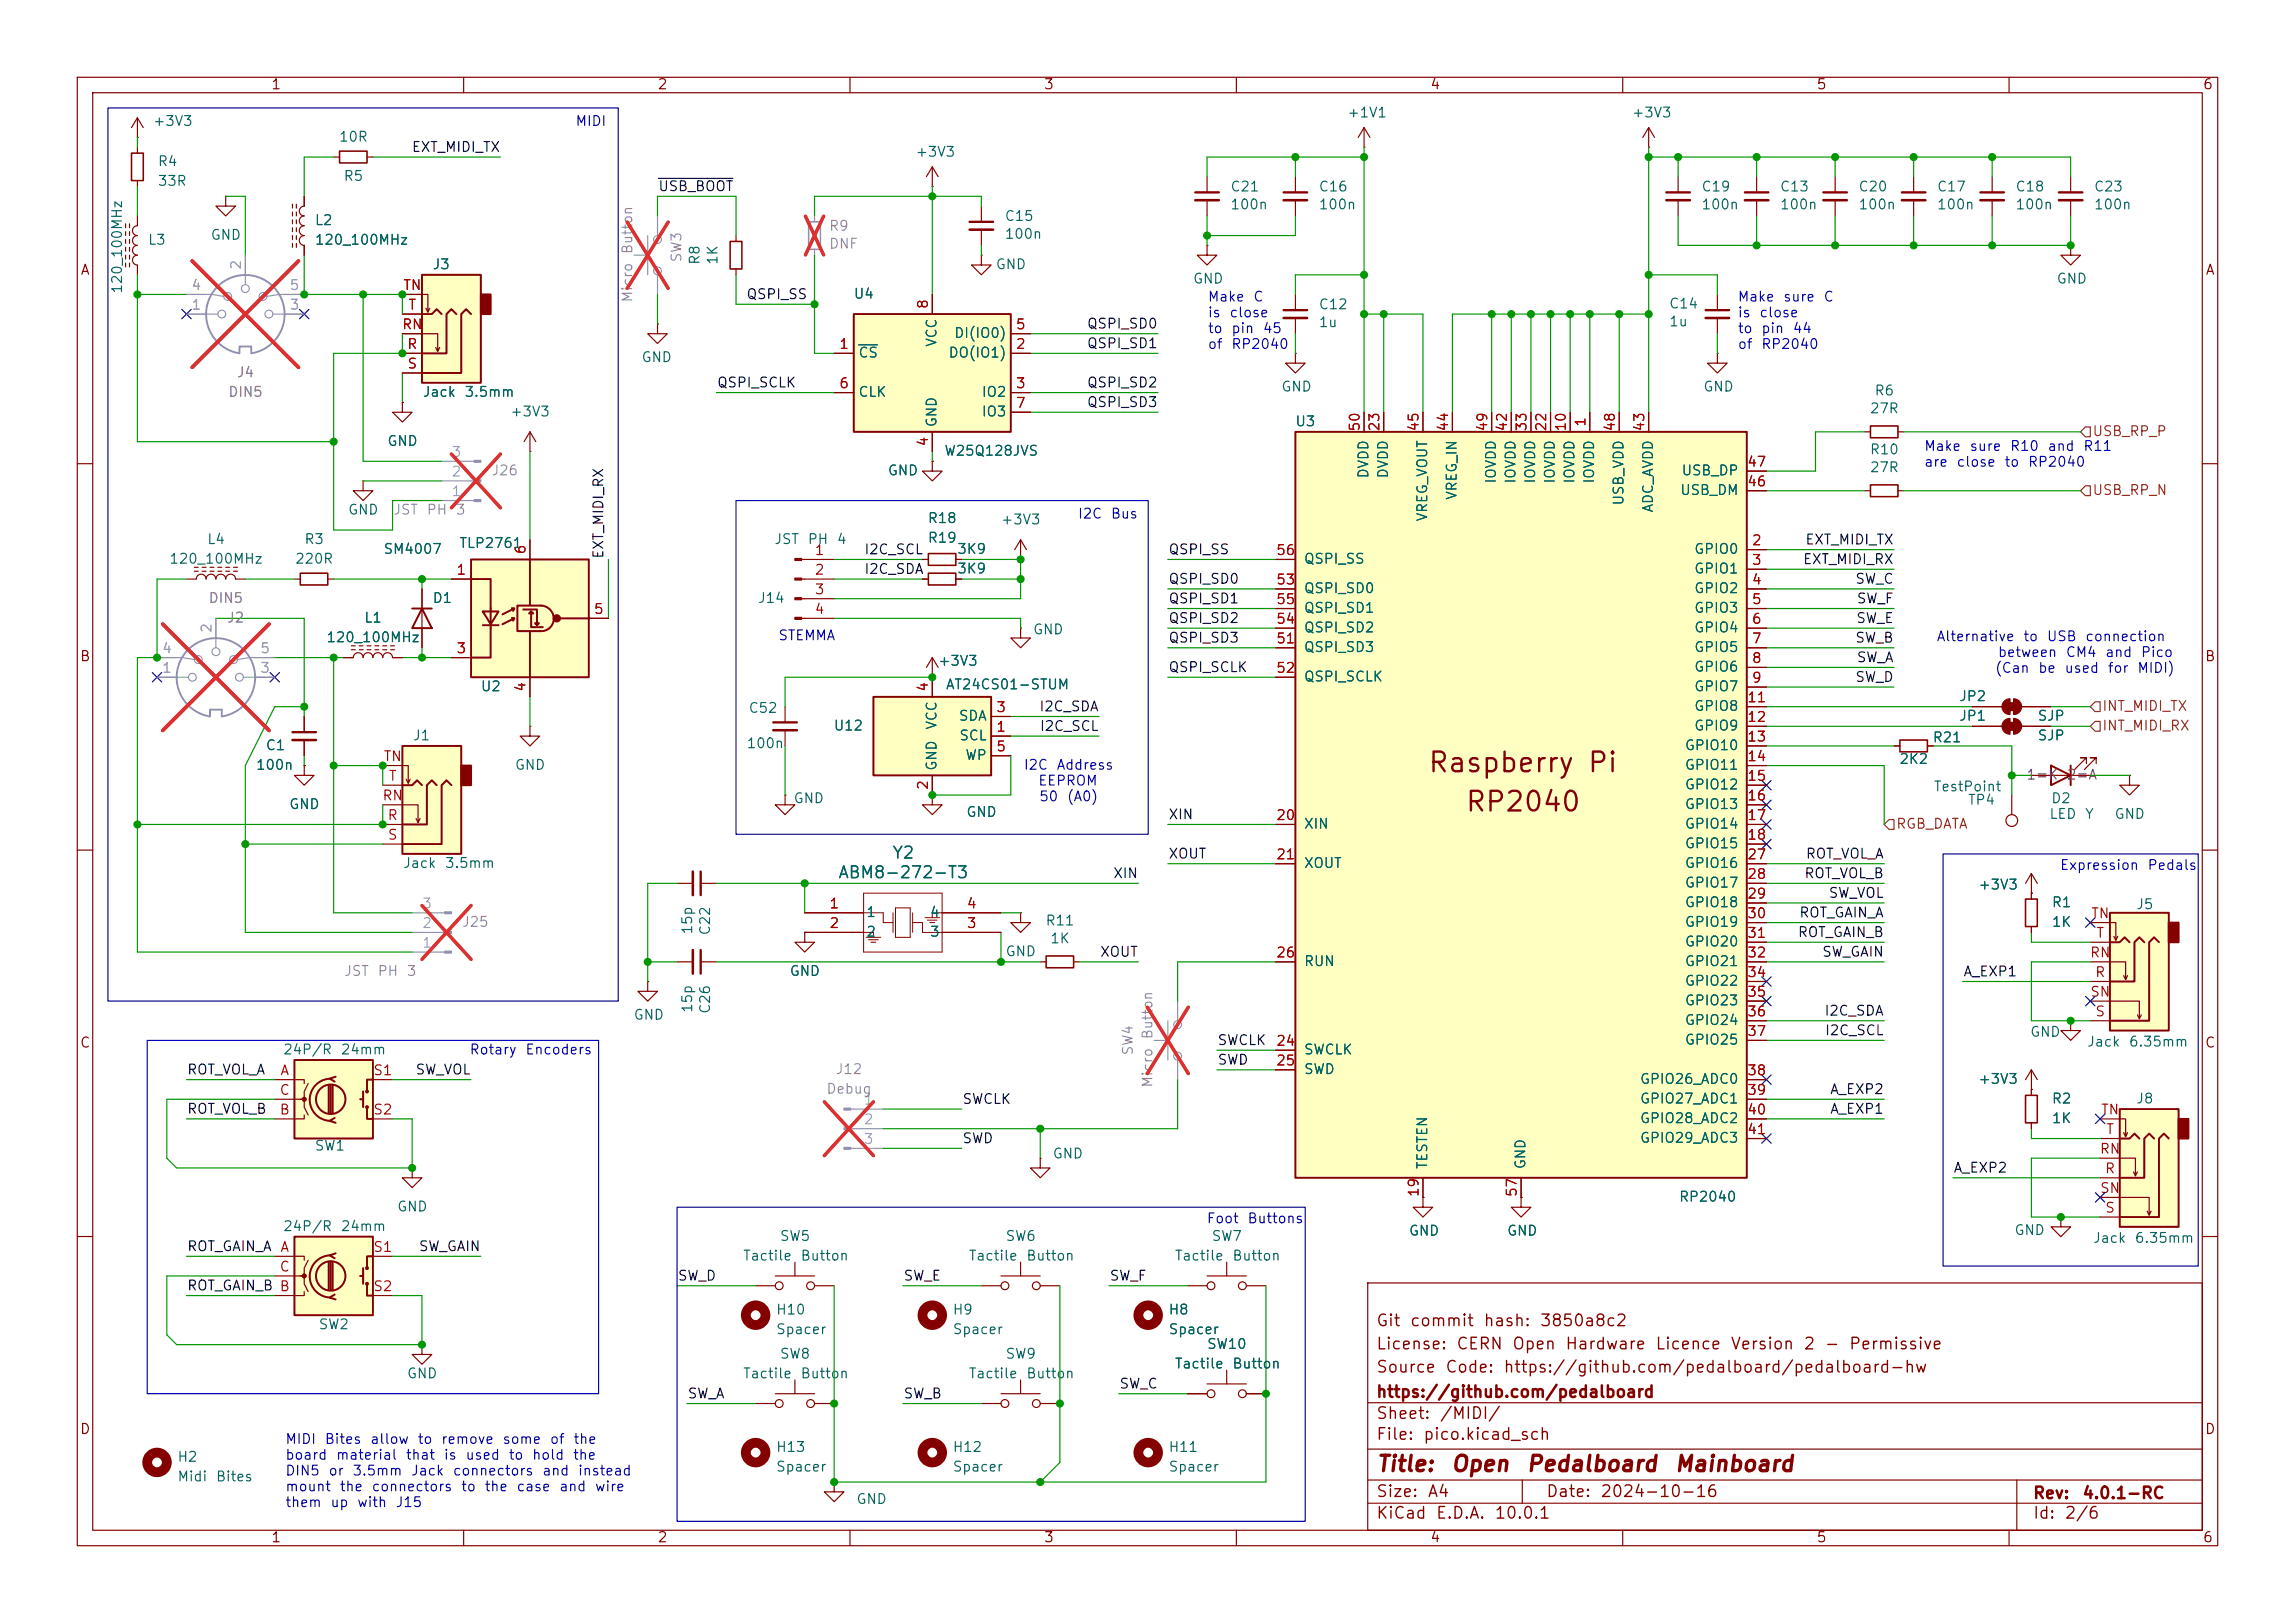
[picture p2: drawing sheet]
<svg xmlns="http://www.w3.org/2000/svg" width="297mm" height="210mm" viewBox="0 0 297 210" stroke-linecap="round" stroke-linejoin="round" font-family="sans-serif">
<defs><g id="words">
<g font-size="2.5" fill="#840000">
<text x="184.7" y="100.6">Raspberry Pi</text>
<text x="189.5" y="105.6">RP2040</text>
</g>
<g font-size="2" fill="#840000">
<text x="178" y="190.9">Title:</text>
<text x="187.7" y="190.9">Open</text>
<text x="197.4" y="190.9">Pedalboard</text>
<text x="216.6" y="190.9">Mainboard</text>
</g>
<g font-size="1.5" fill="#006464">
<text x="115.4" y="111.5">Y2</text>
<text x="108.4" y="114">ABM8-272-T3</text>
</g>
<g font-size="1.5" fill="#840000">
<text x="178" y="172">Git</text>
<text x="182.4" y="172">commit</text>
<text x="191.9" y="172">hash:</text>
<text x="199.2" y="172">3850a8c2</text>
<text x="178" y="178">Source</text>
<text x="178" y="175">License:</text>
<text x="186.9" y="178">Code:</text>
<text x="188.4" y="175">CERN</text>
<text x="194.5" y="178">https://github.com/pedalboard/pedalboard-hw</text>
<text x="195.6" y="175">Open</text>
<text x="202.5" y="175">Hardware</text>
<text x="214.1" y="175">Licence</text>
<text x="223.9" y="175">Version</text>
<text x="233.3" y="175">2</text>
<text x="236" y="175">-</text>
<text x="239.2" y="175">Permissive</text>
<text x="178" y="184">Sheet:</text>
<text x="178" y="181.2">https://github.com/pedalboard</text>
<text x="186.2" y="184">/MIDI/</text>
<text x="178" y="186.7">File:</text>
<text x="184.1" y="186.7">pico.kicad_sch</text>
<text x="178" y="196.9">KiCad</text>
<text x="178" y="194.1">Size:</text>
<text x="184.7" y="194.1">A4</text>
<text x="185.7" y="196.9">E.D.A.</text>
<text x="193.3" y="196.9">10.0.1</text>
<text x="200" y="194.1">Date:</text>
<text x="207" y="194.1">2024-10-16</text>
<text x="263" y="194.3">Rev:</text>
<text x="263" y="196.9">Id:</text>
<text x="267.1" y="196.9">2/6</text>
<text x="269.4" y="194.3">4.0.1-RC</text>
</g>
<g font-size="1.3" fill="#840000">
<text x="35" y="11.9">1</text>
<text x="85" y="11.9">2</text>
<text x="135" y="11.9">3</text>
<text x="185" y="11.9">4</text>
<text x="235" y="11.9">5</text>
<text x="285" y="11.9">6</text>
<text x="10.3" y="35.9">A</text>
<text x="285.3" y="35.9">A</text>
<text x="10.3" y="85.9">B</text>
<text x="285.3" y="85.9">B</text>
<text x="10.3" y="135.9">C</text>
<text x="285.3" y="135.9">C</text>
<text x="10.3" y="185.9">D</text>
<text x="285.3" y="185.9">D</text>
<text x="35" y="199.9">1</text>
<text x="85" y="199.9">2</text>
<text x="135" y="199.9">3</text>
<text x="185" y="199.9">4</text>
<text x="235" y="199.9">5</text>
<text x="285" y="199.9">6</text>
</g>
<g font-size="1.3" fill="#006464">
<text x="19.7" y="16.6">+3V3</text>
<text x="174.3" y="15.5">+1V1</text>
<text x="211.1" y="15.5">+3V3</text>
<text x="20.3" y="21.8">R4</text>
<text x="43.8" y="18.6">10R</text>
<text x="44.4" y="23.7">R5</text>
<text x="118.4" y="20.6">+3V3</text>
<text x="20.3" y="24.4">33R</text>
<text x="40.6" y="29.4">L2</text>
<text x="129.9" y="28.9">C15</text>
<text x="159.1" y="27.4">100n</text>
<text x="159.1" y="25.1">C21</text>
<text x="170.6" y="27.4">100n</text>
<text x="170.6" y="25.1">C16</text>
<text x="220.1" y="27.4">100n</text>
<text x="220.1" y="25.1">C19</text>
<text x="230.3" y="27.4">100n</text>
<text x="230.3" y="25.1">C13</text>
<text x="240.4" y="27.4">100n</text>
<text x="240.4" y="25.1">C20</text>
<text x="250.6" y="27.4">100n</text>
<text x="250.6" y="25.1">C17</text>
<text x="260.7" y="27.4">100n</text>
<text x="260.7" y="25.1">C18</text>
<text x="270.9" y="27.4">100n</text>
<text x="270.9" y="25.1">C23</text>
<text x="19.1" y="32">L3</text>
<text x="27.2" y="31.3">GND</text>
<text x="40.6" y="32">120_100MHz</text>
<text x="55.9" y="35.2">J3</text>
<text x="90.9" y="34.4" transform="rotate(-90 90.9 34.4)">R8</text>
<text x="93.2" y="34.4" transform="rotate(-90 93.2 34.4)">1K</text>
<text x="128.8" y="35.2">GND</text>
<text x="129.9" y="31.2">100n</text>
<text x="16.1" y="38.1" transform="rotate(-90 16.1 38.1)">120_100MHz</text>
<text x="110.4" y="39">U4</text>
<text x="154.3" y="37">GND</text>
<text x="170.6" y="40.3">C12</text>
<text x="215.9" y="40.2">C14</text>
<text x="266.1" y="37">GND</text>
<text x="82.9" y="47.2">GND</text>
<text x="111" y="46.6">CS</text>
<text x="121.5" y="45" transform="rotate(-90 121.5 45)">VCC</text>
<text x="122.7" y="46.6">DO(IO1)</text>
<text x="123.4" y="44">DI(IO0)</text>
<text x="170.6" y="42.6">1u</text>
<text x="215.9" y="42.5">1u</text>
<text x="54.6" y="51.7">Jack</text>
<text x="60" y="51.7">3.5mm</text>
<text x="111" y="51.7">CLK</text>
<text x="127" y="51.7">IO2</text>
<text x="165.7" y="51">GND</text>
<text x="220.3" y="51">GND</text>
<text x="241.9" y="53.8">27R</text>
<text x="242.5" y="51.5">R6</text>
<text x="50" y="58">GND</text>
<text x="65.9" y="54.2">+3V3</text>
<text x="121.5" y="55.4" transform="rotate(-90 121.5 55.4)">GND</text>
<text x="122.1" y="59.3">W25Q128JVS</text>
<text x="127" y="54.2">IO3</text>
<text x="167.5" y="55.5">U3</text>
<text x="241.9" y="59.1">R10</text>
<text x="114.8" y="61.8">GND</text>
<text x="177.4" y="62" transform="rotate(-90 177.4 62)">DVDD</text>
<text x="179.9" y="62" transform="rotate(-90 179.9 62)">DVDD</text>
<text x="188.8" y="64.8" transform="rotate(-90 188.8 64.8)">VREG_IN</text>
<text x="193.9" y="62.7" transform="rotate(-90 193.9 62.7)">IOVDD</text>
<text x="196.4" y="62.7" transform="rotate(-90 196.4 62.7)">IOVDD</text>
<text x="199" y="62.7" transform="rotate(-90 199 62.7)">IOVDD</text>
<text x="201.5" y="62.7" transform="rotate(-90 201.5 62.7)">IOVDD</text>
<text x="204.1" y="62.7" transform="rotate(-90 204.1 62.7)">IOVDD</text>
<text x="206.6" y="62.7" transform="rotate(-90 206.6 62.7)">IOVDD</text>
<text x="210.4" y="65.5" transform="rotate(-90 210.4 65.5)">USB_VDD</text>
<text x="217.3" y="64.4">USB_DM</text>
<text x="217.5" y="61.8">USB_DP</text>
<text x="241.9" y="61.4">27R</text>
<text x="26.7" y="70.7">L4</text>
<text x="39.3" y="70.7">R3</text>
<text x="45" y="66.9">GND</text>
<text x="49.5" y="72">SM4007</text>
<text x="59.3" y="71.2">TLP2761</text>
<text x="100.1" y="70.7">JST</text>
<text x="104.4" y="70.7">PH</text>
<text x="108.2" y="70.7">4</text>
<text x="120" y="70.5">R19</text>
<text x="120" y="68">R18</text>
<text x="123.8" y="72">3K9</text>
<text x="129.4" y="68.2">+3V3</text>
<text x="185" y="67.6" transform="rotate(-90 185 67.6)">VREG_VOUT</text>
<text x="214.2" y="66.4" transform="rotate(-90 214.2 66.4)">ADC_AVDD</text>
<text x="219.2" y="72">GPIO0</text>
<text x="21.8" y="73.3">120_100MHz</text>
<text x="38.1" y="73.3">220R</text>
<text x="123.8" y="74.5">3K9</text>
<text x="168.7" y="77.1">QSPI_SD0</text>
<text x="168.7" y="73.3">QSPI_SS</text>
<text x="219.2" y="74.5">GPIO1</text>
<text x="219.2" y="77.1">GPIO2</text>
<text x="42.1" y="83.4">120_100MHz</text>
<text x="47" y="80.9">L1</text>
<text x="55.9" y="78.3">D1</text>
<text x="98" y="78.3">J14</text>
<text x="133.6" y="82.4">GND</text>
<text x="168.7" y="82.1">QSPI_SD2</text>
<text x="168.7" y="79.6">QSPI_SD1</text>
<text x="219.2" y="79.6">GPIO3</text>
<text x="219.2" y="82.1">GPIO4</text>
<text x="62.1" y="89.8">U2</text>
<text x="121.3" y="86.5">+3V3</text>
<text x="122.3" y="89.5">AT24CS01-STUM</text>
<text x="168.7" y="84.7">QSPI_SD3</text>
<text x="168.7" y="88.5">QSPI_SCLK</text>
<text x="219.2" y="84.7">GPIO5</text>
<text x="219.2" y="87.2">GPIO6</text>
<text x="219.2" y="89.8">GPIO7</text>
<text x="96.8" y="92.6">C52</text>
<text x="107.8" y="94.8">U12</text>
<text x="121.5" y="94.5" transform="rotate(-90 121.5 94.5)">VCC</text>
<text x="124" y="93.6">SDA</text>
<text x="219.2" y="92.3">GPIO8</text>
<text x="219.2" y="94.8">GPIO9</text>
<text x="253.4" y="93.6">JP1</text>
<text x="253.4" y="91">JP2</text>
<text x="263.6" y="93.6">SJP</text>
<text x="33" y="99.9">100n</text>
<text x="34.3" y="97.4">C1</text>
<text x="53.3" y="96.1">J1</text>
<text x="66.5" y="99.9">GND</text>
<text x="96.5" y="97.1">100n</text>
<text x="121.5" y="99.8" transform="rotate(-90 121.5 99.8)">GND</text>
<text x="124.1" y="96.1">SCL</text>
<text x="124.8" y="98.7">WP</text>
<text x="217.9" y="97.4">GPIO10</text>
<text x="217.9" y="99.9">GPIO11</text>
<text x="245.7" y="99.2">2K2</text>
<text x="250" y="96.4">R21</text>
<text x="263.6" y="96.1">SJP</text>
<text x="37.3" y="105">GND</text>
<text x="102.6" y="104.2">GND</text>
<text x="125" y="106">GND</text>
<text x="168.7" y="107.5">XIN</text>
<text x="217.9" y="102.5">GPIO12</text>
<text x="217.9" y="105">GPIO13</text>
<text x="217.9" y="107.5">GPIO14</text>
<text x="250.2" y="102.7">TestPoint</text>
<text x="254.6" y="104.4">TP4</text>
<text x="265.1" y="106.3">LED</text>
<text x="265.4" y="104.2">D2</text>
<text x="269.7" y="106.3">Y</text>
<text x="273.6" y="106.3">GND</text>
<text x="52.1" y="112.6">Jack</text>
<text x="57.5" y="112.6">3.5mm</text>
<text x="168.7" y="112.6">XOUT</text>
<text x="217.9" y="110.1">GPIO15</text>
<text x="217.9" y="112.6">GPIO16</text>
<text x="112" y="119">1</text>
<text x="120.3" y="119">4</text>
<text x="217.9" y="115.2">GPIO17</text>
<text x="217.9" y="117.7">GPIO18</text>
<text x="255.9" y="115.4">+3V3</text>
<text x="265.4" y="117.7">R1</text>
<text x="276.4" y="118">J5</text>
<text x="89.9" y="121" transform="rotate(-90 89.9 121)">15p</text>
<text x="92.2" y="121.1" transform="rotate(-90 92.2 121.1)">C22</text>
<text x="112" y="121.5">2</text>
<text x="120.3" y="121.5">3</text>
<text x="130" y="124.1">GND</text>
<text x="135.2" y="120.1">R11</text>
<text x="135.8" y="122.4">1K</text>
<text x="168.7" y="125.3">RUN</text>
<text x="217.9" y="120.2">GPIO19</text>
<text x="217.9" y="122.8">GPIO20</text>
<text x="217.9" y="125.3">GPIO21</text>
<text x="265.4" y="120.2">1K</text>
<text x="89.9" y="131.2" transform="rotate(-90 89.9 131.2)">15p</text>
<text x="92.2" y="131.3" transform="rotate(-90 92.2 131.3)">C26</text>
<text x="102.1" y="126.6">GND</text>
<text x="217.9" y="127.9">GPIO22</text>
<text x="217.9" y="130.4">GPIO23</text>
<text x="36.5" y="136.8">24P/R</text>
<text x="44" y="136.8">24mm</text>
<text x="81.9" y="132.3">GND</text>
<text x="168.7" y="136.8">SWCLK</text>
<text x="217.9" y="132.9">GPIO24</text>
<text x="217.9" y="135.5">GPIO25</text>
<text x="262.6" y="134.5">GND</text>
<text x="270" y="135.7">Jack</text>
<text x="275.4" y="135.7">6.35mm</text>
<text x="168.7" y="139.3">SWD</text>
<text x="212.1" y="140.6">GPIO26_ADC0</text>
<text x="212.1" y="143.1">GPIO27_ADC1</text>
<text x="255.9" y="140.6">+3V3</text>
<text x="265.4" y="143.1">R2</text>
<text x="276.4" y="143.1">J8</text>
<text x="40.6" y="149.2">SW1</text>
<text x="212.1" y="145.6">GPIO28_ADC2</text>
<text x="212.1" y="148.2">GPIO29_ADC3</text>
<text x="265.4" y="145.6">1K</text>
<text x="136.1" y="150.2">GND</text>
<text x="185" y="151.4" transform="rotate(-90 185 151.4)">TESTEN</text>
<text x="197.7" y="151.4" transform="rotate(-90 197.7 151.4)">GND</text>
<text x="217.2" y="155.8">RP2040</text>
<text x="36.5" y="159.6">24P/R</text>
<text x="44" y="159.6">24mm</text>
<text x="51.3" y="157.1">GND</text>
<text x="100.8" y="160.9">SW5</text>
<text x="130" y="160.9">SW6</text>
<text x="156.7" y="160.9">SW7</text>
<text x="182.2" y="160.2">GND</text>
<text x="194.9" y="160.2">GND</text>
<text x="260.6" y="160.1">GND</text>
<text x="270.8" y="161.1">Jack</text>
<text x="276.2" y="161.1">6.35mm</text>
<text x="96.1" y="163.4">Tactile</text>
<text x="103.5" y="163.4">Button</text>
<text x="125.3" y="163.4">Tactile</text>
<text x="132.7" y="163.4">Button</text>
<text x="151.9" y="163.4">Tactile</text>
<text x="159.4" y="163.4">Button</text>
<text x="41.1" y="172.3">SW2</text>
<text x="100.3" y="170.4">H10</text>
<text x="100.3" y="172.9">Spacer</text>
<text x="123.2" y="172.9">Spacer</text>
<text x="123.2" y="170.4">H9</text>
<text x="151.1" y="172.9">Spacer</text>
<text x="151.1" y="170.4">H8</text>
<text x="52.6" y="178.7">GND</text>
<text x="96.1" y="178.7">Tactile</text>
<text x="100.8" y="176.1">SW8</text>
<text x="103.5" y="178.7">Button</text>
<text x="125.3" y="178.7">Tactile</text>
<text x="130" y="176.1">SW9</text>
<text x="132.7" y="178.7">Button</text>
<text x="151.9" y="177.4">Tactile</text>
<text x="156.1" y="174.9">SW10</text>
<text x="159.4" y="177.4">Button</text>
<text x="22.9" y="189.5">H2</text>
<text x="22.9" y="192">Midi</text>
<text x="27.9" y="192">Bites</text>
<text x="100.3" y="188.2">H13</text>
<text x="100.3" y="190.7">Spacer</text>
<text x="123.2" y="188.2">H12</text>
<text x="123.2" y="190.7">Spacer</text>
<text x="151.1" y="188.2">H11</text>
<text x="151.1" y="190.7">Spacer</text>
<text x="110.7" y="194.9">GND</text>
</g>
<g font-size="1.3" fill="#0000c2">
<text x="74.4" y="16.6">MIDI</text>
<text x="156.2" y="39.3">Make</text>
<text x="156.2" y="41.4">is</text>
<text x="159" y="41.4">close</text>
<text x="162.1" y="39.3">C</text>
<text x="224.8" y="39.3">Make</text>
<text x="224.8" y="41.4">is</text>
<text x="227.6" y="41.4">close</text>
<text x="230.7" y="39.3">sure</text>
<text x="235.9" y="39.3">C</text>
<text x="156.2" y="43.4">to</text>
<text x="156.2" y="45.5">of</text>
<text x="159.3" y="43.4">pin</text>
<text x="159.3" y="45.5">RP2040</text>
<text x="163.3" y="43.4">45</text>
<text x="224.8" y="43.4">to</text>
<text x="224.8" y="45.5">of</text>
<text x="227.8" y="43.4">pin</text>
<text x="227.8" y="45.5">RP2040</text>
<text x="231.9" y="43.4">44</text>
<text x="248.9" y="58.7">Make</text>
<text x="254.8" y="58.7">sure</text>
<text x="260" y="58.7">R10</text>
<text x="264.9" y="58.7">and</text>
<text x="269.5" y="58.7">R11</text>
<text x="248.9" y="60.7">are</text>
<text x="253.1" y="60.7">close</text>
<text x="259.3" y="60.7">to</text>
<text x="262.4" y="60.7">RP2040</text>
<text x="139.4" y="67.4">I2C</text>
<text x="143.7" y="67.4">Bus</text>
<text x="100.6" y="83.2">STEMMA</text>
<text x="250.5" y="83.3">Alternative</text>
<text x="261.7" y="83.3">to</text>
<text x="264.8" y="83.3">USB</text>
<text x="269.8" y="83.3">connection</text>
<text x="258.1" y="87.4">(Can</text>
<text x="258.5" y="85.3">between</text>
<text x="263.7" y="87.4">be</text>
<text x="267.1" y="87.4">used</text>
<text x="267.2" y="85.3">CM4</text>
<text x="272.3" y="85.3">and</text>
<text x="272.7" y="87.4">for</text>
<text x="276.5" y="87.4">MIDI)</text>
<text x="277" y="85.3">Pico</text>
<text x="132.4" y="99.9">I2C</text>
<text x="134.3" y="102">EEPROM</text>
<text x="136.6" y="99.9">Address</text>
<text x="134.4" y="104">50</text>
<text x="138" y="104">(A0)</text>
<text x="266.5" y="112.9">Expression</text>
<text x="277.8" y="112.9">Pedals</text>
<text x="60.7" y="136.8">Rotary</text>
<text x="67.9" y="136.8">Encoders</text>
<text x="156.1" y="158.6">Foot</text>
<text x="161.3" y="158.6">Buttons</text>
<text x="36.8" y="187.2">MIDI</text>
<text x="36.8" y="189.2">board</text>
<text x="36.8" y="191.2">DIN5</text>
<text x="41.9" y="187.2">Bites</text>
<text x="42.4" y="191.2">or</text>
<text x="43.4" y="189.2">material</text>
<text x="45.5" y="191.2">3.5mm</text>
<text x="47.8" y="187.2">allow</text>
<text x="52.4" y="189.2">that</text>
<text x="53.1" y="191.2">Jack</text>
<text x="53.9" y="187.2">to</text>
<text x="57" y="187.2">remove</text>
<text x="57.3" y="189.2">is</text>
<text x="58.5" y="191.2">connectors</text>
<text x="60.1" y="189.2">used</text>
<text x="64.9" y="187.2">some</text>
<text x="65.7" y="189.2">to</text>
<text x="68.8" y="189.2">hold</text>
<text x="70.1" y="191.2">and</text>
<text x="71.1" y="187.2">of</text>
<text x="74.1" y="189.2">the</text>
<text x="74.1" y="187.2">the</text>
<text x="74.7" y="191.2">instead</text>
<text x="36.8" y="193.3">mount</text>
<text x="36.8" y="195.3">them</text>
<text x="42.7" y="195.3">up</text>
<text x="43.9" y="193.3">the</text>
<text x="46.1" y="195.3">with</text>
<text x="48" y="193.3">connectors</text>
<text x="51.1" y="195.3">J15</text>
<text x="59.6" y="193.3">to</text>
<text x="62.6" y="193.3">the</text>
<text x="66.8" y="193.3">case</text>
<text x="72.3" y="193.3">and</text>
<text x="76.9" y="193.3">wire</text>
</g>
<g font-size="1.3" fill="#0f0f0f">
<text x="53.2" y="20">EXT_MIDI_TX</text>
<text x="85.1" y="25.1">USB_BOOT</text>
<text x="96.5" y="39">QSPI_SS</text>
<text x="140.6" y="45.4">QSPI_SD1</text>
<text x="140.6" y="42.8">QSPI_SD0</text>
<text x="92.7" y="50.5">QSPI_SCLK</text>
<text x="140.6" y="53">QSPI_SD3</text>
<text x="140.6" y="50.5">QSPI_SD2</text>
<text x="233.5" y="70.8">EXT_MIDI_TX</text>
<text x="78.4" y="72.4" transform="rotate(-90 78.4 72.4)">EXT_MIDI_RX</text>
<text x="111.8" y="74.6">I2C_SDA</text>
<text x="111.8" y="72">I2C_SCL</text>
<text x="151.1" y="75.9">QSPI_SD0</text>
<text x="151.1" y="72">QSPI_SS</text>
<text x="233.2" y="73.3">EXT_MIDI_RX</text>
<text x="240" y="75.9">SW_C</text>
<text x="151.1" y="80.9">QSPI_SD2</text>
<text x="151.1" y="83.5">QSPI_SD3</text>
<text x="151.1" y="78.4">QSPI_SD1</text>
<text x="240" y="83.5">SW_B</text>
<text x="240.1" y="80.9">SW_E</text>
<text x="240.2" y="78.4">SW_F</text>
<text x="151.1" y="87.3">QSPI_SCLK</text>
<text x="240" y="88.6">SW_D</text>
<text x="240.2" y="86">SW_A</text>
<text x="134.4" y="92.4">I2C_SDA</text>
<text x="134.5" y="94.9">I2C_SCL</text>
<text x="151.1" y="106.3">XIN</text>
<text x="144" y="114">XIN</text>
<text x="151.1" y="111.4">XOUT</text>
<text x="233.4" y="114">ROT_VOL_B</text>
<text x="233.6" y="111.4">ROT_VOL_A</text>
<text x="232.8" y="119">ROT_GAIN_A</text>
<text x="236.6" y="116.5">SW_VOL</text>
<text x="142.3" y="124.1">XOUT</text>
<text x="232.6" y="121.6">ROT_GAIN_B</text>
<text x="235.7" y="124.1">SW_GAIN</text>
<text x="236" y="131.7">I2C_SDA</text>
<text x="254" y="126.7">A_EXP1</text>
<text x="157.5" y="135.5">SWCLK</text>
<text x="236.1" y="134.3">I2C_SCL</text>
<text x="24.1" y="139.4">ROT_VOL_A</text>
<text x="53.7" y="139.4">SW_VOL</text>
<text x="124.5" y="143.2">SWCLK</text>
<text x="157.5" y="138.1">SWD</text>
<text x="236.7" y="141.9">A_EXP2</text>
<text x="24.1" y="144.4">ROT_VOL_B</text>
<text x="124.5" y="148.2">SWD</text>
<text x="236.7" y="144.4">A_EXP1</text>
<text x="252.7" y="152.1">A_EXP2</text>
<text x="24.1" y="167.3">ROT_GAIN_B B</text>
<text x="24.1" y="162.2">ROT_GAIN_A</text>
<text x="54.1" y="162.2">SW_GAIN</text>
<text x="87.6" y="166">SW_D</text>
<text x="116.8" y="166">SW_E</text>
<text x="143.5" y="166">SW_F</text>
<text x="144.8" y="180">SW_C</text>
<text x="88.9" y="181.3">SW_A</text>
<text x="116.8" y="181.3">SW_B</text>
</g>
<g font-size="1.3" fill="#a5a4a2">
<text x="31.5" y="35" transform="rotate(-90 31.5 35)">2</text>
<text x="24.7" y="40.4">1</text>
<text x="24.7" y="37.8">4</text>
<text x="37.4" y="40.4">3</text>
<text x="37.4" y="37.8">5</text>
<text x="58.3" y="59.4">3</text>
<text x="58.3" y="64.5">1</text>
<text x="58.3" y="62">2</text>
<text x="27.7" y="82" transform="rotate(-90 27.7 82)">2</text>
<text x="20.9" y="87.4">1</text>
<text x="20.9" y="84.8">4</text>
<text x="33.6" y="87.4">3</text>
<text x="33.6" y="84.8">5</text>
<text x="54.5" y="117.9">3</text>
<text x="54.5" y="122.9">1</text>
<text x="54.5" y="120.4">2</text>
<text x="111.7" y="143.3">1</text>
<text x="111.7" y="145.8">2</text>
<text x="111.7" y="148.3">3</text>
</g>
<g font-size="1.3" fill="#939391">
<text x="82.1" y="33" transform="rotate(-90 82.1 33)">Button</text>
<text x="88.5" y="34" transform="rotate(-90 88.5 34)">SW3</text>
<text x="107.2" y="30.2">R9</text>
<text x="107.2" y="32.5">DNF</text>
<text x="82.1" y="39.2" transform="rotate(-90 82.1 39.2)">Micro</text>
<text x="29.4" y="51.7">DIN5</text>
<text x="30.6" y="49.1">J4</text>
<text x="63.5" y="61.8">J26</text>
<text x="50.8" y="66.9">JST</text>
<text x="55.1" y="66.9">PH</text>
<text x="58.9" y="66.9">3</text>
<text x="26.9" y="78.3">DIN5</text>
<text x="29.3" y="80.9">J2</text>
<text x="59.7" y="120.2">J25</text>
<text x="44.5" y="126.6">JST</text>
<text x="48.8" y="126.6">PH</text>
<text x="52.5" y="126.6">3</text>
<text x="146.9" y="136.7" transform="rotate(-90 146.9 136.7)">SW4</text>
<text x="149.5" y="134.6" transform="rotate(-90 149.5 134.6)">Button</text>
<text x="106.9" y="141.8">Debug</text>
<text x="108.1" y="139.3">J12</text>
<text x="149.5" y="140.8" transform="rotate(-90 149.5 140.8)">Micro</text>
</g>
<g font-size="1.3" fill="#a90000">
<text x="52.1" y="37.8">TN</text>
<text x="52.8" y="40.4">T</text>
<text x="120.4" y="40.1" transform="rotate(-90 120.4 40.1)">8</text>
<text x="51.9" y="42.9">RN</text>
<text x="52.6" y="45.5">R</text>
<text x="108.5" y="45.5">1</text>
<text x="131.4" y="45.5">2</text>
<text x="131.4" y="42.9">5</text>
<text x="52.6" y="48">S</text>
<text x="108.5" y="50.5">6</text>
<text x="131.4" y="50.5">3</text>
<text x="131.4" y="53.1">7</text>
<text x="120.4" y="57.9" transform="rotate(-90 120.4 57.9)">4</text>
<text x="176.3" y="55.9" transform="rotate(-90 176.3 55.9)">50</text>
<text x="178.8" y="55.9" transform="rotate(-90 178.8 55.9)">23</text>
<text x="183.9" y="55.9" transform="rotate(-90 183.9 55.9)">45</text>
<text x="187.7" y="55.9" transform="rotate(-90 187.7 55.9)">44</text>
<text x="192.8" y="55.9" transform="rotate(-90 192.8 55.9)">49</text>
<text x="195.3" y="55.9" transform="rotate(-90 195.3 55.9)">42</text>
<text x="197.9" y="55.9" transform="rotate(-90 197.9 55.9)">33</text>
<text x="200.4" y="55.9" transform="rotate(-90 200.4 55.9)">22</text>
<text x="202.9" y="55.9" transform="rotate(-90 202.9 55.9)">10</text>
<text x="205.5" y="55.3" transform="rotate(-90 205.5 55.3)">1</text>
<text x="209.3" y="55.9" transform="rotate(-90 209.3 55.9)">48</text>
<text x="213.1" y="55.9" transform="rotate(-90 213.1 55.9)">43</text>
<text x="226" y="63.2">46</text>
<text x="226" y="60.7">47</text>
<text x="68.3" y="71.8" transform="rotate(-90 68.3 71.8)">6</text>
<text x="226.6" y="70.9">2</text>
<text x="59" y="74.7">1</text>
<text x="105.3" y="72.1">1</text>
<text x="105.3" y="74.7">2</text>
<text x="105.3" y="77.2">3</text>
<text x="165.1" y="75.9">53</text>
<text x="165.1" y="72.1">56</text>
<text x="226.6" y="73.4">3</text>
<text x="226.6" y="75.9">4</text>
<text x="76.8" y="79.8">5</text>
<text x="105.3" y="79.8">4</text>
<text x="165.1" y="83.6">51</text>
<text x="165.1" y="81">54</text>
<text x="165.1" y="78.5">55</text>
<text x="226.6" y="78.5">5</text>
<text x="226.6" y="81">6</text>
<text x="226.6" y="83.6">7</text>
<text x="59" y="84.8">3</text>
<text x="68.3" y="89.6" transform="rotate(-90 68.3 89.6)">4</text>
<text x="120.4" y="89.6" transform="rotate(-90 120.4 89.6)">4</text>
<text x="165.1" y="87.4">52</text>
<text x="226.6" y="86.1">8</text>
<text x="226.6" y="88.6">9</text>
<text x="128.8" y="95">1</text>
<text x="128.8" y="92.5">3</text>
<text x="226" y="91.2">11</text>
<text x="226" y="93.7">12</text>
<text x="49.5" y="98.8">TN</text>
<text x="50.2" y="101.3">T</text>
<text x="128.8" y="97.5">5</text>
<text x="226" y="96.3">13</text>
<text x="226" y="98.8">14</text>
<text x="226" y="101.3">15</text>
<text x="49.4" y="103.9">RN</text>
<text x="50.1" y="106.4">R</text>
<text x="120.4" y="102.3" transform="rotate(-90 120.4 102.3)">2</text>
<text x="165.1" y="106.4">20</text>
<text x="226" y="103.9">16</text>
<text x="226" y="106.4">17</text>
<text x="50.1" y="109">S</text>
<text x="165.1" y="111.5">21</text>
<text x="226" y="109">18</text>
<text x="226" y="111.5">27</text>
<text x="107.2" y="117.9">1</text>
<text x="125" y="117.9">4</text>
<text x="226" y="114">28</text>
<text x="226" y="116.6">29</text>
<text x="226" y="119.1">30</text>
<text x="270.5" y="119.1">TN</text>
<text x="107.2" y="120.4">2</text>
<text x="125" y="120.4">3</text>
<text x="165.1" y="124.2">26</text>
<text x="226" y="121.7">31</text>
<text x="226" y="124.2">32</text>
<text x="270.4" y="124.2">RN</text>
<text x="271.2" y="121.7">T</text>
<text x="226" y="126.7">34</text>
<text x="226" y="129.3">35</text>
<text x="226" y="131.8">36</text>
<text x="270.4" y="129.3">SN</text>
<text x="271" y="126.7">R</text>
<text x="271.1" y="131.8">S</text>
<text x="165.1" y="135.6">24</text>
<text x="226" y="134.4">37</text>
<text x="36.1" y="142">C</text>
<text x="36.2" y="139.4">A</text>
<text x="48.2" y="139.4">S1</text>
<text x="165.1" y="138.2">25</text>
<text x="226" y="139.4">38</text>
<text x="226" y="142">39</text>
<text x="36.1" y="144.5">B</text>
<text x="48.2" y="144.5">S2</text>
<text x="226" y="144.5">40</text>
<text x="226" y="147.1">41</text>
<text x="271.6" y="149.6">RN</text>
<text x="271.8" y="144.5">TN</text>
<text x="272.5" y="147.1">T</text>
<text x="183.9" y="155" transform="rotate(-90 183.9 155)">19</text>
<text x="196.6" y="155" transform="rotate(-90 196.6 155)">57</text>
<text x="271.7" y="154.7">SN</text>
<text x="272.3" y="152.1">R</text>
<text x="272.3" y="157.2">S</text>
<text x="36.1" y="164.8">C</text>
<text x="36.2" y="162.3">A</text>
<text x="48.2" y="162.3">S1</text>
<text x="48.2" y="167.4">S2</text>
</g>
<g font-size="1.3" fill="#725600">
<text x="270.7" y="56.7">USB_RP_P</text>
<text x="270.7" y="64.4">USB_RP_N</text>
<text x="272" y="92.3">INT_MIDI_TX</text>
<text x="272" y="94.8">INT_MIDI_RX</text>
<text x="245.3" y="107.5">RGB_DATA</text>
</g>
<g font-size="1.3" fill="#840084">
<text x="262.2" y="101.2">1=K</text>
<text x="267.4" y="101.2">2=A</text>
</g>
</g></defs>
<g fill="none" stroke="#840000" stroke-width=".15">
<path d="M10 10h277v190h-277zM12 12h273v186h-273zM60 10v2M110 10v2M160 10v2M210 10v2M260 10v2M127 33v1.3h1.3l-1.3 1.3-1.3-1.3h1.3M127 33h.1M10 60h2M285 60h2M10 110h2"/>
<path d="M104.1 118.1h7.7M120.6 102.9v1.2h1.3l-1.3 1.3-1.2-1.3h1.2M120.6 102.9h.1M121.9 118.1h7.6M132.1 118.1v1.3h1.2l-1.2 1.3-1.3-1.3h1.3M132.1 118.1h.1M285 110h2M104.1 120.7h7.7M121.9 120.7h7.6M134.6 124.5h.8M138.9 124.5h.8M10 160h2"/>
<path d="M177 166h108v32h-108zM285 160h2M60 198v2M110 198v2M160 198v2M177 194.5h108M177 191.5h108M177 187.5h108M177 181.5h108M197 191.5v3M210 198v2M260 198v2"/>
<path d="M261 191.5v6.5"/>
</g>
<g fill="none" stroke="#840000" stroke-width=".13">
<path d="M111.8 115.6h10.1v7.6h-10.1zM111.8 118.1h2.5v1.3h1.3M115.6 118.1v2.6M115.9 117.5h1.9v3.8h-1.9zM118.1 119.4h1.3v1.3h2.5M118.1 118.1v2.6M119.7 118.7h1.9M120 119.1h1.3M120.3 119.4h.7M121.9 118.1h-1.3v.6M111.8 120.7h1.2v.6M112.1 121.3h1.9"/>
<path d="M112.4 121.6h1.3M112.7 121.9h.6"/>
</g>
<path d="M135.4 123.7h3.5v1.5h-3.5z" fill="none" stroke="#840000" stroke-width=".2"/>
<path d="M113 90.2h15.3v10.1h-15.3z" fill="#ffffc2"/>
<path d="M113 90.2h15.3v10.1h-15.3z" fill="none" stroke="#840000" stroke-width=".25"/>
<path d="M127 26.7v2M127 29.7v2.1M120.6 87.6v2.6M128.3 95.3h2.5M128.3 92.7h2.5M128.3 97.8h2.5M120.6 100.3v2.6" fill="none" stroke="#840000" stroke-width=".15"/>
<path d="M125.5 28.7h3" fill="none" stroke="#840000" stroke-width=".3"/>
<path d="M125.5 29.7h3" fill="none" stroke="#840000" stroke-width=".33"/>
<path d="M110.5 40.6h20.3v15.3h-20.3z" fill="#ffffc2"/>
<path d="M110.5 40.6h20.3v15.3h-20.3zM53.3 78.7h2.6M54.6 78.7l1.3 2.6h-2.6zM265.4 99.1l2.6 1.2-2.6 1.3zM268 99.1v2.5" fill="none" stroke="#840000" stroke-width=".25"/>
<g fill="none" stroke="#840000" stroke-width=".15">
<path d="M213.4 19.1h.1M213.4 16.5l-.8 1.3M213.4 16.5l.7 1.3M213.4 16.5v2.6M95.2 30.5v.7M95.2 34.8v.8M120.6 24.1h.1M120.6 21.6v2.5M120.6 38.1v2.5M120.6 21.6l-.7 1.3M120.6 21.6l.8 1.3M156.2 31.8v1.2h1.3l-1.3 1.3-1.3-1.3h1.3"/>
<path d="M156.2 31.8h.1M156.2 22.9v2M156.2 25.9v2M217.2 22.9v2M217.2 25.9v2M222.2 38.1v2M237.5 22.9v2M237.5 25.9v2M247.6 22.9v2M247.6 25.9v2M257.8 22.9v2M257.8 25.9v2"/>
<path d="M268 31.8v1.2h1.2l-1.2 1.3-1.3-1.3h1.3M268 31.8h.1M268 22.9v2M268 25.9v2M85.1 41.9v1.3h-1.3l1.3 1.3 1.3-1.3h-1.3M85.1 41.9h.1M107.9 45.7h2.6M107.9 50.8h2.6M120.6 55.9v2.5M130.8 45.7h2.5M130.8 50.8h2.5M130.8 43.2h2.5"/>
<path d="M130.8 53.3h2.5M222.2 45.7v1.3h1.3l-1.3 1.3-1.2-1.3h1.2M222.2 45.7h.1M222.2 41.1v2.1M241.3 55.9h.8M245.6 55.9h.8M47 62.2v1.3h1.3l-1.3 1.3-1.3-1.3h1.3M47 62.2h.1M54.6 76.2v7.6M132.1 72.4h.1M132.1 69.9l-.8 1.2M132.1 69.9l.7 1.2"/>
<path d="M132.1 69.9v2.5M241.3 63.5h.8M245.6 63.5h.8M39.4 99.1v1.2h1.2l-1.2 1.3-1.3-1.3h1.3M39.4 99.1h.1M39.4 92.7v2M39.4 95.8v2M44.4 85.1h1.3a.64 .64 0 0 1 .7-.6 .64 .64 0 0 1 .6 .6 .64 .64 0 0 1 .6-.6 .64 .64 0 0 1 .7 .6 .64 .64 0 0 1 .6-.6 .64 .64 0 0 1 .6 .6 .64 .64 0 0 1 .7-.6 .64 .64 0 0 1 .6 .6h1.3M45.5 84.1h.5M45.5 83.6h.5M46.5 84.1h.5M46.5 83.6h.5"/>
<path d="M47.5 84.1h.5M47.5 83.6h.5M48.5 84.1h.5M48.5 83.6h.5M49.5 84.1h.5M49.5 83.6h.5M50.5 84.1h.6M50.5 83.6h.6M101.6 91.4v2.1M101.6 94.5v2M120.6 87.6h.1M120.6 85.1v2.5"/>
<path d="M120.6 85.1l-.7 1.3M120.6 85.1l.8 1.3M132.1 81.3v1.3h1.2l-1.2 1.2-1.3-1.2h1.3M132.1 81.3h.1M245.1 96.5h.8M249.4 96.5h.8M255.3 94h3.8M255.3 91.4h3.8M260.1 90.4v2.1M260.1 93v2M260.6 90.4v2.1M260.6 93v2"/>
<path d="M261.6 94h3.8M261.6 91.4h3.8M270 98.8v-.8h-.8h.8l-1.5 1.6M271.3 98.8v-.8h-.8h.8l-1.6 1.6M87.6 114.3h2.1M90.7 114.3h2M101.6 102.9v1.2h1.3l-1.3 1.3-1.3-1.3h1.3M101.6 102.9h.1M260.3 102.9v2.5M262.9 100.3h7.6M275.6 100.3v1.3h1.3l-1.3 1.3-1.3-1.3h1.3M275.6 100.3h.1"/>
<path d="M83.8 127v1.3h1.3l-1.3 1.2-1.3-1.2h1.3M83.8 127h.1M104.1 120.7v1.2h1.3l-1.3 1.3-1.2-1.3h1.2M104.1 120.7h.1M134.6 149.9v1.2h1.3l-1.3 1.3-1.3-1.3h1.3M134.6 149.9h.1"/>
<circle cx="260.4" cy="106.2" r=".76"/>
</g>
<path d="M111.1 44.6h2.5" fill="none" stroke="#006464" stroke-width=".15"/>
<path d="M154.7 24.9h3M215.6 24.9h3.1M236 24.9h3M246.1 24.9h3.1M256.3 24.9h3M266.4 24.9h3.1M220.7 40.1h3.1M37.8 94.7h3.1M100.1 93.5h3M90.7 112.8v3" fill="none" stroke="#840000" stroke-width=".3"/>
<path d="M154.7 25.9h3M215.6 25.9h3.1M236 25.9h3M246.1 25.9h3.1M256.3 25.9h3M266.4 25.9h3.1M220.7 41.1h3.1M37.8 95.8h3.1M100.1 94.5h3M89.7 112.8v3" fill="none" stroke="#840000" stroke-width=".33"/>
<path d="M94.5 31.2h1.5v3.6h-1.5zM242.1 55.1h3.5v1.5h-3.5zM242.1 62.7h3.5v1.6h-3.5zM245.9 95.8h3.5v1.5h-3.5z" fill="none" stroke="#840000" stroke-width=".2"/>
<g fill="none" stroke="#9c9b98" stroke-width=".15">
<path d="M82 33h1.8M83.8 30.5v5.1M85.1 27.9v2.6M85.1 35.6v2.5M105.4 27.9v.8M105.4 32.3v.7M149.4 134.6h1.7M151.1 132.1v5.1M152.4 129.5v2.6M152.4 137.2v2.5M110.1 143.5h4.2M110.1 146.1h4.2"/>
<path d="M110.1 148.6h4.2"/>
<circle cx="85.1" cy="35.1" r=".51"/>
<circle cx="85.1" cy="31" r=".51"/>
<circle cx="152.4" cy="132.6" r=".51"/>
<circle cx="152.4" cy="136.7" r=".51"/>
</g>
<path d="M81.2 28.7l5.3 8.6M86.5 28.7l-5.3 8.6M104.2 28l2.4 5M106.6 28l-2.4 5M148.5 130.3l5.3 8.6M153.8 130.3l-5.3 8.6M106.7 142.6l6.3 6.9M113 142.6l-6.3 6.9" fill="none" stroke="#e12e31" stroke-width=".46"/>
<g fill="#9c9b98" stroke="#9c9b98" stroke-width=".15">
<path d="M109.2 143.4h.9v.2h-.9z"/>
<path d="M109.2 145.9h.9v.3h-.9z"/>
<path d="M109.2 148.5h.9v.2h-.9z"/>
</g>
<path d="M104.6 28.7h1.6v3.6h-1.6z" fill="none" stroke="#9c9b98" stroke-width=".2"/>
<g fill="#840000" stroke="#840000" stroke-width=".15">
<path d="M259.8 93.5h1.1v1h-1.1z"/>
<path d="M260.6 93a1.02 1.02 0 0 1 1 1 1.02 1.02 0 0 1-1 1z"/>
<path d="M259.4 93.3l.3-.3h.4v2a1.02 1.02 0 0 1-.9-.6 1.02 1.02 0 0 1 .2-1.1z"/>
<path d="M259.8 90.9h1.1v1h-1.1z"/>
<path d="M260.6 90.4a1.02 1.02 0 0 1 1 1 1.02 1.02 0 0 1-1 1.1z"/>
<path d="M259.4 90.7l.3-.2 .4-.1v2.1a1.02 1.02 0 0 1-.9-.7 1.02 1.02 0 0 1 .2-1.1z"/>
</g>
<path d="M273 118.1h7.7v15.3h-7.7z" fill="#ffffc2"/>
<path d="M280.7 119.4h1.2v2.5h-1.2z" fill="#840000" stroke="#840000" stroke-width=".25"/>
<path d="M273 118.1h7.7v15.3h-7.7zM273 121.9h1.3l.7-.6 .6 .6M277.5 121.9l-.6-.6-.7 .6v5.1h-3.2M279.4 121.9l-.6-.6-.7 .6v10.2h-5.1" fill="none" stroke="#840000" stroke-width=".25"/>
<path d="M270.5 119.4h3.3v2.3l.3-.5M270.5 129.5h6.4v2.3l.2-.5M270.5 124.5h4.6v2.2l.2-.5M270.5 127h2.5M270.5 132.1h2.5M270.5 121.9h2.5M273.6 121.2l.2 .5M274.8 126.2l.3 .5M276.6 131.3l.3 .5M266.7 157.5v1.3h1.3l-1.3 1.2-1.3-1.2h1.3M266.7 157.5h.1" fill="none" stroke="#840000" stroke-width=".15"/>
<path d="M274.3 143.5h7.6v15.3h-7.6z" fill="#ffffc2"/>
<path d="M281.9 144.8h1.3v2.5h-1.3z" fill="#840000" stroke="#840000" stroke-width=".25"/>
<path d="M274.3 143.5h7.6v15.3h-7.6zM274.3 147.3h1.3l.6-.6 .7 .6M278.8 147.3l-.7-.6-.6 .6v5.1h-3.2M280.7 147.3l-.7-.6-.6 .6v10.2h-5.1" fill="none" stroke="#840000" stroke-width=".25"/>
<g fill="none" stroke="#840000" stroke-width=".15">
<path d="M184.1 154.9v1.3h1.3l-1.3 1.3-1.2-1.3h1.2M184.1 154.9h.1M196.8 154.9v1.3h1.3l-1.3 1.3-1.2-1.3h1.2M196.8 154.9h.1M271.8 154.9h6.3v2.3l.3-.5M271.8 149.9h4.6v2.2l.2-.5M271.8 144.8h3.3v2.3l.2-.5M271.8 152.4h2.5M271.8 157.5h2.5M271.8 147.3h2.5M274.8 146.6l.3 .5M276.1 151.6l.3 .5"/>
<path d="M277.9 156.7l.2 .5"/>
</g>
<path d="M167.6 55.9h58.5v96.5h-58.5z" fill="#ffffc2"/>
<path d="M167.6 55.9h58.5v96.5h-58.5z" fill="none" stroke="#840000" stroke-width=".25"/>
<g fill="none" stroke="#840000" stroke-width=".15">
<path d="M176.5 19.1h.1M176.5 16.5v2.6M176.5 16.5l-.7 1.3M176.5 16.5l.8 1.3M29.2 25.4v1.3h1.3l-1.3 1.2-1.3-1.2h1.3M29.2 25.4h.1M167.6 22.9v2M167.6 25.9v2M167.6 38.1v2M227.3 22.9v2M227.3 25.9v2M120.6 59.7v1.3h1.3l-1.3 1.2-1.2-1.2h1.2"/>
<path d="M120.6 59.7h.1M167.6 45.7v1.3h1.3l-1.3 1.3-1.2-1.3h1.2M167.6 45.7h.1M167.6 41.1v2.1M176.5 53.3v2.6M179.1 53.3v2.6M184.1 53.3v2.6M188 53.3v2.6M193 53.3v2.6M195.6 53.3v2.6M198.1 53.3v2.6M200.7 53.3v2.6"/>
<path d="M203.2 53.3v2.6M205.7 53.3v2.6M209.5 53.3v2.6M213.4 53.3v2.6M24.1 74.9h1.3a.64 .64 0 0 1 .6-.6 .64 .64 0 0 1 .7 .6 .64 .64 0 0 1 .6-.6 .64 .64 0 0 1 .6 .6 .64 .64 0 0 1 .7-.6 .64 .64 0 0 1 .6 .6 .64 .64 0 0 1 .6-.6 .64 .64 0 0 1 .7 .6h1.2M25.1 73.9h.6M25.1 73.4h.6M26.2 73.9h.5M26.2 73.4h.5M27.2 73.9h.5M27.2 73.4h.5M28.2 73.9h.5"/>
<path d="M28.2 73.4h.5M29.2 73.9h.5M29.2 73.4h.5M30.2 73.9h.5M30.2 73.4h.5M38.1 74.9h.8M42.4 74.9h.8M119.4 72.4h.7M119.4 74.9h.7M123.7 72.4h.8M123.7 74.9h.8M165.1 76.2h2.5"/>
<path d="M165.1 78.7h2.5M165.1 72.4h2.5M226.1 71.1h2.5M226.1 73.7h2.5M226.1 76.2h2.5M226.1 78.7h2.5M226.1 63.5h2.5M226.1 61h2.5M165.1 81.3h2.5M165.1 83.8h2.5M165.1 87.6h2.5M226.1 81.3h2.5"/>
<path d="M226.1 83.8h2.5M226.1 86.4h2.5M226.1 88.9h2.5M226.1 91.4h2.5M226.1 94h2.5M226.1 96.5h2.5M226.1 99.1h2.5M165.1 106.7h2.5M165.1 111.8h2.5M226.1 101.6h2.5M226.1 104.1h2.5M226.1 106.7h2.5"/>
<path d="M226.1 109.2h2.5M226.1 111.8h2.5M226.1 114.3h2.5M226.1 116.8h2.5M226.1 119.4h2.5M262.9 115.6h.1M262.9 113l-.8 1.3M262.9 113l.8 1.3M262.9 113v3.3M262.9 119.9v.8M165.1 135.9h2.5M165.1 138.4h2.5"/>
<path d="M165.1 124.5h2.5M226.1 124.5h2.5M226.1 121.9h2.5M226.1 127h2.5M226.1 129.5h2.5M226.1 132.1h2.5M226.1 134.6h2.5M226.1 139.7h2.5M262.9 138.4v3.3M262.9 138.4l-.8 1.3M262.9 138.4l.8 1.3M268 132.1v1.3h1.2l-1.2 1.2-1.3-1.2h1.3"/>
<path d="M268 132.1h.1M184.1 152.4v2.5M196.8 152.4v2.5M226.1 142.2h2.5M226.1 144.8h2.5M226.1 147.3h2.5M262.9 141h.1M262.9 145.3v.8M54.6 174v1.3h1.3l-1.3 1.2-1.3-1.2h1.3M54.6 174h.1"/>
</g>
<path d="M166.1 24.9h3.1M225.8 24.9h3.1M166.1 40.1h3.1" fill="none" stroke="#840000" stroke-width=".3"/>
<path d="M166.1 25.9h3.1M225.8 25.9h3.1M166.1 41.1h3.1" fill="none" stroke="#840000" stroke-width=".33"/>
<g fill="#9c9b98" stroke="#9c9b98" stroke-width=".15">
<path d="M61.4 64.6h.8v.3h-.8z"/>
<path d="M61.4 62.1h.8v.3h-.8z"/>
<path d="M61.4 59.6h.8v.2h-.8z"/>
</g>
<g fill="none" stroke="#9c9b98" stroke-width=".15">
<path d="M57.1 59.7h4.3M57.1 64.8h4.3M57.1 62.2h4.3M20.3 85.1h3.3l1.5 .2M20.3 87.6h4.1M27.9 80v3.8M31.5 87.6h4.1M35.6 85.1h-3.3l-1.6 .2"/>
<circle cx="24.9" cy="87.6" r=".51"/>
<circle cx="25.7" cy="85.3" r=".51"/>
<circle cx="27.9" cy="84.3" r=".51"/>
<circle cx="30.2" cy="85.3" r=".51"/>
<circle cx="31" cy="87.6" r=".51"/>
</g>
<path d="M58.4 58.7l6.4 7M64.8 58.7l-6.4 7M21.1 80.8l13.7 13.7M34.8 80.8l-13.7 13.7" fill="none" stroke="#e12e31" stroke-width=".46"/>
<path d="M38.9 74.2h3.5v1.5h-3.5zM120.1 74.2h3.6v1.5h-3.6zM120.1 71.6h3.6v1.6h-3.6zM262.1 116.3h1.6v3.6h-1.6zM262.1 141.7h1.6v3.6h-1.6z" fill="none" stroke="#840000" stroke-width=".2"/>
<path d="M27.2 92.6v-.8h1.5v.8M27.2 92.7a5.1 5.1 0 0 1-3.5-7.8 5.1 5.1 0 0 1 8.5 0 5.1 5.1 0 0 1-3.5 7.8" fill="none" stroke="#9c9b98" stroke-width=".25"/>
<path d="M52.1 96.5h7.6v14h-7.6z" fill="#ffffc2"/>
<path d="M59.7 99.1h1.3v2.5h-1.3z" fill="#840000" stroke="#840000" stroke-width=".25"/>
<path d="M52.1 96.5h7.6v14h-7.6zM52.1 101.6h1.2l.7-.6 .6 .6M56.5 101.6l-.6-.6-.7 .6v5.1h-3.1M58.4 101.6l-.6-.6-.7 .6v7.6h-5" fill="none" stroke="#840000" stroke-width=".25"/>
<g fill="none" stroke="#840000" stroke-width=".15">
<path d="M43.2 20.3h.7M47.5 20.3h.8M49.5 99.1h3.3v2.2l.3-.5M68.6 94v1.3h1.2l-1.2 1.2-1.3-1.2h1.3M68.6 94h.1M49.5 104.1h4.6v2.3l.3-.5M49.5 106.7h2.6M49.5 109.2h2.6M49.5 101.6h2.6M52.6 100.8l.2 .5M53.8 105.9l.3 .5M53.3 151.1v1.3h1.3l-1.3 1.3-1.2-1.3h1.2"/>
<path d="M53.3 151.1h.1M127 166.4h2.5M129.5 165.1h5.1M132.1 163.3v1.8M132.1 178.6v1.7M134.6 166.4h2.6M153.7 166.4h2.5M156.2 165.1h5.1M156.2 179.1h5.1M158.7 163.3v1.8M158.7 177.3v1.8M161.3 166.4h2.5"/>
<path d="M127 181.6h2.5M129.5 180.3h5.1M134.6 181.6h2.6M153.7 180.3h2.5M161.3 180.3h2.5"/>
<circle cx="130" cy="166.4" r=".51"/>
<circle cx="134.1" cy="166.4" r=".51"/>
<circle cx="156.7" cy="166.4" r=".51"/>
<circle cx="160.8" cy="166.4" r=".51"/>
<circle cx="130" cy="181.6" r=".51"/>
<circle cx="134.1" cy="181.6" r=".51"/>
<circle cx="156.7" cy="180.3" r=".51"/>
<circle cx="160.8" cy="180.3" r=".51"/>
</g>
<path d="M43.9 19.6h3.6v1.5h-3.6z" fill="none" stroke="#840000" stroke-width=".2"/>
<circle cx="148.6" cy="188" r="1.27" fill="none" stroke="#840000" stroke-width="1.3"/>
<path d="M38.1 160h10.2v10.2h-10.2z" fill="#ffffc2"/>
<g fill="none" stroke="#840000" stroke-width=".25">
<path d="M38.1 160h10.2v10.2h-10.2zM42.5 163.3v3.6M42.8 162.4a2.73 2.73 0 0 0-2.7 2.8 2.73 2.73 0 0 0 2.7 2.7M42.8 163.3v3.6M43.1 163.3v3.6M43.3 167.5l-.6 .4 .7 .2M43.4 162.2l-.7 .2 .6 .4M46.6 165.1h.4M47 164.1v2M47.5 166.1v1.5h.8M48.3 162.6h-.8v1.5"/>
<circle cx="42.8" cy="165.1" r="1.9"/>
<circle cx="47.5" cy="164.1" r=".13"/>
<circle cx="47.5" cy="166.1" r=".13"/>
</g>
<g fill="none" stroke="#840000" stroke-width=".15">
<path d="M17.8 19.1v.7M17.8 23.4v.7M37.8 26.4v.5M37.8 27.4v.5M37.8 28.4v.6M37.8 29.5v.5M37.8 30.5v.5M37.8 31.5v.5M38.4 26.4v.5M38.4 27.4v.5M38.4 28.4v.6M38.4 29.5v.5"/>
<path d="M38.4 30.5v.5M38.4 31.5v.5M39.4 25.4v1.3a.64 .64 0 0 0-.7 .6 .64 .64 0 0 0 .7 .6 .64 .64 0 0 0-.7 .7 .64 .64 0 0 0 .7 .6 .64 .64 0 0 0-.7 .6 .64 .64 0 0 0 .7 .7 .64 .64 0 0 0-.7 .6 .64 .64 0 0 0 .7 .7v1.2M103.7 72.4h4.2M103.7 74.9h4.2M103.7 77.5h4.2M103.7 80h4.2M35.6 162.6h3.8v.5M35.6 165.1h3.8v1l.5 1M39.4 167.1v.5h-3.8M39.9 163.1l-.5 1v1h-.5M48.3 162.6h2.5"/>
<path d="M48.3 167.6h2.5"/>
</g>
<g fill="#840000" stroke="#840000" stroke-width=".15">
<path d="M102.9 72.3h.8v.2h-.8z"/>
<path d="M102.9 74.8h.8v.3h-.8z"/>
<path d="M102.9 77.3h.8v.3h-.8z"/>
<path d="M102.9 79.9h.8v.2h-.8z"/>
<circle cx="39.4" cy="165.1" r=".25"/>
</g>
<path d="M17 19.8h1.5v3.6h-1.5z" fill="none" stroke="#840000" stroke-width=".2"/>
<path d="M61 72.4h15.2v15.2h-15.2z" fill="#ffffc2"/>
<g fill="none" stroke="#840000" stroke-width=".25">
<path d="M61 72.4h15.2v15.2h-15.2zM61 74.9h2.5v5.9M62.5 79.1h2l-1 1.7zM66.2 78.7h.3M66.2 80h.3M66.5 78.7l-1.5 .8M66.5 78.7l-.1 .3M67 78.4h3a1.65 1.65 0 0 1 1.7 1.6 1.65 1.65 0 0 1-1.7 1.7h-3zM67.7 78.9h1.8v2M68.6 72.4v5.9M68.7 79.1l-.2 .3h.5l-.3-.3v2.1h1.6M62.5 80.9h2"/>
<path d="M63.5 80.9v4.2h-2.5M66.5 80l-1.5 .8M66.5 80l-.1 .3M68.6 81.7v5.9M69.2 80.6h.5l-.2 .3zM72.1 80h4.2"/>
</g>
<circle cx="72.1" cy="80" r=".46" fill="#840000" stroke="#840000" stroke-width=".15"/>
<path d="M52.1 52.1v1.2h1.2l-1.2 1.3-1.3-1.3h1.3M52.1 52.1h.1M58.4 74.9h2.6M68.6 69.9v2.5M58.4 85.1h2.6M68.6 87.6v2.6M76.2 80h2.5" fill="none" stroke="#840000" stroke-width=".15"/>
<circle cx="120.6" cy="188" r="1.27" fill="none" stroke="#840000" stroke-width="1.3"/>
<path d="M54.6 35.6h7.6v13.9h-7.6z" fill="#ffffc2"/>
<path d="M62.2 38.1h1.3v2.5h-1.3z" fill="#840000" stroke="#840000" stroke-width=".25"/>
<path d="M54.6 35.6h7.6v13.9h-7.6zM54.6 40.6h1.3l.6-.6 .6 .6M59.1 40.6l-.7-.6-.6 .6v5.1h-3.2M61 40.6l-.7-.6-.6 .6v7.7h-5.1" fill="none" stroke="#840000" stroke-width=".25"/>
<g fill="none" stroke="#840000" stroke-width=".15">
<path d="M17.8 17.8h.1M17.8 15.2l-.8 1.3M17.8 15.2l.7 1.3M17.8 15.2v2.6M16.3 29v.5M16.3 30v.5M16.3 31v.5M16.3 32v.5M16.3 33v.5M16.3 34v.5M16.8 29v.5M16.8 30v.5"/>
<path d="M16.8 31v.5M16.8 32v.5M16.8 33v.5M16.8 34v.5M17.8 27.9v1.3a.64 .64 0 0 0-.7 .6 .64 .64 0 0 0 .7 .7 .64 .64 0 0 0-.7 .6 .64 .64 0 0 0 .7 .7 .64 .64 0 0 0-.7 .6 .64 .64 0 0 0 .7 .6 .64 .64 0 0 0-.7 .7 .64 .64 0 0 0 .7 .6v1.3M52.1 38.1h3.3v2.3l.2-.5M55.1 39.9l.3 .5M52.1 43.2h4.5v2.3l.3-.5M52.1 45.7h2.5M52.1 48.3h2.5M52.1 40.6h2.5M56.4 45l.2 .5"/>
<path d="M68.6 58.4h.1M68.6 55.9l-.8 1.3M68.6 55.9l.7 1.3M68.6 55.9v2.5M87.6 124.5h2.1M90.7 124.5h2M97.8 166.4h2.5M100.3 165.1h5.1M102.9 163.3v1.8M105.4 166.4h2.5M107.9 191.8v1.2h1.3l-1.3 1.3-1.2-1.3h1.2M107.9 191.8h.1"/>
<circle cx="100.8" cy="166.4" r=".51"/>
<circle cx="104.9" cy="166.4" r=".51"/>
</g>
<g fill="none" stroke="#840000" stroke-width="1.3">
<circle cx="120.6" cy="170.2" r="1.27"/>
<circle cx="148.6" cy="170.2" r="1.27"/>
<circle cx="20.3" cy="189.2" r="1.27"/>
</g>
<g fill="#9c9b98" stroke="#9c9b98" stroke-width=".15">
<path d="M57.6 123.1h.8v.2h-.8z"/>
<path d="M57.6 120.5h.8v.3h-.8z"/>
<path d="M57.6 118h.8v.2h-.8z"/>
</g>
<g fill="none" stroke="#9c9b98" stroke-width=".15">
<path d="M24.1 38.1h3.3l1.6 .3M31.7 33v3.8M39.4 38.1h-3.3l-1.6 .3M24.1 40.6h4.1M35.3 40.6h4.1M53.3 118.1h4.3M53.3 123.2h4.3M53.3 120.7h4.3"/>
<circle cx="29.5" cy="38.4" r=".51"/>
<circle cx="31.8" cy="37.3" r=".51"/>
<circle cx="34" cy="38.4" r=".51"/>
<circle cx="28.7" cy="40.6" r=".51"/>
<circle cx="34.8" cy="40.6" r=".51"/>
</g>
<path d="M24.9 33.8l13.7 13.7M38.6 33.8l-13.7 13.7M54.6 117.2l6.4 6.9M61 117.2l-6.4 6.9" fill="none" stroke="#e12e31" stroke-width=".46"/>
<path d="M90.7 122.9v3.1" fill="none" stroke="#840000" stroke-width=".3"/>
<path d="M89.7 122.9v3.1" fill="none" stroke="#840000" stroke-width=".33"/>
<path d="M31 45.6v-.8h1.5v.8M31 45.7a5.1 5.1 0 0 1-3.5-7.8 5.1 5.1 0 0 1 8.5 0 5.1 5.1 0 0 1-3.5 7.8" fill="none" stroke="#9c9b98" stroke-width=".25"/>
<path d="M38.1 137.2h10.2v10.1h-10.2z" fill="#ffffc2"/>
<g fill="none" stroke="#840000" stroke-width=".25">
<path d="M38.1 137.2h10.2v10.1h-10.2zM42.8 139.6a2.73 2.73 0 0 0-2.7 2.7 2.73 2.73 0 0 0 2.7 2.7M43.4 139.3l-.7 .3 .6 .4M48.3 139.7h-.8v1.5M42.5 140.5v3.5M42.8 140.5v3.5M43.1 140.5v3.5M43.3 144.7l-.6 .3 .7 .3M46.6 142.2h.4M47 141.2v2.1M47.5 143.3v1.5h.8"/>
<circle cx="42.8" cy="142.2" r="1.9"/>
<circle cx="47.5" cy="143.3" r=".13"/>
<circle cx="47.5" cy="141.2" r=".13"/>
</g>
<g fill="none" stroke="#840000" stroke-width=".15">
<path d="M39.4 25.4v1.3M39.4 31.8v1.2M52.1 38.1h2.5M120.6 38.1v2.5M52.1 52.1h.1M52.1 45.7h2.5M52.1 43.2h2.5M52.1 48.3h2.5M52.1 40.6h2.5M107.9 45.7h2.6M107.9 50.8h2.6M120.6 59.7h.1"/>
<path d="M120.6 55.9v2.5M130.8 45.7h2.5M130.8 50.8h2.5M130.8 43.2h2.5M130.8 53.3h2.5M176.5 53.3v2.6M179.1 53.3v2.6M184.1 53.3v2.6M188 53.3v2.6M193 53.3v2.6M195.6 53.3v2.6M198.1 53.3v2.6"/>
<path d="M200.7 53.3v2.6M203.2 53.3v2.6M205.7 53.3v2.6M209.5 53.3v2.6M213.4 53.3v2.6M54.6 76.2v2.5M58.4 74.9h2.6M68.6 69.9v2.5M119.4 72.4h.7M119.4 74.9h.7M123.7 72.4h.8M123.7 74.9h.8"/>
<path d="M165.1 76.2h2.5M165.1 78.7h2.5M165.1 72.4h2.5M226.1 71.1h2.5M226.1 73.7h2.5M226.1 76.2h2.5M226.1 78.7h2.5M226.1 63.5h2.5M226.1 61h2.5M39.4 99.1h.1M39.4 92.7v2M39.4 95.8v2"/>
<path d="M44.4 85.1h1.3M50.8 85.1h1.3M54.6 81.3v2.5M58.4 85.1h2.6M68.6 87.6v2.6M76.2 80h2.5M120.6 87.6h.1M120.6 87.6v2.6M128.3 95.3h2.5M128.3 92.7h2.5M128.3 97.8h2.5M165.1 81.3h2.5"/>
<path d="M165.1 83.8h2.5M165.1 87.6h2.5M226.1 96.5h2.5M226.1 94h2.5M226.1 91.4h2.5M226.1 81.3h2.5M226.1 83.8h2.5M226.1 86.4h2.5M226.1 88.9h2.5M226.1 99.1h2.5M245.1 96.5h.8M249.4 96.5h.8"/>
<path d="M255.3 94h3.8M255.3 91.4h3.8M261.6 94h3.8M261.6 91.4h3.8M104.1 118.1h7.7M120.6 102.9h.1M120.6 100.3v2.6M121.9 118.1h7.6M165.1 106.7h2.5M165.1 111.8h2.5M226.1 101.6h2.5M226.1 104.1h2.5"/>
<path d="M226.1 106.7h2.5M226.1 109.2h2.5M226.1 111.8h2.5M226.1 114.3h2.5M226.1 116.8h2.5M226.1 119.4h2.5M262.9 115.6h.1M262.9 115.6v.7M262.9 119.9v.8M35.6 139.7h3.8v.5M48.3 139.7h2.5M104.1 120.7h.1"/>
<path d="M104.1 120.7h7.7M121.9 120.7h7.6M165.1 135.9h2.5M165.1 138.4h2.5M165.1 124.5h2.5M226.1 139.7h2.5M226.1 124.5h2.5M226.1 121.9h2.5M226.1 127h2.5M226.1 129.5h2.5M226.1 132.1h2.5M226.1 134.6h2.5"/>
<path d="M35.6 142.2h3.8v1.1l.5 1M39.4 144.3v.5h-3.8M39.9 140.2l-.5 1v1h-.5M48.3 144.8h2.5M184.1 154.9h.1M184.1 152.4v2.5M196.8 154.9h.1M196.8 152.4v2.5M226.1 144.8h2.5M226.1 142.2h2.5M226.1 147.3h2.5M262.9 141h.1"/>
<path d="M262.9 141v.7M262.9 145.3v.8M102.9 178.6v1.7M97.8 181.6h2.5M100.3 180.3h5.1M105.4 181.6h2.5M153.7 180.3h2.5M161.3 180.3h2.5"/>
<circle cx="100.8" cy="181.6" r=".51"/>
<circle cx="104.9" cy="181.6" r=".51"/>
</g>
<circle cx="39.4" cy="142.2" r=".25" fill="#840000" stroke="#840000" stroke-width=".15"/>
<g fill="none" stroke="#840000" stroke-width="1.3">
<circle cx="97.8" cy="170.2" r="1.27"/>
<circle cx="97.8" cy="188" r="1.27"/>
</g>
<path d="M269.2 55.9l.7-.7h.6v1.3h-.6zM269.9 62.9h.6v1.2h-.6l-.7-.6zM271.1 90.8h.7v1.3h-.7l-.6-.7zM271.1 93.3h.7v1.3h-.7l-.6-.6zM244.5 106h.6v1.3h-.6l-.7-.6z" fill="none" stroke="#725600" stroke-width=".15"/>
<path d="M85.2 23.1h9.6" fill="none" stroke="#0f0f0f" stroke-width=".15"/>
<g fill="none" stroke="#009600" stroke-width=".15">
<path d="M17.8 17.8v1.3M176.5 19.1v34.2M213.4 19.1v34.2M17.8 38.1h6.3M17.8 35.6v21.6h25.4M17.8 24.1v3.8M29.2 25.4h2.5v7.6M39.4 33v5.1h12.7v2.5M43.2 20.3h-3.8v5.1M47 38.1v21.6h10.1M48.3 20.3h16.5M85.1 27.9v-2.5h10.1v5.1"/>
<path d="M85.1 38.1v3.8M95.2 35.6v3.8h10.2M105.4 33v12.7h2.5M120.6 24.1v14M127 26.7v-1.3h-21.6v2.5M127 31.8v1.2M156.2 27.9v3.9M167.6 20.3v2.6M167.6 27.9v2.6h-11.4M176.5 20.3h-20.3v2.6M176.5 35.6h-8.9v2.5M213.4 20.3h54.6v2.6"/>
<path d="M213.4 35.6h8.8v2.5M217.2 27.9v3.9h50.8v-3.9M217.2 20.3v2.6M227.3 20.3v2.6M227.3 27.9v3.9M237.5 20.3v2.6M237.5 27.9v3.9M247.6 20.3v2.6M247.6 27.9v3.9M257.8 20.3v2.6M257.8 27.9v3.9M52.1 43.2v2.5h-8.9v22.9h7.6v-3.8h6.3"/>
<path d="M52.1 48.3v3.8M68.6 58.4v11.5M92.7 50.8h15.2M120.6 58.4v1.3M133.3 45.7h16.6M133.3 50.8h16.6M133.3 53.3h16.6M133.3 43.2h16.6M167.6 43.2v2.5M176.5 40.6h7.6v12.7M179.1 40.6v12.7M193 40.6v12.7"/>
<path d="M195.6 40.6v12.7M198.1 40.6v12.7M200.7 40.6v12.7M203.2 40.6v12.7M205.7 40.6v12.7M209.5 40.6v12.7M213.4 40.6h-25.4v12.7M222.2 43.2v2.5M241.3 55.9h-6.4v5.1h-6.3M246.4 55.9h22.8M24.1 74.9h-3.8v10.2h-2.5v38.1h35.5M31.7 74.9h6.4"/>
<path d="M43.2 74.9h15.2M47 62.2h10.1M54.6 74.9v1.3M78.7 72.4v7.6M107.9 72.4h11.5M107.9 74.9h11.5M124.5 72.4h7.6v5.1h-24.2M124.5 74.9h7.6M151.1 78.7h14M151.1 76.2h14M151.1 72.4h14M228.6 63.5h12.7"/>
<path d="M228.6 78.7h16.5M228.6 71.1h16.5M228.6 76.2h16.5M228.6 73.7h16.5M246.4 63.5h22.8M27.9 80h11.5v12.7M35.6 85.1h8.8M39.4 91.4h-3.8l-3.9 7.7v21.6h21.6M39.4 97.8v1.3M43.2 85.1v33h10.1M43.2 99.1h6.3v2.5M52.1 85.1h6.3"/>
<path d="M54.6 83.8v1.3M68.6 90.2v3.8M101.6 96.5v6.4M107.9 80h24.2v1.3M120.6 87.6h-19v3.8M130.8 95.3h11.4M130.8 97.8v5.1h-10.2M130.8 92.7h11.4M151.1 83.8h14M151.1 81.3h14M151.1 87.6h14M228.6 91.4h26.7"/>
<path d="M228.6 86.4h16.5M228.6 83.8h16.5M228.6 81.3h16.5M228.6 99.1h15.2v7.6M228.6 96.5h16.5M228.6 94h26.7M228.6 88.9h16.5M250.2 96.5h10.1v6.4M265.4 91.4h5.1M265.4 94h5.1M31.7 109.2h17.8M49.5 104.1v2.6h-31.7"/>
<path d="M87.6 114.3h-3.8v12.7M92.7 114.3h54.6M104.1 114.3v3.8M129.5 118.1h2.6M151.1 111.8h14M151.1 106.7h14M228.6 111.8h15.2M228.6 114.3h15.2M228.6 119.4h15.2M228.6 116.8h15.2M260.3 100.3h2.6M270.5 100.3h5.1"/>
<path d="M24.1 139.7h11.5M50.8 139.7h10.2M83.8 124.5h3.8M92.7 124.5h41.9M129.5 120.7v3.8M139.7 124.5h7.6M152.4 139.7v6.4h-38.1M157.5 135.9h7.6M157.5 138.4h7.6M165.1 124.5h-12.7v5M228.6 132.1h15.2M228.6 121.9h15.2"/>
<path d="M228.6 124.5h15.2M228.6 134.6h15.2M254 127h16.5M262.9 120.7v1.2h7.6M270.5 124.5h-7.6v7.6h7.6M24.1 144.8h11.5M35.6 142.2h-14v7.7l1.3 1.2h30.4v-6.3h-2.5M114.3 148.6h10.2M114.3 143.5h10.2M134.6 146.1v3.8M228.6 142.2h15.2M228.6 144.8h15.2"/>
<path d="M252.7 152.4h19.1M262.9 146.1v1.2h8.9M271.8 149.9h-8.9v7.6h8.9M24.1 162.6h11.5M24.1 167.6h11.5M35.6 165.1h-14v7.6l1.3 1.3h31.7v-6.4h-3.8M50.8 162.6h11.4M87.6 166.4h10.2M107.9 166.4v25.4h55.9v-25.4M116.8 166.4h10.2M137.2 166.4v22.8l-2.6 2.6M143.5 166.4h10.2"/>
<path d="M88.9 181.6h8.9M116.8 181.6h10.2M144.8 180.3h8.9"/>
</g>
<g fill="none" stroke="#000084" stroke-width=".15">
<path d="M23.5 40l1.2 1.2M24.7 40l-1.2 1.2M38.8 40l1.2 1.2M40 40l-1.2 1.2M19.7 87l1.2 1.2M20.9 87l-1.2 1.2M35 87l1.2 1.2M36.2 87l-1.2 1.2M228 106.1l1.2 1.2M228 103.5l1.2 1.2M228 101l1.2 1.2M228 108.6l1.2 1.2"/>
<path d="M229.2 106.1l-1.2 1.2M229.2 103.5l-1.2 1.2M229.2 101l-1.2 1.2M229.2 108.6l-1.2 1.2M269.9 118.8l1.2 1.2M271.1 118.8l-1.2 1.2M228 139.1l1.2 1.2M228 128.9l1.2 1.2M228 126.4l1.2 1.2M229.2 139.1l-1.2 1.2M229.2 128.9l-1.2 1.2M229.2 126.4l-1.2 1.2"/>
<path d="M269.9 128.9l1.2 1.2M271.1 128.9l-1.2 1.2M228 146.7l1.2 1.2M229.2 146.7l-1.2 1.2M271.2 144.2l1.2 1.2M271.2 154.3l1.2 1.2M272.4 144.2l-1.2 1.2M272.4 154.3l-1.2 1.2"/>
</g>
<path d="M14 14h66v115.5h-66zM95.2 64.8h53.4v43.2h-53.4zM251.5 110.5h33v53.3h-33zM19 134.6h58.5v45.7h-58.5zM87.6 156.2h81.3v40.7h-81.3z" fill="none" stroke="#0000c2" stroke-width=".15"/>
<path d="M24.1 38.1h2.6M31.7 33v2.6M36.8 38.1h2.6M24.1 40.6h2.6M36.8 40.6h2.6M20.3 87.6h2.6M20.3 85.1h2.6M27.9 80v2.6M33 87.6h2.6M33 85.1h2.6" fill="none" stroke="#9c9b98" stroke-width=".15"/>
<path d="M24.9 33.8l13.7 13.7M38.6 33.8l-13.7 13.7M21.1 80.8l13.7 13.7M34.8 80.8l-13.7 13.7" fill="none" stroke="#e12e31" stroke-width=".46"/>
<path d="M111.1 44.6h2.5" fill="none" stroke="#006464" stroke-width=".15"/>
<g fill="#009600" stroke="#009600" stroke-width=".13">
<circle cx="163.8" cy="180.3" r=".46"/>
<circle cx="107.9" cy="181.6" r=".46"/>
<circle cx="54.6" cy="174" r=".46"/>
<circle cx="107.9" cy="191.8" r=".46"/>
<circle cx="49.5" cy="99.1" r=".46"/>
<circle cx="49.5" cy="106.7" r=".46"/>
<circle cx="53.3" cy="151.1" r=".46"/>
<circle cx="54.6" cy="85.1" r=".46"/>
<circle cx="83.8" cy="124.5" r=".46"/>
<circle cx="43.2" cy="85.1" r=".46"/>
<circle cx="39.4" cy="91.4" r=".46"/>
<circle cx="134.6" cy="191.8" r=".46"/>
<circle cx="137.2" cy="181.6" r=".46"/>
<circle cx="134.6" cy="146.1" r=".46"/>
<circle cx="129.5" cy="124.5" r=".46"/>
<circle cx="247.6" cy="31.8" r=".46"/>
<circle cx="257.8" cy="20.3" r=".46"/>
<circle cx="247.6" cy="20.3" r=".46"/>
<circle cx="257.8" cy="31.8" r=".46"/>
<circle cx="237.5" cy="31.8" r=".46"/>
<circle cx="268" cy="31.8" r=".46"/>
<circle cx="237.5" cy="20.3" r=".46"/>
<circle cx="193" cy="40.6" r=".46"/>
<circle cx="176.5" cy="35.6" r=".46"/>
<circle cx="176.5" cy="40.6" r=".46"/>
<circle cx="156.2" cy="30.5" r=".46"/>
<circle cx="167.6" cy="20.3" r=".46"/>
<circle cx="176.5" cy="20.3" r=".46"/>
<circle cx="198.1" cy="40.6" r=".46"/>
<circle cx="195.6" cy="40.6" r=".46"/>
<circle cx="227.3" cy="20.3" r=".46"/>
<circle cx="205.7" cy="40.6" r=".46"/>
<circle cx="200.7" cy="40.6" r=".46"/>
<circle cx="203.2" cy="40.6" r=".46"/>
<circle cx="209.5" cy="40.6" r=".46"/>
<circle cx="213.4" cy="40.6" r=".46"/>
<circle cx="227.3" cy="31.8" r=".46"/>
<circle cx="213.4" cy="20.3" r=".46"/>
<circle cx="217.2" cy="20.3" r=".46"/>
<circle cx="213.4" cy="35.6" r=".46"/>
<circle cx="179.1" cy="40.6" r=".46"/>
<circle cx="266.7" cy="157.5" r=".46"/>
<circle cx="268" cy="132.1" r=".46"/>
<circle cx="260.3" cy="100.3" r=".46"/>
<circle cx="105.4" cy="39.4" r=".46"/>
<circle cx="120.6" cy="25.4" r=".46"/>
<circle cx="132.1" cy="74.9" r=".46"/>
<circle cx="132.1" cy="72.4" r=".46"/>
<circle cx="17.8" cy="106.7" r=".46"/>
<circle cx="20.3" cy="85.1" r=".46"/>
<circle cx="31.7" cy="109.2" r=".46"/>
<circle cx="43.2" cy="99.1" r=".46"/>
<circle cx="43.2" cy="57.2" r=".46"/>
<circle cx="52.1" cy="45.7" r=".46"/>
<circle cx="52.1" cy="38.1" r=".46"/>
<circle cx="54.6" cy="74.9" r=".46"/>
<circle cx="120.6" cy="87.6" r=".46"/>
<circle cx="104.1" cy="114.3" r=".46"/>
<circle cx="120.6" cy="102.9" r=".46"/>
<circle cx="17.8" cy="38.1" r=".46"/>
<circle cx="47" cy="38.1" r=".46"/>
<circle cx="39.4" cy="38.1" r=".46"/>
</g>
<use href="#words"/>
</svg>
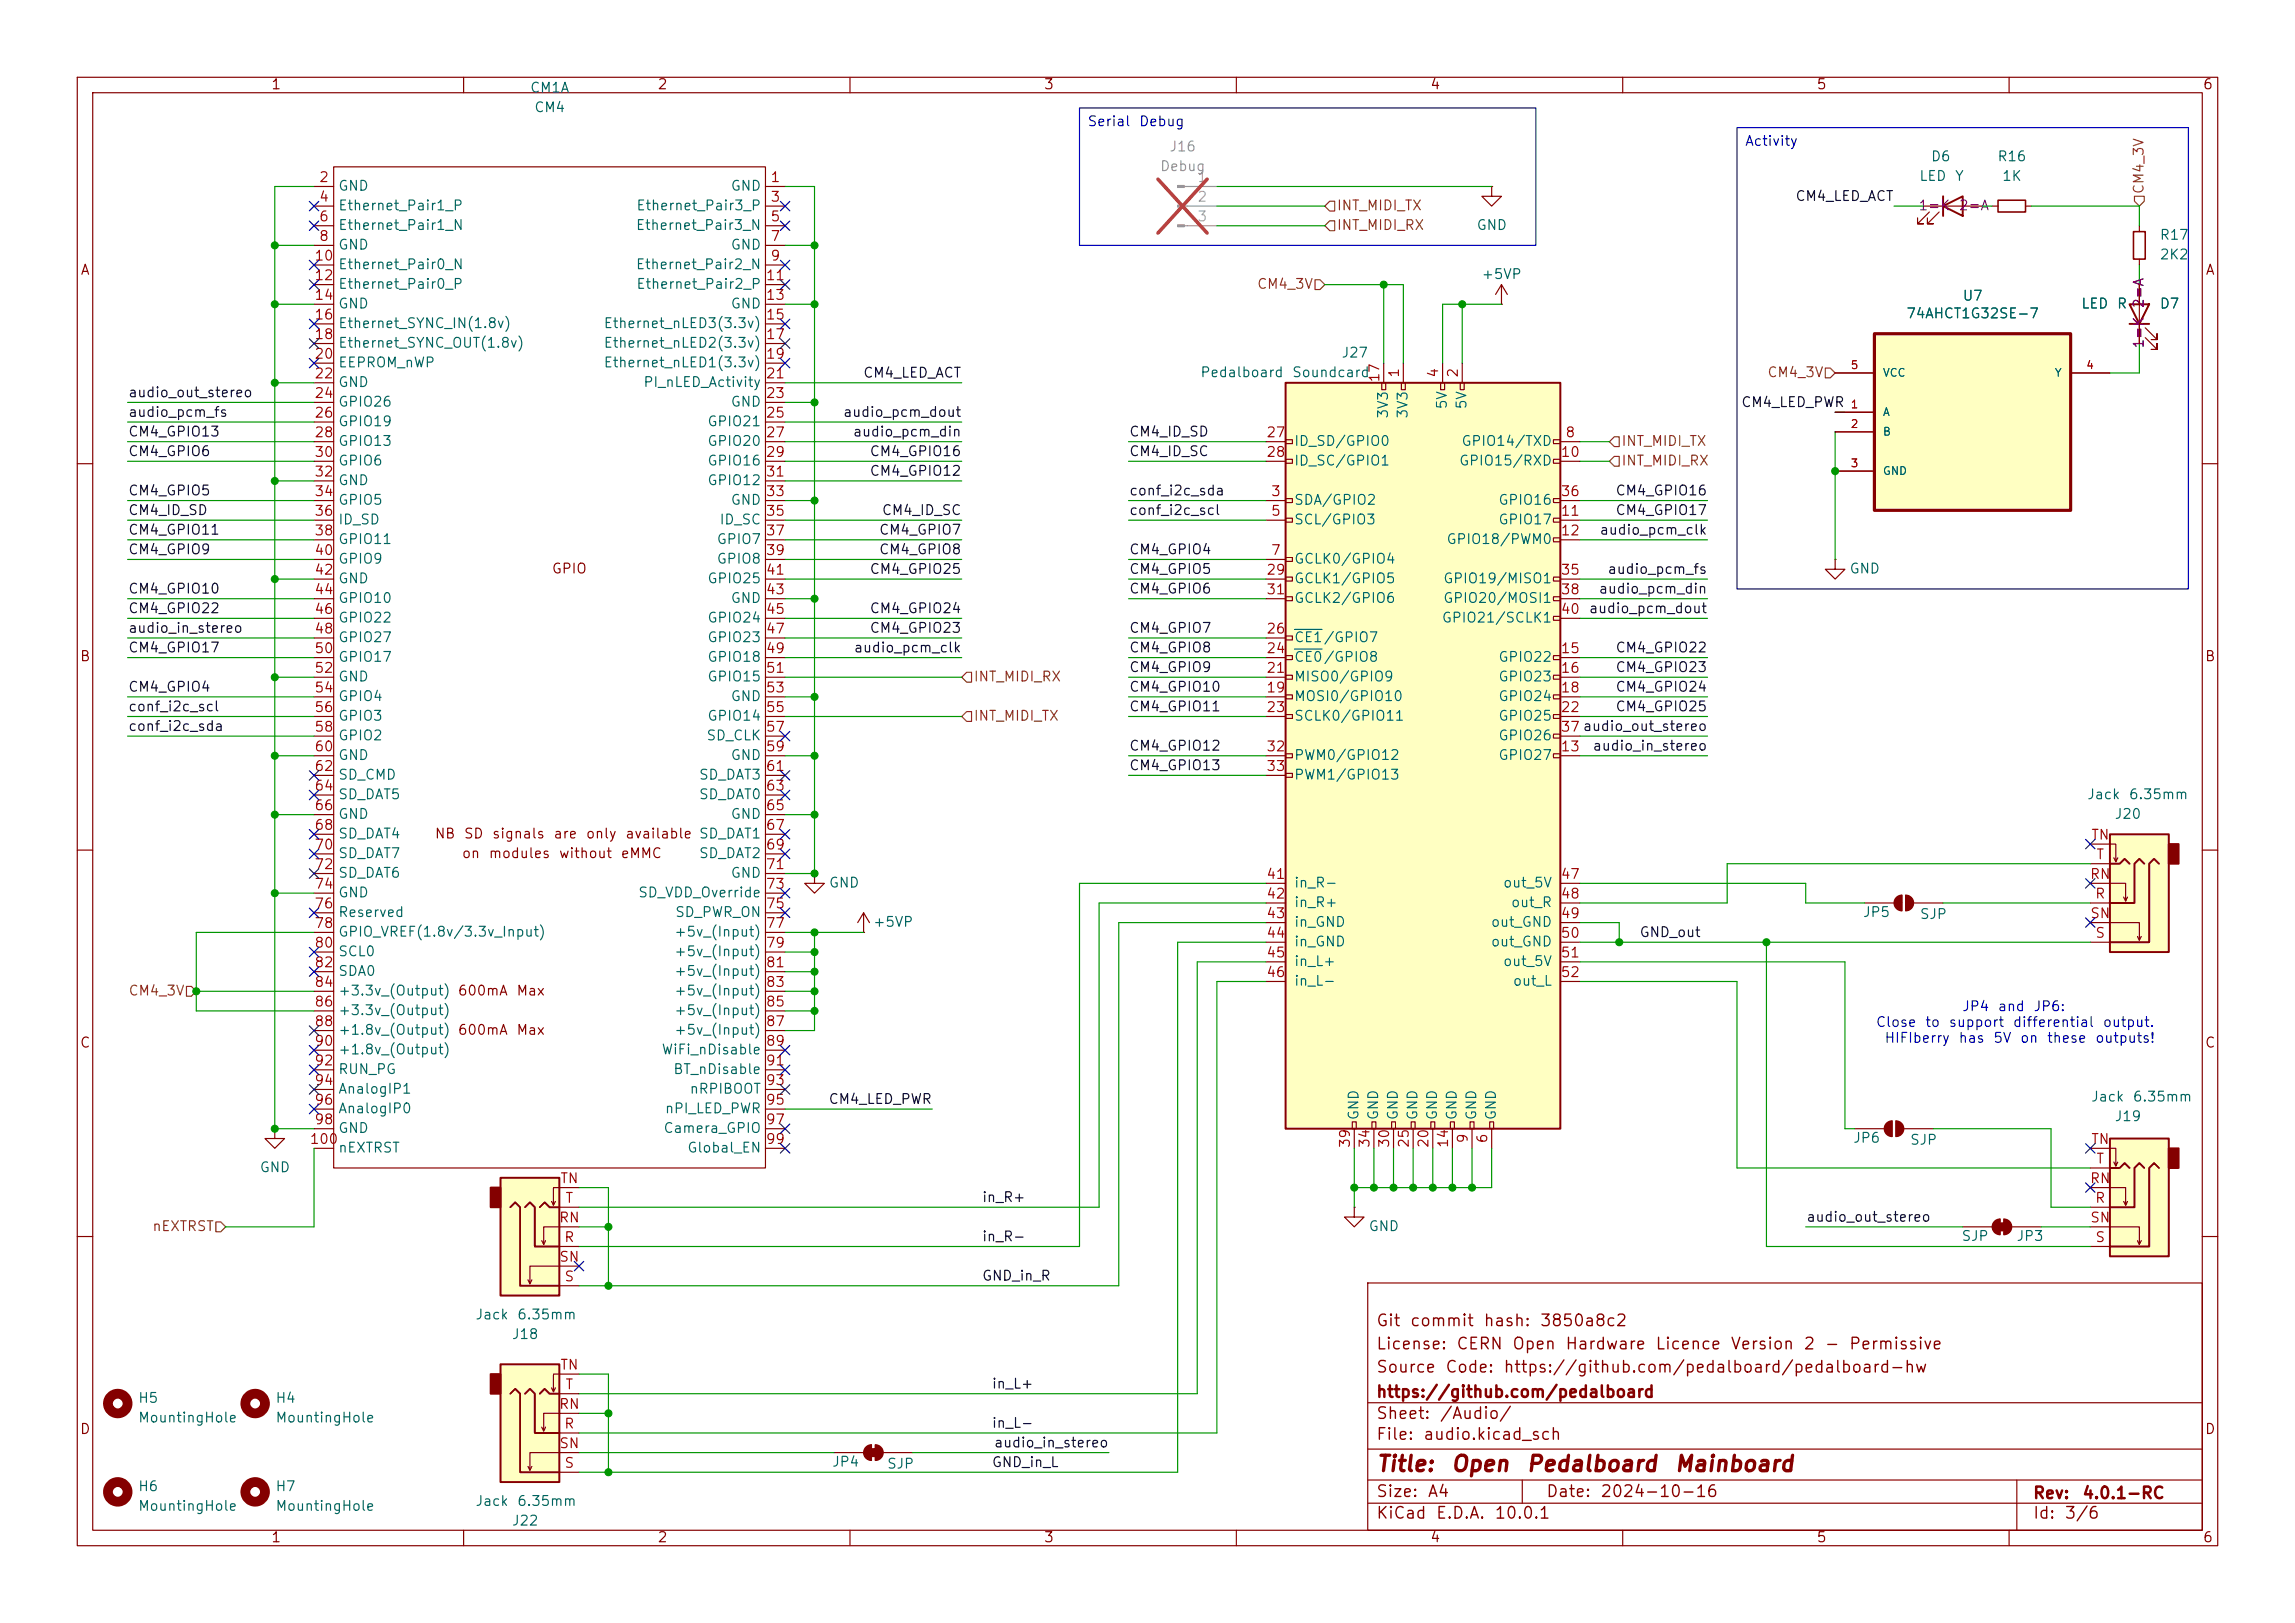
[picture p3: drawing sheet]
<svg xmlns="http://www.w3.org/2000/svg" width="297mm" height="210mm" viewBox="0 0 297 210" stroke-linecap="round" stroke-linejoin="round" font-family="sans-serif">
<defs><g id="words">
<g font-size="2" fill="#840000">
<text x="178" y="190.9">Title:</text>
<text x="187.7" y="190.9">Open</text>
<text x="197.4" y="190.9">Pedalboard</text>
<text x="216.6" y="190.9">Mainboard</text>
</g>
<g font-size="1.5" fill="#840000">
<text x="178" y="172">Git</text>
<text x="182.4" y="172">commit</text>
<text x="191.9" y="172">hash:</text>
<text x="199.2" y="172">3850a8c2</text>
<text x="178" y="178">Source</text>
<text x="178" y="175">License:</text>
<text x="186.9" y="178">Code:</text>
<text x="188.4" y="175">CERN</text>
<text x="194.5" y="178">https://github.com/pedalboard/pedalboard-hw</text>
<text x="195.6" y="175">Open</text>
<text x="202.5" y="175">Hardware</text>
<text x="214.1" y="175">Licence</text>
<text x="223.9" y="175">Version</text>
<text x="233.3" y="175">2</text>
<text x="236" y="175">-</text>
<text x="239.2" y="175">Permissive</text>
<text x="178" y="184">Sheet:</text>
<text x="178" y="181.2">https://github.com/pedalboard</text>
<text x="186.2" y="184">/Audio/</text>
<text x="178" y="186.7">File:</text>
<text x="184.1" y="186.7">audio.kicad_sch</text>
<text x="178" y="196.9">KiCad</text>
<text x="178" y="194.1">Size:</text>
<text x="184.7" y="194.1">A4</text>
<text x="185.7" y="196.9">E.D.A.</text>
<text x="193.3" y="196.9">10.0.1</text>
<text x="200" y="194.1">Date:</text>
<text x="207" y="194.1">2024-10-16</text>
<text x="263" y="194.3">Rev:</text>
<text x="263" y="196.9">Id:</text>
<text x="267.1" y="196.9">3/6</text>
<text x="269.4" y="194.3">4.0.1-RC</text>
</g>
<g font-size="1.3" fill="#840000">
<text x="35" y="11.9">1</text>
<text x="85" y="11.9">2</text>
<text x="135" y="11.9">3</text>
<text x="185" y="11.9">4</text>
<text x="235" y="11.9">5</text>
<text x="285" y="11.9">6</text>
<text x="10.3" y="35.9">A</text>
<text x="285.3" y="35.9">A</text>
<text x="71.3" y="74.5">GPIO</text>
<text x="10.3" y="85.9">B</text>
<text x="285.3" y="85.9">B</text>
<text x="56.2" y="108.8">NB</text>
<text x="59.7" y="111.4">on</text>
<text x="59.9" y="108.8">SD</text>
<text x="63.1" y="111.4">modules</text>
<text x="63.6" y="108.8">signals</text>
<text x="71.5" y="108.8">are</text>
<text x="72.2" y="111.4">without</text>
<text x="75.7" y="108.8">only</text>
<text x="80.2" y="111.4">eMMC</text>
<text x="80.8" y="108.8">available SD_DAT1</text>
<text x="66.7" y="129.1">Max</text>
<text x="10.3" y="135.9">C</text>
<text x="66.7" y="134.2">Max</text>
<text x="285.3" y="135.9">C</text>
<text x="10.3" y="185.9">D</text>
<text x="285.3" y="185.9">D</text>
<text x="35" y="199.9">1</text>
<text x="85" y="199.9">2</text>
<text x="135" y="199.9">3</text>
<text x="185" y="199.9">4</text>
<text x="235" y="199.9">5</text>
<text x="285" y="199.9">6</text>
</g>
<g font-size="1.3" fill="#006464">
<text x="68.5" y="12.3">CM1A</text>
<text x="69.1" y="14.8">CM4</text>
<text x="248.3" y="23.7">LED</text>
<text x="249.8" y="21.2">D6</text>
<text x="252.9" y="23.7">Y</text>
<text x="258.4" y="21.2">R16</text>
<text x="259" y="23.7">1K</text>
<text x="43.7" y="25">GND</text>
<text x="43.7" y="27.5">Ethernet_Pair1_P</text>
<text x="82.3" y="27.5">Ethernet_Pair3_P</text>
<text x="94.5" y="25">GND</text>
<text x="43.7" y="30.1">Ethernet_Pair1_N</text>
<text x="43.7" y="32.6">GND</text>
<text x="43.7" y="35.2">Ethernet_Pair0_N</text>
<text x="82.2" y="30.1">Ethernet_Pair3_N</text>
<text x="82.2" y="35.2">Ethernet_Pair2_N</text>
<text x="94.5" y="32.6">GND</text>
<text x="191" y="30.1">GND</text>
<text x="279.4" y="31.3">R17</text>
<text x="279.4" y="33.9">2K2</text>
<text x="43.7" y="37.7">Ethernet_Pair0_P</text>
<text x="43.7" y="40.2">GND</text>
<text x="82.3" y="37.7">Ethernet_Pair2_P</text>
<text x="94.5" y="40.2">GND</text>
<text x="191.6" y="36.4">+5VP</text>
<text x="246.6" y="41.5">74AHCT1G32SE-7</text>
<text x="253.9" y="39.2">U7</text>
<text x="269.2" y="40.2">LED</text>
<text x="273.9" y="40.2">R</text>
<text x="279.4" y="40.2">D7</text>
<text x="43.7" y="42.8">Ethernet_SYNC_IN(1.8v)</text>
<text x="43.7" y="45.3">Ethernet_SYNC_OUT(1.8v)</text>
<text x="43.7" y="47.9">EEPROM_nWP</text>
<text x="78" y="42.8">Ethernet_nLED3(3.3v)</text>
<text x="78" y="45.3">Ethernet_nLED2(3.3v)</text>
<text x="78" y="47.9">Ethernet_nLED1(3.3v)</text>
<text x="173.5" y="46.6">J27</text>
<text x="43.7" y="50.4">GND</text>
<text x="43.7" y="52.9">GPIO26</text>
<text x="83.2" y="50.4">PI_nLED_Activity</text>
<text x="94.5" y="52.9">GND</text>
<text x="155.3" y="49.1">Pedalboard</text>
<text x="167.1" y="49.1">Soundcard</text>
<text x="187.6" y="53" transform="rotate(-90 187.6 53)">5V</text>
<text x="190.1" y="53" transform="rotate(-90 190.1 53)">5V</text>
<text x="43.7" y="55.5">GPIO19</text>
<text x="43.7" y="58">GPIO13</text>
<text x="91.5" y="55.5">GPIO21</text>
<text x="91.5" y="58">GPIO20</text>
<text x="167.4" y="58">ID_SD/GPIO0</text>
<text x="179.9" y="54.3" transform="rotate(-90 179.9 54.3)">3V3</text>
<text x="182.5" y="54.3" transform="rotate(-90 182.5 54.3)">3V3</text>
<text x="189" y="58">GPIO14/TXD</text>
<text x="43.7" y="60.6">GPIO6</text>
<text x="43.7" y="63.1">GND</text>
<text x="43.7" y="65.6">GPIO5</text>
<text x="91.5" y="60.6">GPIO16</text>
<text x="91.5" y="63.1">GPIO12</text>
<text x="94.5" y="65.6">GND</text>
<text x="167.4" y="65.6">SDA/GPIO2</text>
<text x="167.4" y="60.6">ID_SC/GPIO1</text>
<text x="188.7" y="60.6">GPIO15/RXD</text>
<text x="193.8" y="65.6">GPIO16</text>
<text x="43.7" y="68.2">ID_SD</text>
<text x="43.7" y="70.7">GPIO11</text>
<text x="92.7" y="70.7">GPIO7</text>
<text x="93" y="68.2">ID_SC</text>
<text x="167.4" y="68.2">SCL/GPIO3</text>
<text x="187.1" y="70.7">GPIO18/PWM0</text>
<text x="193.8" y="68.2">GPIO17</text>
<text x="43.7" y="73.3">GPIO9</text>
<text x="43.7" y="75.8">GND</text>
<text x="91.5" y="75.8">GPIO25</text>
<text x="92.7" y="73.3">GPIO8</text>
<text x="167.4" y="73.3">GCLK0/GPIO4</text>
<text x="167.4" y="75.8">GCLK1/GPIO5</text>
<text x="186.7" y="75.8">GPIO19/MISO1</text>
<text x="239.3" y="74.5">GND</text>
<text x="43.7" y="78.3">GPIO10</text>
<text x="43.7" y="80.9">GPIO22</text>
<text x="43.7" y="83.4">GPIO27</text>
<text x="91.5" y="80.9">GPIO24</text>
<text x="91.5" y="83.4">GPIO23</text>
<text x="94.5" y="78.3">GND</text>
<text x="167.4" y="83.4">CE1/GPIO7</text>
<text x="167.4" y="78.3">GCLK2/GPIO6</text>
<text x="186.5" y="80.9">GPIO21/SCLK1</text>
<text x="186.7" y="78.3">GPIO20/MOSI1</text>
<text x="43.7" y="86">GPIO17</text>
<text x="43.7" y="88.5">GND</text>
<text x="91.5" y="86">GPIO18</text>
<text x="91.5" y="88.5">GPIO15</text>
<text x="167.4" y="88.5">MISO0/GPIO9</text>
<text x="167.4" y="86">CE0/GPIO8</text>
<text x="193.8" y="86">GPIO22</text>
<text x="193.8" y="88.5">GPIO23</text>
<text x="43.7" y="91">GPIO4</text>
<text x="43.7" y="93.6">GPIO3</text>
<text x="91.5" y="93.6">GPIO14</text>
<text x="94.5" y="91">GND</text>
<text x="167.4" y="91">MOSI0/GPIO10</text>
<text x="167.4" y="93.6">SCLK0/GPIO11</text>
<text x="193.8" y="91">GPIO24</text>
<text x="193.8" y="93.6">GPIO25</text>
<text x="43.7" y="96.1">GPIO2</text>
<text x="43.7" y="98.7">GND</text>
<text x="43.7" y="101.2">SD_CMD</text>
<text x="90.4" y="101.2">SD_DAT3</text>
<text x="91.3" y="96.1">SD_CLK</text>
<text x="94.5" y="98.7">GND</text>
<text x="167.4" y="98.7">PWM0/GPIO12</text>
<text x="167.4" y="101.2">PWM1/GPIO13</text>
<text x="193.8" y="98.7">GPIO27</text>
<text x="193.8" y="96.1">GPIO26</text>
<text x="43.7" y="103.7">SD_DAT5</text>
<text x="43.7" y="106.3">GND</text>
<text x="90.4" y="103.7">SD_DAT0</text>
<text x="94.5" y="106.3">GND</text>
<text x="270" y="103.7">Jack</text>
<text x="273.6" y="106.3">J20</text>
<text x="275.4" y="103.7">6.35mm</text>
<text x="43.7" y="108.8">SD_DAT4</text>
<text x="43.7" y="111.4">SD_DAT7</text>
<text x="43.7" y="113.9">SD_DAT6</text>
<text x="90.4" y="111.4">SD_DAT2</text>
<text x="94.5" y="113.9">GND</text>
<text x="43.7" y="116.4">GND</text>
<text x="43.7" y="119">Reserved</text>
<text x="82.5" y="116.4">SD_VDD_Override</text>
<text x="87.3" y="119">SD_PWR_ON</text>
<text x="107.2" y="115.2">GND</text>
<text x="167.4" y="115.2">in_R-</text>
<text x="167.4" y="117.7">in_R+</text>
<text x="194.4" y="115.2">out_5V</text>
<text x="195.4" y="117.7">out_R</text>
<text x="241" y="119">JP5</text>
<text x="248.4" y="119.2">SJP</text>
<text x="43.7" y="121.5">GPIO_VREF(1.8v/3.3v_Input)</text>
<text x="43.7" y="124.1">SCL0</text>
<text x="87.2" y="121.5">+5v_(Input)</text>
<text x="87.2" y="124.1">+5v_(Input)</text>
<text x="112.9" y="120.2">+5VP</text>
<text x="167.4" y="120.2">in_GND</text>
<text x="167.4" y="122.8">in_GND</text>
<text x="167.4" y="125.3">in_L+</text>
<text x="192.8" y="120.2">out_GND</text>
<text x="192.8" y="122.8">out_GND</text>
<text x="194.4" y="125.3">out_5V</text>
<text x="43.7" y="126.6">SDA0</text>
<text x="43.7" y="129.1">+3.3v_(Output) 600mA</text>
<text x="43.7" y="131.7">+3.3v_(Output)</text>
<text x="87.2" y="126.6">+5v_(Input)</text>
<text x="87.2" y="129.1">+5v_(Input)</text>
<text x="87.2" y="131.7">+5v_(Input)</text>
<text x="167.4" y="127.9">in_L-</text>
<text x="195.7" y="127.9">out_L</text>
<text x="43.7" y="134.2">+1.8v_(Output) 600mA</text>
<text x="43.7" y="136.8">+1.8v_(Output)</text>
<text x="85.5" y="136.8">WiFi_nDisable</text>
<text x="87.2" y="134.2">+5v_(Input)</text>
<text x="43.7" y="139.3">RUN_PG</text>
<text x="43.7" y="141.8">AnalogIP1</text>
<text x="87" y="139.3">BT_nDisable</text>
<text x="89.2" y="141.8">nRPIBOOT</text>
<text x="270.5" y="142.8">Jack</text>
<text x="275.9" y="142.8">6.35mm</text>
<text x="43.7" y="144.4">AnalogIP0</text>
<text x="43.7" y="146.9">GND</text>
<text x="43.7" y="149.5">nEXTRST</text>
<text x="85.8" y="146.9">Camera_GPIO</text>
<text x="86" y="144.4">nPI_LED_PWR</text>
<text x="88.9" y="149.5">Global_EN</text>
<text x="176.1" y="145" transform="rotate(-90 176.1 145)">GND</text>
<text x="178.7" y="145" transform="rotate(-90 178.7 145)">GND</text>
<text x="181.2" y="145" transform="rotate(-90 181.2 145)">GND</text>
<text x="183.7" y="145" transform="rotate(-90 183.7 145)">GND</text>
<text x="186.3" y="145" transform="rotate(-90 186.3 145)">GND</text>
<text x="188.8" y="145" transform="rotate(-90 188.8 145)">GND</text>
<text x="191.4" y="145" transform="rotate(-90 191.4 145)">GND</text>
<text x="193.9" y="145" transform="rotate(-90 193.9 145)">GND</text>
<text x="239.7" y="148.2">JP6</text>
<text x="247.1" y="148.4">SJP</text>
<text x="273.6" y="145.4">J19</text>
<text x="33.5" y="152">GND</text>
<text x="177" y="159.6">GND</text>
<text x="253.8" y="160.9">SJP</text>
<text x="260.9" y="160.9">JP3</text>
<text x="61.4" y="171">Jack</text>
<text x="66.2" y="173.6">J18</text>
<text x="66.8" y="171">6.35mm</text>
<text x="17.8" y="181.8">H5</text>
<text x="17.8" y="184.4">MountingHole</text>
<text x="35.6" y="181.8">H4</text>
<text x="35.6" y="184.4">MountingHole</text>
<text x="107.6" y="190.1">JP4</text>
<text x="114.7" y="190.3">SJP</text>
<text x="17.8" y="193.3">H6</text>
<text x="17.8" y="195.8">MountingHole</text>
<text x="35.6" y="193.3">H7</text>
<text x="35.6" y="195.8">MountingHole</text>
<text x="61.4" y="195.2">Jack</text>
<text x="66.2" y="197.7">J22</text>
<text x="66.8" y="195.2">6.35mm</text>
</g>
<g font-size="1.3" fill="#0000c2">
<text x="140.7" y="16.6">Serial</text>
<text x="147.3" y="16.6">Debug</text>
<text x="225.7" y="19.2">Activity</text>
<text x="253.8" y="131.2">JP4</text>
<text x="258.4" y="131.2">and</text>
<text x="263.1" y="131.2">JP6:</text>
<text x="242.7" y="133.2">Close</text>
<text x="243.8" y="135.2">HIFIberry</text>
<text x="249" y="133.2">to</text>
<text x="252.1" y="133.2">support</text>
<text x="253.4" y="135.2">has</text>
<text x="257.9" y="135.2">5V</text>
<text x="260.4" y="133.2">differential</text>
<text x="261.3" y="135.2">on</text>
<text x="264.8" y="135.2">these</text>
<text x="271.1" y="135.2">outputs!</text>
<text x="272" y="133.2">output.</text>
</g>
<g font-size="1.3" fill="#a90000">
<text x="41.2" y="23.9">2</text>
<text x="99.6" y="23.9">1</text>
<text x="41.2" y="26.4">4</text>
<text x="41.2" y="29">6</text>
<text x="99.6" y="26.4">3</text>
<text x="99.6" y="29">5</text>
<text x="40.6" y="34">10</text>
<text x="41.2" y="31.5">8</text>
<text x="99.6" y="31.5">7</text>
<text x="99.6" y="34">9</text>
<text x="40.6" y="36.6">12</text>
<text x="40.6" y="39.1">14</text>
<text x="40.6" y="41.7">16</text>
<text x="99" y="36.6">11</text>
<text x="99" y="39.1">13</text>
<text x="99" y="41.7">15</text>
<text x="40.6" y="44.2">18</text>
<text x="40.6" y="46.7">20</text>
<text x="99" y="44.2">17</text>
<text x="99" y="46.7">19</text>
<text x="40.6" y="49.3">22</text>
<text x="40.6" y="51.8">24</text>
<text x="99" y="49.3">21</text>
<text x="99" y="51.8">23</text>
<text x="178.8" y="49.6" transform="rotate(-90 178.8 49.6)">17</text>
<text x="181.4" y="49" transform="rotate(-90 181.4 49)">1</text>
<text x="186.4" y="49" transform="rotate(-90 186.4 49)">4</text>
<text x="189" y="49" transform="rotate(-90 189 49)">2</text>
<text x="40.6" y="54.4">26</text>
<text x="40.6" y="56.9">28</text>
<text x="40.6" y="59.4">30</text>
<text x="99" y="54.4">25</text>
<text x="99" y="56.9">27</text>
<text x="99" y="59.4">29</text>
<text x="163.8" y="56.9">27</text>
<text x="163.8" y="59.4">28</text>
<text x="201.9" y="59.4">10</text>
<text x="202.5" y="56.9">8</text>
<text x="40.6" y="62">32</text>
<text x="40.6" y="64.5">34</text>
<text x="99" y="62">31</text>
<text x="99" y="64.5">33</text>
<text x="164.4" y="64.5">3</text>
<text x="201.9" y="64.5">36</text>
<text x="40.6" y="67.1">36</text>
<text x="40.6" y="69.6">38</text>
<text x="99" y="67.1">35</text>
<text x="99" y="69.6">37</text>
<text x="164.4" y="67.1">5</text>
<text x="201.9" y="67.1">11</text>
<text x="201.9" y="69.6">12</text>
<text x="40.6" y="72.1">40</text>
<text x="40.6" y="74.7">42</text>
<text x="40.6" y="77.2">44</text>
<text x="99" y="72.1">39</text>
<text x="99" y="74.7">41</text>
<text x="99" y="77.2">43</text>
<text x="163.8" y="74.7">29</text>
<text x="163.8" y="77.2">31</text>
<text x="164.4" y="72.1">7</text>
<text x="201.9" y="74.7">35</text>
<text x="201.9" y="77.2">38</text>
<text x="40.6" y="79.8">46</text>
<text x="40.6" y="82.3">48</text>
<text x="99" y="79.8">45</text>
<text x="99" y="82.3">47</text>
<text x="163.8" y="82.3">26</text>
<text x="201.9" y="79.8">40</text>
<text x="40.6" y="84.8">50</text>
<text x="40.6" y="87.4">52</text>
<text x="40.6" y="89.9">54</text>
<text x="99" y="84.8">49</text>
<text x="99" y="87.4">51</text>
<text x="99" y="89.9">53</text>
<text x="163.8" y="89.9">19</text>
<text x="163.8" y="87.4">21</text>
<text x="163.8" y="84.8">24</text>
<text x="201.9" y="84.8">15</text>
<text x="201.9" y="87.4">16</text>
<text x="201.9" y="89.9">18</text>
<text x="40.6" y="92.5">56</text>
<text x="40.6" y="95">58</text>
<text x="99" y="92.5">55</text>
<text x="99" y="95">57</text>
<text x="163.8" y="92.5">23</text>
<text x="201.9" y="92.5">22</text>
<text x="201.9" y="95">37 audio_out_stereo</text>
<text x="40.6" y="97.5">60</text>
<text x="40.6" y="100.1">62</text>
<text x="99" y="97.5">59</text>
<text x="99" y="100.1">61</text>
<text x="163.8" y="97.5">32</text>
<text x="163.8" y="100.1">33</text>
<text x="201.9" y="97.5">13</text>
<text x="40.6" y="102.6">64</text>
<text x="40.6" y="105.2">66</text>
<text x="40.6" y="107.7">68</text>
<text x="99" y="102.6">63</text>
<text x="99" y="105.2">65</text>
<text x="99" y="107.7">67</text>
<text x="40.6" y="110.2">70</text>
<text x="40.6" y="112.8">72</text>
<text x="99" y="110.2">69</text>
<text x="99" y="112.8">71</text>
<text x="270.5" y="109">TN</text>
<text x="271.2" y="111.5">T</text>
<text x="40.6" y="115.3">74</text>
<text x="40.6" y="117.9">76</text>
<text x="99" y="115.3">73</text>
<text x="99" y="117.9">75</text>
<text x="163.8" y="114">41</text>
<text x="163.8" y="116.6">42</text>
<text x="163.8" y="119.1">43</text>
<text x="201.9" y="114">47</text>
<text x="201.9" y="116.6">48</text>
<text x="201.9" y="119.1">49</text>
<text x="270.4" y="114">RN</text>
<text x="270.4" y="119.1">SN</text>
<text x="271" y="116.6">R</text>
<text x="40.6" y="120.4">78</text>
<text x="40.6" y="122.9">80</text>
<text x="40.6" y="125.5">82</text>
<text x="99" y="120.4">77</text>
<text x="99" y="122.9">79</text>
<text x="99" y="125.5">81</text>
<text x="163.8" y="121.7">44</text>
<text x="163.8" y="124.2">45</text>
<text x="201.9" y="121.7">50</text>
<text x="201.9" y="124.2">51</text>
<text x="271.1" y="121.7">S</text>
<text x="40.6" y="128">84</text>
<text x="40.6" y="130.6">86</text>
<text x="99" y="128">83</text>
<text x="99" y="130.6">85</text>
<text x="163.8" y="126.7">46</text>
<text x="201.9" y="126.7">52</text>
<text x="40.6" y="133.1">88</text>
<text x="40.6" y="135.6">90</text>
<text x="99" y="133.1">87</text>
<text x="99" y="135.6">89</text>
<text x="40.6" y="138.2">92</text>
<text x="40.6" y="140.7">94</text>
<text x="40.6" y="143.3">96</text>
<text x="99" y="138.2">91</text>
<text x="99" y="140.7">93</text>
<text x="99" y="143.3">95</text>
<text x="40" y="148.3">100</text>
<text x="40.6" y="145.8">98</text>
<text x="99" y="145.8">97</text>
<text x="99" y="148.3">99</text>
<text x="175" y="148.6" transform="rotate(-90 175 148.6)">39</text>
<text x="177.5" y="148.6" transform="rotate(-90 177.5 148.6)">34</text>
<text x="180.1" y="148.6" transform="rotate(-90 180.1 148.6)">30</text>
<text x="182.6" y="148.6" transform="rotate(-90 182.6 148.6)">25</text>
<text x="185.2" y="148.6" transform="rotate(-90 185.2 148.6)">20</text>
<text x="187.7" y="148.6" transform="rotate(-90 187.7 148.6)">14</text>
<text x="190.2" y="148" transform="rotate(-90 190.2 148)">9</text>
<text x="192.8" y="148" transform="rotate(-90 192.8 148)">6</text>
<text x="270.5" y="148.3">TN</text>
<text x="72.4" y="153.4">TN</text>
<text x="73.1" y="156">T</text>
<text x="270.4" y="153.4">RN</text>
<text x="271" y="156">R</text>
<text x="271.2" y="150.9">T</text>
<text x="72.3" y="158.5">RN</text>
<text x="72.9" y="161">R</text>
<text x="270.4" y="158.5">SN</text>
<text x="271.1" y="161">S</text>
<text x="72.3" y="163.6">SN</text>
<text x="73" y="166.1">S</text>
<text x="72.4" y="177.5">TN</text>
<text x="72.3" y="182.6">RN</text>
<text x="72.9" y="185.2">R</text>
<text x="73.1" y="180.1">T</text>
<text x="72.3" y="187.7">SN</text>
<text x="73" y="190.2">S</text>
</g>
<g font-size="1.3" fill="#939391">
<text x="150" y="22.5">Debug</text>
<text x="151.2" y="19.9">J16</text>
</g>
<g font-size="1.3" fill="#a5a4a2">
<text x="154.9" y="23.9">1</text>
<text x="154.9" y="26.4">2</text>
<text x="154.9" y="29">3</text>
</g>
<g font-size="1.3" fill="#725600">
<text x="172.9" y="27.5">INT_MIDI_TX</text>
<text x="277.7" y="25.2" transform="rotate(-90 277.7 25.2)">CM4_3V</text>
<text x="172.9" y="30.1">INT_MIDI_RX</text>
<text x="162.6" y="37.7">CM4_3V</text>
<text x="228.6" y="49.1">CM4_3V</text>
<text x="209.7" y="58">INT_MIDI_TX</text>
<text x="209.7" y="60.6">INT_MIDI_RX</text>
<text x="125.9" y="88.5">INT_MIDI_RX</text>
<text x="125.9" y="93.6">INT_MIDI_TX</text>
<text x="16.5" y="129.1">CM4_3V</text>
<text x="19.6" y="159.6">nEXTRST</text>
</g>
<g font-size="1.3" fill="#0f0f0f">
<text x="232.3" y="26.3">CM4_LED_ACT</text>
<text x="16.5" y="51.7">audio_out_stereo</text>
<text x="111.6" y="49.2">CM4_LED_ACT</text>
<text x="225.3" y="53">CM4_LED_PWR</text>
<text x="16.5" y="56.8">CM4_GPIO13</text>
<text x="16.5" y="59.3">CM4_GPIO6</text>
<text x="16.5" y="54.3">audio_pcm_fs</text>
<text x="109" y="54.3">audio_pcm_dout</text>
<text x="110.3" y="56.8">audio_pcm_din</text>
<text x="112.5" y="59.3">CM4_GPIO16</text>
<text x="146" y="56.8">CM4_ID_SD</text>
<text x="146" y="59.3">CM4_ID_SC</text>
<text x="16.5" y="64.4">CM4_GPIO5</text>
<text x="112.5" y="61.9">CM4_GPIO12</text>
<text x="146" y="64.4">conf_i2c_sda</text>
<text x="209" y="64.4">CM4_GPIO16</text>
<text x="16.5" y="67">CM4_ID_SD</text>
<text x="16.5" y="69.5">CM4_GPIO11</text>
<text x="113.7" y="69.5">CM4_GPIO7</text>
<text x="114" y="67">CM4_ID_SC</text>
<text x="146" y="67">conf_i2c_scl</text>
<text x="206.9" y="69.5">audio_pcm_clk</text>
<text x="209" y="67">CM4_GPIO17</text>
<text x="16.5" y="72">CM4_GPIO9</text>
<text x="16.5" y="77.1">CM4_GPIO10</text>
<text x="112.5" y="74.6">CM4_GPIO25</text>
<text x="113.7" y="72">CM4_GPIO8</text>
<text x="146" y="72">CM4_GPIO4</text>
<text x="146" y="74.6">CM4_GPIO5</text>
<text x="146" y="77.1">CM4_GPIO6</text>
<text x="206.8" y="77.1">audio_pcm_din</text>
<text x="208" y="74.6">audio_pcm_fs</text>
<text x="16.5" y="82.2">audio_in_stereo</text>
<text x="16.5" y="79.7">CM4_GPIO22</text>
<text x="112.5" y="79.7">CM4_GPIO24</text>
<text x="112.5" y="82.2">CM4_GPIO23</text>
<text x="146" y="82.2">CM4_GPIO7</text>
<text x="205.5" y="79.7">audio_pcm_dout</text>
<text x="16.5" y="89.8">CM4_GPIO4</text>
<text x="16.5" y="84.7">CM4_GPIO17</text>
<text x="110.4" y="84.7">audio_pcm_clk</text>
<text x="146" y="87.3">CM4_GPIO9</text>
<text x="146" y="89.8">CM4_GPIO10</text>
<text x="146" y="84.7">CM4_GPIO8</text>
<text x="209" y="84.7">CM4_GPIO22</text>
<text x="209" y="89.8">CM4_GPIO24</text>
<text x="209" y="87.3">CM4_GPIO23</text>
<text x="16.5" y="92.4">conf_i2c_scl</text>
<text x="16.5" y="94.9">conf_i2c_sda</text>
<text x="146" y="92.4">CM4_GPIO11</text>
<text x="209" y="92.4">CM4_GPIO25</text>
<text x="146" y="97.4">CM4_GPIO12</text>
<text x="146" y="100">CM4_GPIO13</text>
<text x="206" y="97.4">audio_in_stereo</text>
<text x="212.1" y="121.6">GND_out</text>
<text x="107.1" y="143.2">CM4_LED_PWR</text>
<text x="127" y="155.9">in_R+</text>
<text x="127" y="160.9">in_R-</text>
<text x="233.7" y="158.4">audio_out_stereo</text>
<text x="127" y="166">GND_in_R</text>
<text x="128.3" y="180">in_L+</text>
<text x="128.3" y="185.1">in_L-</text>
<text x="128.3" y="190.2">GND_in_L</text>
<text x="128.6" y="187.6">audio_in_stereo</text>
</g>
<g font-size="1.3" fill="#840084">
<text x="248.2" y="27.5">1=K</text>
<text x="253.4" y="27.5">2=A</text>
<text x="277.7" y="40" transform="rotate(-90 277.7 40)">2=A</text>
<text x="277.7" y="45.2" transform="rotate(-90 277.7 45.2)">1=K</text>
</g>
<g font-size="1" fill="#a90000">
<text x="239.4" y="53.1">1</text>
<text x="239.4" y="48">5</text>
<text x="269.9" y="48">4</text>
<text x="239.4" y="55.6">2</text>
<text x="239.4" y="60.7">3</text>
</g>
<g font-size="1" fill="#006464">
<text x="243.6" y="49">VCC</text>
<text x="265.8" y="49">Y</text>
<text x="243.6" y="54.1">A</text>
<text x="243.6" y="56.6">B</text>
<text x="243.6" y="61.7">GND</text>
</g>
</g></defs>
<g fill="none" stroke="#840000" stroke-width=".15">
<path d="M10 10h277v190h-277zM12 12h273v186h-273zM60 10v2M110 10v2M160 10v2M210 10v2M260 10v2M10 60h2M285 60h2M10 110h2M285 110h2M10 160h2"/>
<path d="M177 166h108v32h-108zM285 160h2M60 198v2M110 198v2M160 198v2M177 194.5h108M177 191.5h108M177 187.5h108M177 181.5h108M197 191.5v3M210 198v2M260 198v2"/>
<path d="M261 191.5v6.5"/>
</g>
<path d="M273 147.3h7.7v15.3h-7.7z" fill="#ffffc2"/>
<path d="M280.7 148.6h1.2v2.5h-1.2z" fill="#840000" stroke="#840000" stroke-width=".25"/>
<path d="M273 147.3h7.7v15.3h-7.7zM273 151.1h1.3l.7-.6 .6 .6M277.5 151.1l-.6-.6-.7 .6v5.1h-3.2M279.4 151.1l-.6-.6-.7 .6v10.2h-5.1" fill="none" stroke="#840000" stroke-width=".25"/>
<path d="M175.3 156.2v1.3h1.2l-1.2 1.3-1.3-1.3h1.3M175.3 156.2h.1M270.5 158.8h6.4v2.2l.2-.5M270.5 153.7h4.6v2.3l.2-.6M270.5 148.6h3.3v2.3l.3-.5M270.5 156.2h2.5M270.5 151.1h2.5M273.6 150.4l.2 .5M274.8 155.4l.3 .6M270.5 161.3h2.5M276.6 160.5l.3 .5" fill="none" stroke="#840000" stroke-width=".15"/>
<path d="M273 108h7.7v15.2h-7.7z" fill="#ffffc2"/>
<path d="M280.7 109.2h1.2v2.6h-1.2z" fill="#840000" stroke="#840000" stroke-width=".25"/>
<path d="M273 108h7.7v15.2h-7.7zM273 111.8h1.3l.7-.7 .6 .7M277.5 111.8l-.6-.7-.7 .7v5h-3.2M279.4 111.8l-.6-.7-.7 .7v10.1h-5.1" fill="none" stroke="#840000" stroke-width=".25"/>
<path d="M270.5 119.4h6.4v2.3l.2-.5M270.5 114.3h4.6v2.3l.2-.5M270.5 109.2h3.3v2.3l.3-.5M270.5 116.8h2.5M270.5 111.8h2.5M273.6 111l.2 .5M274.8 116.1l.3 .5M270.5 121.9h2.5M276.6 121.2l.3 .5M35.6 146.1v1.2h1.2l-1.2 1.3-1.3-1.3h1.3M35.6 146.1h.1" fill="none" stroke="#840000" stroke-width=".15"/>
<circle cx="15.2" cy="193" r="1.27" fill="none" stroke="#840000" stroke-width="1.3"/>
<path d="M242.6 43.2h25.4v22.8h-25.4z" fill="#ffffc2"/>
<path d="M242.6 43.2h25.4v22.8h-25.4z" fill="none" stroke="#840000" stroke-width=".41"/>
<g fill="none" stroke="#840000" stroke-width=".15">
<path d="M40.6 26.7h2.6M40.6 24.1h2.6M40.6 29.2h2.6M40.6 31.8h2.6M40.6 34.3h2.6M40.6 36.8h2.6M40.6 39.4h2.6M43.2 21.6h55.9v129.5h-55.9zM99.1 26.7h2.5M99.1 24.1h2.5M99.1 29.2h2.5M99.1 31.8h2.5"/>
<path d="M99.1 34.3h2.5M99.1 36.8h2.5M99.1 39.4h2.5M193 24.1v1.3h1.3l-1.3 1.3-1.2-1.3h1.2M193 24.1h.1M248.9 26.7h7.6M249.7 27.4l-1.5 1.6h.7h-.7v-.8M251 27.4l-1.6 1.6h.8h-.8v-.8M257.8 26.7h.8M262.1 26.7h.8M276.9 29.2v.8M276.9 33.5v.8"/>
<path d="M276.9 36.8v7.7M40.6 41.9h2.6M40.6 44.5h2.6M40.6 47h2.6M40.6 49.5h2.6M40.6 52.1h2.6M40.6 54.6h2.6M40.6 57.2h2.6M40.6 59.7h2.6M99.1 41.9h2.5M99.1 44.5h2.5M99.1 47h2.5"/>
<path d="M99.1 49.5h2.5M99.1 52.1h2.5M99.1 54.6h2.5M99.1 57.2h2.5M99.1 59.7h2.5M237.5 53.3h5.1M237.5 55.9h5.1M237.5 48.3h5.1M268 48.3h5M277.6 43.7l1.5 1.5v-.7v.7h-.7M277.6 42.4l1.5 1.5v-.7v.7h-.7M40.6 62.2h2.6"/>
<path d="M40.6 64.8h2.6M40.6 67.3h2.6M40.6 69.9h2.6M40.6 72.4h2.6M40.6 74.9h2.6M40.6 77.5h2.6M99.1 62.2h2.5M99.1 64.8h2.5M99.1 67.3h2.5M99.1 69.9h2.5M99.1 72.4h2.5M99.1 74.9h2.5"/>
<path d="M99.1 77.5h2.5M237.5 72.4v1.3h-1.3l1.3 1.2 1.3-1.2h-1.3M237.5 72.4h.1M237.5 61h5.1M40.6 80h2.6M40.6 82.6h2.6M40.6 85.1h2.6M40.6 87.6h2.6M40.6 90.2h2.6M40.6 92.7h2.6M40.6 95.3h2.6M40.6 97.8h2.6"/>
<path d="M99.1 80h2.5M99.1 82.6h2.5M99.1 85.1h2.5M99.1 87.6h2.5M99.1 90.2h2.5M99.1 92.7h2.5M99.1 95.3h2.5M99.1 97.8h2.5M40.6 100.3h2.6M40.6 102.9h2.6M40.6 105.4h2.6M40.6 108h2.6"/>
<path d="M40.6 110.5h2.6M40.6 113h2.6M40.6 115.6h2.6M40.6 118.1h2.6M99.1 100.3h2.5M99.1 102.9h2.5M99.1 105.4h2.5M99.1 108h2.5M99.1 110.5h2.5M99.1 113h2.5M99.1 115.6h2.5M99.1 118.1h2.5"/>
<path d="M241.3 116.8h3.8M246.1 115.8v2.1M246.6 115.8v2.1M247.6 116.8h3.9M40.6 120.7h2.6M40.6 123.2h2.6M40.6 125.7h2.6M40.6 128.3h2.6M40.6 130.8h2.6M40.6 133.4h2.6M40.6 135.9h2.6M40.6 138.4h2.6"/>
<path d="M99.1 120.7h2.5M99.1 123.2h2.5M99.1 125.7h2.5M99.1 128.3h2.5M99.1 130.8h2.5M99.1 133.4h2.5M99.1 135.9h2.5M99.1 138.4h2.5M40.6 141h2.6M40.6 143.5h2.6M40.6 146.1h2.6M40.6 148.6h2.6"/>
<path d="M99.1 141h2.5M99.1 143.5h2.5M99.1 146.1h2.5M99.1 148.6h2.5M254 158.8h3.8M258.8 157.7v2.1M259.3 157.7v2.1M260.3 158.8h3.9"/>
</g>
<g fill="none" stroke="#840000" stroke-width="1.3">
<circle cx="15.2" cy="181.6" r="1.27"/>
<circle cx="33" cy="193" r="1.27"/>
<circle cx="33" cy="181.6" r="1.27"/>
</g>
<path d="M258.6 25.9h3.5v1.5h-3.5zM276.1 30h1.5v3.5h-1.5z" fill="none" stroke="#840000" stroke-width=".2"/>
<path d="M251.5 26.7l2.5-1.3v2.5zM251.5 25.4v2.5M275.6 39.4h2.5l-1.2 2.5zM275.6 41.9h2.5" fill="none" stroke="#840000" stroke-width=".25"/>
<g fill="#840000" stroke="#840000" stroke-width=".15">
<path d="M245.4 116.1l.4-.2 .3-.1v2.1a1.02 1.02 0 0 1-.9-.7 1.02 1.02 0 0 1 .2-1.1z"/>
<path d="M246.6 115.8a1.02 1.02 0 0 1 1 1 1.02 1.02 0 0 1-1 1.1z"/>
<path d="M258.6 158.2h1v1.1h-1z"/>
<path d="M259.3 157.7a1.02 1.02 0 0 1 1 1.1 1.02 1.02 0 0 1-1 1z"/>
<path d="M258.1 158l.4-.2 .3-.1v2.1a1.02 1.02 0 0 1-.9-.7 1.02 1.02 0 0 1 .2-1.1z"/>
</g>
<path d="M166.4 49.5h35.5v96.6h-35.5z" fill="#ffffc2"/>
<path d="M166.4 49.5h35.5v96.6h-35.5z" fill="none" stroke="#840000" stroke-width=".25"/>
<g fill="none" stroke="#840000" stroke-width=".15">
<path d="M163.8 57.2h2.6M163.8 59.7h2.6M166.4 56.9h.9v.5h-.9zM166.4 59.4h.9v.5h-.9zM178.8 49.5h.5v.9h-.5zM179.1 47v2.5M181.4 49.5h.5v.9h-.5zM181.6 47v2.5M186.4 49.5h.5v.9h-.5zM186.7 47v2.5M189 49.5h.5v.9h-.5zM189.2 47v2.5"/>
<path d="M201 56.9h.9v.5h-.9zM201 59.4h.9v.5h-.9zM201.9 57.2h2.6M201.9 59.7h2.6M163.8 64.8h2.6M163.8 67.3h2.6M163.8 72.4h2.6M163.8 74.9h2.6M163.8 77.5h2.6M166.4 64.5h.9v.5h-.9zM166.4 67.1h.9v.5h-.9zM166.4 72.1h.9v.5h-.9z"/>
<path d="M166.4 74.7h.9v.5h-.9zM166.4 77.2h.9v.5h-.9zM201 64.5h.9v.5h-.9zM201 67.1h.9v.5h-.9zM201 69.6h.9v.5h-.9zM201 74.7h.9v.5h-.9zM201 77.2h.9v.5h-.9zM201 79.8h.9v.5h-.9zM201.9 64.8h2.6M201.9 67.3h2.6M201.9 69.9h2.6M201.9 74.9h2.6"/>
<path d="M201.9 77.5h2.6M163.8 97.8h2.6M163.8 85.1h2.6M163.8 87.6h2.6M163.8 90.2h2.6M163.8 92.7h2.6M163.8 82.6h2.6M166.4 82.3h.9v.5h-.9zM166.4 84.8h.9v.5h-.9zM166.4 87.4h.9v.5h-.9zM166.4 89.9h.9v.5h-.9zM166.4 92.5h.9v.5h-.9z"/>
<path d="M166.4 97.5h.9v.5h-.9zM201 84.8h.9v.5h-.9zM201 87.4h.9v.5h-.9zM201 89.9h.9v.5h-.9zM201 92.5h.9v.5h-.9zM201 95h.9v.5h-.9zM201 97.5h.9v.5h-.9zM201.9 97.8h2.6M201.9 85.1h2.6M201.9 87.6h2.6M201.9 90.2h2.6M201.9 92.7h2.6"/>
<path d="M201.9 95.3h2.6M201.9 80h2.6M163.8 100.3h2.6M163.8 114.3h2.6M163.8 116.8h2.6M163.8 119.4h2.6M166.4 100.1h.9v.5h-.9zM201.9 114.3h2.6M201.9 116.8h2.6M201.9 119.4h2.6M163.8 121.9h2.6M163.8 124.5h2.6"/>
<path d="M163.8 127h2.6M201.9 121.9h2.6M201.9 124.5h2.6M201.9 127h2.6M175 145.2h.5v.9h-.5zM175.3 146.1v2.5M177.5 145.2h.6v.9h-.6zM177.8 146.1v2.5M180.1 145.2h.5v.9h-.5zM180.3 146.1v2.5M182.6 145.2h.5v.9h-.5zM182.9 146.1v2.5"/>
<path d="M185.2 145.2h.5v.9h-.5zM185.4 146.1v2.5M187.7 145.2h.5v.9h-.5zM188 146.1v2.5M190.2 145.2h.6v.9h-.6zM190.5 146.1v2.5M192.8 145.2h.5v.9h-.5zM193 146.1v2.5"/>
</g>
<path d="M167.5 84h3.6M167.5 81.4h3.6" fill="none" stroke="#006464" stroke-width=".15"/>
<path d="M64.8 176.5h7.6v15.3h-7.6z" fill="#ffffc2"/>
<path d="M63.5 177.8h1.3v2.5h-1.3z" fill="#840000" stroke="#840000" stroke-width=".25"/>
<path d="M64.8 176.5h7.6v15.3h-7.6zM66 180.3l.7-.6 .6 .6v10.2h5.1M67.9 180.3l.7-.6 .6 .6v5.1h3.2M69.8 180.3l.7-.6 .6 .6h1.3" fill="none" stroke="#840000" stroke-width=".25"/>
<path d="M71.9 179.6l-.3 .5M74.9 177.8h-3.3v2.3l-.2-.5M68.8 189.7l-.2 .5M70.6 184.7l-.2 .5M72.4 185.4h2.5M72.4 190.5h2.5M72.4 180.3h2.5M74.9 188h-6.3v2.2l-.3-.5M74.9 182.9h-4.5v2.3l-.3-.5" fill="none" stroke="#840000" stroke-width=".15"/>
<path d="M64.8 152.4h7.6v15.2h-7.6z" fill="#ffffc2"/>
<path d="M63.5 153.7h1.3v2.5h-1.3z" fill="#840000" stroke="#840000" stroke-width=".25"/>
<path d="M64.8 152.4h7.6v15.2h-7.6zM66 156.2l.7-.6 .6 .6v10.2h5.1M67.9 156.2l.7-.6 .6 .6v5.1h3.2M69.8 156.2l.7-.6 .6 .6h1.3" fill="none" stroke="#840000" stroke-width=".25"/>
<g fill="none" stroke="#840000" stroke-width=".15">
<path d="M194.3 39.4h.1M194.3 36.8l-.8 1.3M194.3 36.8l.8 1.3M194.3 36.8v2.6M276.9 36.8v2.6M237.5 53.3h5.1M237.5 55.9h5.1M237.5 48.3h5.1M268 48.3h5M276.9 41.9v2.6M237.5 61h5.1M105.4 113v1.3h1.3l-1.3 1.3-1.3-1.3h1.3"/>
<path d="M105.4 113h.1M111.8 118.1l-.8 1.3M111.8 118.1l.7 1.3M111.8 118.1v2.6M111.8 120.7h.1M71.9 155.4l-.3 .6M72.4 156.2h2.5M74.9 158.8h-4.5v2.2l-.3-.5M74.9 153.7h-3.3v2.3l-.2-.6M240 146.1h3.8M244.9 145v2.1M245.4 145v2.1"/>
<path d="M246.4 146.1h3.8M68.8 165.6l-.2 .5M70.6 160.5l-.2 .5M72.4 161.3h2.5M72.4 166.4h2.5M74.9 163.8h-6.3v2.3l-.3-.5M107.9 188h3.9M112.8 186.9v2.1M113.3 186.9v2.1M114.3 188h3.8"/>
</g>
<g fill="#9c9b98" stroke="#9c9b98" stroke-width=".15">
<path d="M152.4 24h.9v.3h-.9z"/>
<path d="M152.4 26.5h.9v.3h-.9z"/>
<path d="M152.4 29.1h.9v.2h-.9z"/>
</g>
<path d="M153.3 24.1h4.2M153.3 26.7h4.2M153.3 29.2h4.2" fill="none" stroke="#9c9b98" stroke-width=".15"/>
<path d="M149.9 23.2l6.3 7M156.2 23.2l-6.3 7" fill="none" stroke="#e12e31" stroke-width=".46"/>
<g fill="#840000" stroke="#840000" stroke-width=".15">
<path d="M244.1 145.3l.4-.2 .4-.1v2.1a1.02 1.02 0 0 1-1-.7 1.02 1.02 0 0 1 .2-1.1z"/>
<path d="M245.4 145a1.02 1.02 0 0 1 1 1.1 1.02 1.02 0 0 1-1 1z"/>
<path d="M112.5 187.5h1v1h-1z"/>
<path d="M112.1 187.2l.3-.2 .4-.1v2.1a1.02 1.02 0 0 1-1-.7 1.02 1.02 0 0 1 .3-1.1z"/>
<path d="M113.3 186.9a1.02 1.02 0 0 1 1 1.1 1.02 1.02 0 0 1-1 1z"/>
</g>
<path d="M170.2 36.2h.6l.6 .6-.6 .7h-.6zM172.1 26h.6v1.3h-.6l-.7-.6zM172.1 28.6h.6v1.2h-.6l-.7-.6zM276.2 25.4h1.3v.6l-.6 .7-.7-.7zM208.9 56.5h.6v1.3h-.6l-.6-.6zM208.9 59.1h.6v1.2h-.6l-.6-.6zM236.2 47.6h.7l.6 .7-.6 .6h-.7zM125.1 87h.6v1.3h-.6l-.6-.7zM125.1 92.1h.6v1.2h-.6l-.6-.6zM24.1 127.6h.7l.6 .7-.6 .6h-.7zM27.9 158.1h.7l.6 .7-.6 .6h-.7z" fill="none" stroke="#725600" stroke-width=".15"/>
<g fill="none" stroke="#009600" stroke-width=".15">
<path d="M35.6 39.4h5M35.6 31.8h5M40.6 24.1h-5v122h5M101.6 24.1h3.8v88.9h-3.8M101.6 39.4h3.8M101.6 31.8h3.8M157.5 24.1h35.5M157.5 26.7h13.9M157.5 29.2h13.9M171.4 36.8h10.2v10.2M179.1 36.8v10.2M189.2 39.4v7.6"/>
<path d="M194.3 39.4h-7.6v7.6M245.1 26.7h3.8M256.5 26.7h1.3M262.9 26.7h14v2.5M276.9 34.3v2.5M16.5 57.2h24.1M16.5 59.7h24.1M16.5 52.1h24.1M16.5 54.6h24.1M35.6 49.5h5M101.6 57.2h22.9M101.6 59.7h22.9"/>
<path d="M101.6 52.1h3.8M101.6 49.5h22.9M101.6 54.6h22.9M146 57.2h17.8M146 59.7h17.8M204.5 57.2h3.8M204.5 59.7h3.8M237.5 55.9v16.5M237.5 53.3h1.3M276.9 44.5v3.8h-3.9M16.5 67.3h24.1M16.5 72.4h24.1"/>
<path d="M16.5 64.8h24.1M16.5 77.5h24.1M16.5 69.9h24.1M35.6 74.9h5M35.6 62.2h5M101.6 74.9h22.9M101.6 67.3h22.9M101.6 72.4h22.9M101.6 64.8h3.8M101.6 77.5h3.8M101.6 69.9h22.9M101.6 62.2h22.9"/>
<path d="M146 74.9h17.8M146 67.3h17.8M146 72.4h17.8M146 64.8h17.8M146 77.5h17.8M204.5 74.9h16.5M204.5 67.3h16.5M204.5 64.8h16.5M204.5 77.5h16.5M204.5 69.9h16.5M16.5 85.1h24.1M16.5 92.7h24.1"/>
<path d="M16.5 95.3h24.1M16.5 90.2h24.1M16.5 82.6h24.1M16.5 80h24.1M35.6 87.6h5M35.6 97.8h5M101.6 87.6h22.9M101.6 85.1h22.9M101.6 92.7h22.9M101.6 97.8h3.8M101.6 90.2h3.8M101.6 82.6h22.9"/>
<path d="M101.6 80h22.9M146 87.6h17.8M146 85.1h17.8M146 92.7h17.8M146 97.8h17.8M146 90.2h17.8M146 82.6h17.8M204.5 87.6h16.5M204.5 85.1h16.5M204.5 92.7h16.5M204.5 95.3h16.5M204.5 97.8h16.5"/>
<path d="M204.5 90.2h16.5M204.5 80h16.5M35.6 115.6h5M35.6 105.4h5M101.6 105.4h3.8M146 100.3h17.8M163.8 116.8h-21.6v39.4h-67.3M163.8 114.3h-24.1v47h-64.8M163.8 119.4h-19v47h-69.9M204.5 114.3h29.2v2.5h7.6M204.5 119.4h5v2.5M251.5 116.8h19"/>
<path d="M270.5 111.8h-47v5h-19M25.4 128.3h15.2M40.6 120.7h-15.2v10.1h15.2M101.6 120.7h10.2M101.6 123.2h3.8M101.6 125.7h3.8M101.6 130.8h3.8M101.6 128.3h3.8M105.4 120.7v12.7h-3.8M163.8 121.9h-11.4v68.6h-77.5M163.8 124.5h-8.9v55.8h-80M163.8 127h-6.3v58.4h-82.6"/>
<path d="M204.5 121.9h66M204.5 124.5h34.3v21.6h1.2M204.5 127h20.3v24.1h45.7M228.6 121.9v39.4h41.9M40.6 148.6v10.2h-11.4M74.9 153.7h3.8v12.7M74.9 158.8h3.8M101.6 143.5h19M175.3 148.6v7.6M177.8 148.6v5.1M180.3 148.6v5.1M182.9 148.6v5.1"/>
<path d="M185.4 148.6v5.1M188 148.6v5.1M190.5 148.6v5.1M193 148.6v5.1h-17.7M233.7 158.8h20.3M250.2 146.1h15.2v10.1h5.1M264.2 158.8h6.3M74.9 177.8h3.8v12.7M74.9 188h33M74.9 182.9h3.8M118.1 188h25.4"/>
</g>
<g fill="none" stroke="#000084" stroke-width=".15">
<path d="M40 33.7l1.2 1.2M40 36.2l1.2 1.2M40 26.1l1.2 1.2M40 28.6l1.2 1.2M41.2 33.7l-1.2 1.2M41.2 36.2l-1.2 1.2M41.2 26.1l-1.2 1.2M41.2 28.6l-1.2 1.2M101 26.1l1.2 1.2M101 28.6l1.2 1.2M101 36.2l1.2 1.2M101 33.7l1.2 1.2"/>
<path d="M102.2 26.1l-1.2 1.2M102.2 28.6l-1.2 1.2M102.2 36.2l-1.2 1.2M102.2 33.7l-1.2 1.2M40 46.4l1.2 1.2M40 43.8l1.2 1.3M40 41.3l1.2 1.2M41.2 46.4l-1.2 1.2M41.2 43.8l-1.2 1.3M41.2 41.3l-1.2 1.2M101 46.4l1.2 1.2M101 43.8l1.2 1.3"/>
<path d="M101 41.3l1.2 1.2M102.2 46.4l-1.2 1.2M102.2 43.8l-1.2 1.3M102.2 41.3l-1.2 1.2M40 99.7l1.2 1.2M41.2 99.7l-1.2 1.2M101 94.6l1.2 1.3M101 99.7l1.2 1.2M102.2 94.6l-1.2 1.3M102.2 99.7l-1.2 1.2M40 109.9l1.2 1.2M40 117.5l1.2 1.2"/>
<path d="M40 112.4l1.2 1.2M40 102.3l1.2 1.2M40 107.3l1.2 1.3M41.2 109.9l-1.2 1.2M41.2 117.5l-1.2 1.2M41.2 112.4l-1.2 1.2M41.2 102.3l-1.2 1.2M41.2 107.3l-1.2 1.3M101 117.5l1.2 1.2M101 102.3l1.2 1.2M101 115l1.2 1.2M101 109.9l1.2 1.2"/>
<path d="M101 107.3l1.2 1.3M102.2 117.5l-1.2 1.2M102.2 102.3l-1.2 1.2M102.2 115l-1.2 1.2M102.2 109.9l-1.2 1.2M102.2 107.3l-1.2 1.3M269.9 118.8l1.2 1.2M269.9 108.6l1.2 1.2M269.9 113.7l1.2 1.2M271.1 118.8l-1.2 1.2M271.1 108.6l-1.2 1.2M271.1 113.7l-1.2 1.2"/>
<path d="M40 125.1l1.2 1.2M40 132.7l1.2 1.3M40 122.6l1.2 1.2M40 137.8l1.2 1.2M40 135.3l1.2 1.2M41.2 125.1l-1.2 1.2M41.2 132.7l-1.2 1.3M41.2 122.6l-1.2 1.2M41.2 137.8l-1.2 1.2M41.2 135.3l-1.2 1.2M101 135.3l1.2 1.2M101 137.8l1.2 1.2"/>
<path d="M102.2 135.3l-1.2 1.2M102.2 137.8l-1.2 1.2M40 142.9l1.2 1.2M40 140.4l1.2 1.2M41.2 142.9l-1.2 1.2M41.2 140.4l-1.2 1.2M101 148l1.2 1.2M101 140.4l1.2 1.2M101 145.4l1.2 1.3M102.2 148l-1.2 1.2M102.2 140.4l-1.2 1.2M102.2 145.4l-1.2 1.3"/>
<path d="M269.9 148l1.2 1.2M269.9 153.1l1.2 1.2M271.1 148l-1.2 1.2M271.1 153.1l-1.2 1.2M74.3 163.2l1.2 1.2M75.5 163.2l-1.2 1.2"/>
</g>
<path d="M139.7 14h59.1v17.8h-59.1zM224.8 16.5h58.4v59.7h-58.4z" fill="none" stroke="#0000c2" stroke-width=".15"/>
<g fill="#009600" stroke="#009600" stroke-width=".13">
<circle cx="78.7" cy="166.4" r=".46"/>
<circle cx="35.6" cy="115.6" r=".46"/>
<circle cx="25.4" cy="128.3" r=".46"/>
<circle cx="35.6" cy="146.1" r=".46"/>
<circle cx="105.4" cy="113" r=".46"/>
<circle cx="35.6" cy="49.5" r=".46"/>
<circle cx="35.6" cy="39.4" r=".46"/>
<circle cx="35.6" cy="62.2" r=".46"/>
<circle cx="105.4" cy="90.2" r=".46"/>
<circle cx="105.4" cy="97.8" r=".46"/>
<circle cx="105.4" cy="77.5" r=".46"/>
<circle cx="35.6" cy="31.8" r=".46"/>
<circle cx="105.4" cy="105.4" r=".46"/>
<circle cx="105.4" cy="120.7" r=".46"/>
<circle cx="105.4" cy="125.7" r=".46"/>
<circle cx="105.4" cy="128.3" r=".46"/>
<circle cx="105.4" cy="123.2" r=".46"/>
<circle cx="105.4" cy="130.8" r=".46"/>
<circle cx="78.7" cy="158.8" r=".46"/>
<circle cx="78.7" cy="182.9" r=".46"/>
<circle cx="78.7" cy="190.5" r=".46"/>
<circle cx="105.4" cy="52.1" r=".46"/>
<circle cx="105.4" cy="39.4" r=".46"/>
<circle cx="105.4" cy="31.8" r=".46"/>
<circle cx="105.4" cy="64.8" r=".46"/>
<circle cx="35.6" cy="87.6" r=".46"/>
<circle cx="35.6" cy="74.9" r=".46"/>
<circle cx="35.6" cy="105.4" r=".46"/>
<circle cx="35.6" cy="97.8" r=".46"/>
<circle cx="209.5" cy="121.9" r=".46"/>
<circle cx="179.1" cy="36.8" r=".46"/>
<circle cx="237.5" cy="61" r=".46"/>
<circle cx="189.2" cy="39.4" r=".46"/>
<circle cx="180.3" cy="153.7" r=".46"/>
<circle cx="185.4" cy="153.7" r=".46"/>
<circle cx="182.9" cy="153.7" r=".46"/>
<circle cx="190.5" cy="153.7" r=".46"/>
<circle cx="188" cy="153.7" r=".46"/>
<circle cx="177.8" cy="153.7" r=".46"/>
<circle cx="175.3" cy="153.7" r=".46"/>
<circle cx="228.6" cy="121.9" r=".46"/>
</g>
<use href="#words"/>
</svg>
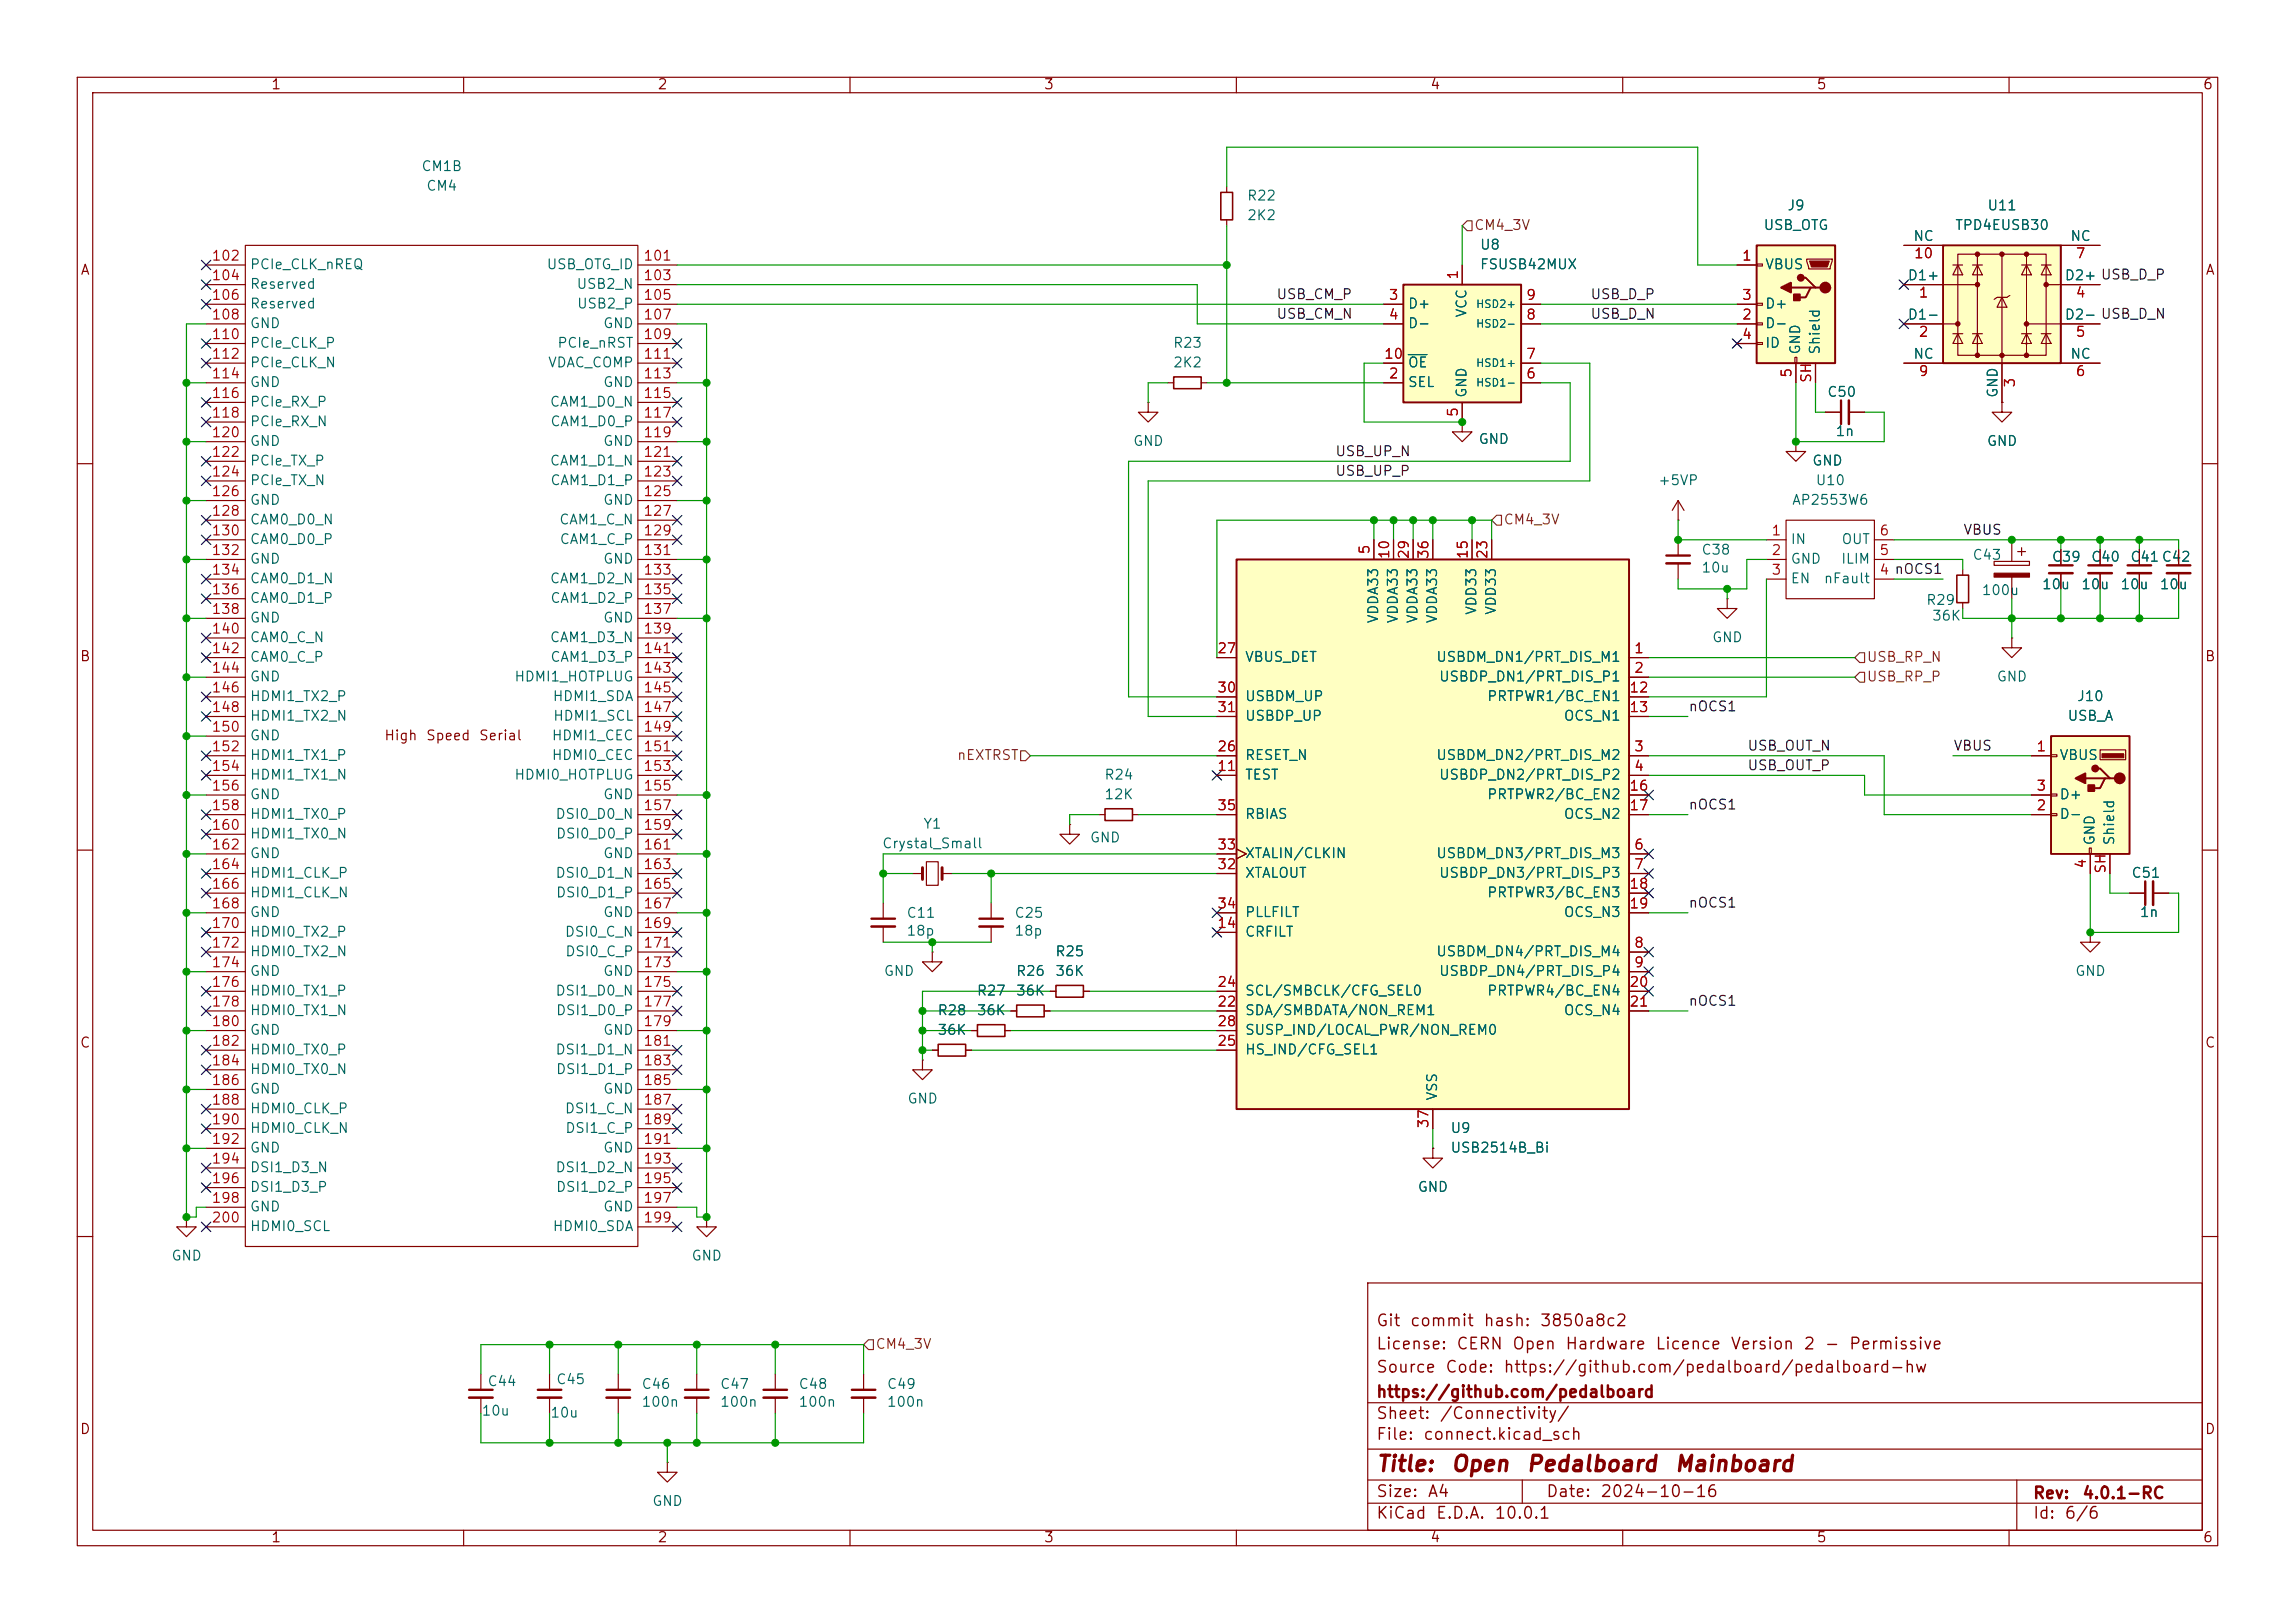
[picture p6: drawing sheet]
<svg xmlns="http://www.w3.org/2000/svg" width="297mm" height="210mm" viewBox="0 0 297 210" stroke-linecap="round" stroke-linejoin="round" font-family="sans-serif">
<defs><g id="words">
<g font-size="2" fill="#840000">
<text x="178" y="190.9">Title:</text>
<text x="187.7" y="190.9">Open</text>
<text x="197.4" y="190.9">Pedalboard</text>
<text x="216.6" y="190.9">Mainboard</text>
</g>
<g font-size="1.5" fill="#840000">
<text x="178" y="172">Git</text>
<text x="182.4" y="172">commit</text>
<text x="191.9" y="172">hash:</text>
<text x="199.2" y="172">3850a8c2</text>
<text x="178" y="178">Source</text>
<text x="178" y="175">License:</text>
<text x="186.9" y="178">Code:</text>
<text x="188.4" y="175">CERN</text>
<text x="194.5" y="178">https://github.com/pedalboard/pedalboard-hw</text>
<text x="195.6" y="175">Open</text>
<text x="202.5" y="175">Hardware</text>
<text x="214.1" y="175">Licence</text>
<text x="223.9" y="175">Version</text>
<text x="233.3" y="175">2</text>
<text x="236" y="175">-</text>
<text x="239.2" y="175">Permissive</text>
<text x="178" y="184">Sheet:</text>
<text x="178" y="181.2">https://github.com/pedalboard</text>
<text x="186.2" y="184">/Connectivity/</text>
<text x="178" y="186.7">File:</text>
<text x="184.1" y="186.7">connect.kicad_sch</text>
<text x="178" y="196.9">KiCad</text>
<text x="178" y="194.1">Size:</text>
<text x="184.7" y="194.1">A4</text>
<text x="185.7" y="196.9">E.D.A.</text>
<text x="193.3" y="196.9">10.0.1</text>
<text x="200" y="194.1">Date:</text>
<text x="207" y="194.1">2024-10-16</text>
<text x="263" y="194.3">Rev:</text>
<text x="263" y="196.9">Id:</text>
<text x="267.1" y="196.9">6/6</text>
<text x="269.4" y="194.3">4.0.1-RC</text>
</g>
<g font-size="1.3" fill="#840000">
<text x="35" y="11.9">1</text>
<text x="85" y="11.9">2</text>
<text x="135" y="11.9">3</text>
<text x="185" y="11.9">4</text>
<text x="235" y="11.9">5</text>
<text x="285" y="11.9">6</text>
<text x="10.3" y="35.9">A</text>
<text x="285.3" y="35.9">A</text>
<text x="10.3" y="85.9">B</text>
<text x="285.3" y="85.9">B</text>
<text x="49.6" y="96.1">High</text>
<text x="55" y="96.1">Speed</text>
<text x="61.9" y="96.1">Serial</text>
<text x="10.3" y="135.9">C</text>
<text x="285.3" y="135.9">C</text>
<text x="10.3" y="185.9">D</text>
<text x="285.3" y="185.9">D</text>
<text x="35" y="199.9">1</text>
<text x="85" y="199.9">2</text>
<text x="135" y="199.9">3</text>
<text x="185" y="199.9">4</text>
<text x="235" y="199.9">5</text>
<text x="285" y="199.9">6</text>
</g>
<g font-size="1.3" fill="#006464">
<text x="54.4" y="22.5">CM1B</text>
<text x="55.1" y="25">CM4</text>
<text x="161.3" y="26.3">R22</text>
<text x="161.3" y="28.8">2K2</text>
<text x="231.2" y="27.5">J9</text>
<text x="257.1" y="27.5">U11</text>
<text x="32.3" y="35.2">PCIe_CLK_nREQ</text>
<text x="70.7" y="35.2">USB_OTG_ID</text>
<text x="191.4" y="35.2">FSUSB42MUX</text>
<text x="191.4" y="32.6">U8</text>
<text x="228.1" y="30.1">USB_OTG</text>
<text x="228.3" y="35.2">VBUS</text>
<text x="247.5" y="31.5">NC</text>
<text x="252.9" y="30.1">TPD4EUSB30</text>
<text x="267.8" y="31.5">NC</text>
<text x="32.3" y="37.7">Reserved</text>
<text x="32.3" y="40.2">Reserved</text>
<text x="74.5" y="37.7">USB2_N</text>
<text x="74.6" y="40.2">USB2_P</text>
<text x="182.1" y="40.2">D+</text>
<text x="190.1" y="41.2" transform="rotate(-90 190.1 41.2)">VCC</text>
<text x="228.3" y="40.2">D+</text>
<text x="246.8" y="36.6">D1+</text>
<text x="246.8" y="41.7">D1-</text>
<text x="267.1" y="36.6">D2+ USB_D_P</text>
<text x="267.1" y="41.7">D2- USB_D_N</text>
<text x="267.1" y="36.6">D2+</text>
<text x="267.1" y="41.7">D2-</text>
<text x="32.3" y="42.8">GND</text>
<text x="32.3" y="45.3">PCIe_CLK_P</text>
<text x="32.3" y="47.9">PCIe_CLK_N</text>
<text x="70.8" y="47.9">VDAC_COMP</text>
<text x="72" y="45.3">PCIe_nRST</text>
<text x="78" y="42.8">GND</text>
<text x="151.7" y="45.3">R23</text>
<text x="151.7" y="47.9">2K2</text>
<text x="182.1" y="42.8">D-</text>
<text x="182.1" y="47.9">OE</text>
<text x="228.3" y="42.8">D-</text>
<text x="228.3" y="45.3">ID</text>
<text x="233.3" y="46" transform="rotate(-90 233.3 46)">GND</text>
<text x="235.8" y="46" transform="rotate(-90 235.8 46)">Shield</text>
<text x="247.5" y="46.7">NC</text>
<text x="267.8" y="46.7">NC</text>
<text x="32.3" y="50.4">GND</text>
<text x="32.3" y="52.9">PCIe_RX_P</text>
<text x="71.1" y="52.9">CAM1_D0_N</text>
<text x="78" y="50.4">GND</text>
<text x="182.1" y="50.4">SEL</text>
<text x="190.1" y="51.6" transform="rotate(-90 190.1 51.6)">GND</text>
<text x="236.4" y="51.7">C50</text>
<text x="258.8" y="51.6" transform="rotate(-90 258.8 51.6)">GND</text>
<text x="32.3" y="55.5">PCIe_RX_N</text>
<text x="32.3" y="58">GND</text>
<text x="71.1" y="55.5">CAM1_D0_P</text>
<text x="78" y="58">GND</text>
<text x="146.6" y="58">GND</text>
<text x="191.3" y="57.8">GND</text>
<text x="237.5" y="56.7">1n</text>
<text x="257" y="58">GND</text>
<text x="32.3" y="60.6">PCIe_TX_P</text>
<text x="32.3" y="63.1">PCIe_TX_N</text>
<text x="32.3" y="65.6">GND</text>
<text x="71.1" y="60.6">CAM1_D1_N</text>
<text x="71.1" y="63.1">CAM1_D1_P</text>
<text x="78" y="65.6">GND</text>
<text x="214.5" y="63.1">+5VP</text>
<text x="231.8" y="65.6">AP2553W6</text>
<text x="234.4" y="60.6">GND</text>
<text x="234.9" y="63.1">U10</text>
<text x="32.3" y="68.2">CAM0_D0_N</text>
<text x="32.3" y="70.7">CAM0_D0_P</text>
<text x="72.3" y="68.2">CAM1_C_N</text>
<text x="72.3" y="70.7">CAM1_C_P</text>
<text x="231.6" y="70.7">IN</text>
<text x="238.2" y="70.7">OUT</text>
<text x="32.3" y="73.3">GND</text>
<text x="32.3" y="75.8">CAM0_D1_N</text>
<text x="71.1" y="75.8">CAM1_D2_N</text>
<text x="78" y="73.3">GND</text>
<text x="220.1" y="72.1">C38</text>
<text x="220.1" y="74.4">10u</text>
<text x="231.6" y="73.3">GND</text>
<text x="231.6" y="75.8">EN</text>
<text x="235.9" y="75.8">nFault</text>
<text x="238.2" y="73.3">ILIM</text>
<text x="255.2" y="72.7">C43</text>
<text x="256.4" y="77.3">100u</text>
<text x="264.2" y="76.6">10u</text>
<text x="265.4" y="73">C39</text>
<text x="269.2" y="76.6">10u</text>
<text x="270.5" y="73">C40</text>
<text x="274.3" y="76.6">10u</text>
<text x="275.6" y="73">C41C42</text>
<text x="279.4" y="76.6">10u</text>
<text x="32.3" y="78.3">CAM0_D1_P</text>
<text x="32.3" y="80.9">GND</text>
<text x="32.3" y="83.4">CAM0_C_N</text>
<text x="71.1" y="83.4">CAM1_D3_N</text>
<text x="71.1" y="78.3">CAM1_D2_P</text>
<text x="78" y="80.9">GND</text>
<text x="178.7" y="80.7" transform="rotate(-90 178.7 80.7)">VDDA33</text>
<text x="181.2" y="80.7" transform="rotate(-90 181.2 80.7)">VDDA33</text>
<text x="183.7" y="80.7" transform="rotate(-90 183.7 80.7)">VDDA33</text>
<text x="186.3" y="80.7" transform="rotate(-90 186.3 80.7)">VDDA33</text>
<text x="191.4" y="79.7" transform="rotate(-90 191.4 79.7)">VDD33</text>
<text x="193.9" y="79.7" transform="rotate(-90 193.9 79.7)">VDD33</text>
<text x="221.5" y="83.4">GND</text>
<text x="249.2" y="78.6">R29</text>
<text x="249.9" y="80.6">36K</text>
<text x="32.3" y="86">CAM0_C_P</text>
<text x="32.3" y="88.5">GND</text>
<text x="66.5" y="88.5">HDMI1_HOTPLUG</text>
<text x="71.1" y="86">CAM1_D3_P</text>
<text x="161" y="86">VBUS_DET</text>
<text x="185.8" y="86">USBDM_DN1/PRT_DIS_M1</text>
<text x="186.1" y="88.5">USBDP_DN1/PRT_DIS_P1</text>
<text x="258.3" y="88.5">GND</text>
<text x="32.3" y="91">HDMI1_TX2_P</text>
<text x="32.3" y="93.6">HDMI1_TX2_N</text>
<text x="71.4" y="91">HDMI1_SDA</text>
<text x="71.5" y="93.6">HDMI1_SCL</text>
<text x="161" y="91">USBDM_UP</text>
<text x="161" y="93.6">USBDP_UP</text>
<text x="192.4" y="91">PRTPWR1/BC_EN1</text>
<text x="202.3" y="93.6">OCS_N1</text>
<text x="267.5" y="93.6">USB_A</text>
<text x="268.7" y="91">J10</text>
<text x="32.3" y="96.1">GND</text>
<text x="32.3" y="98.7">HDMI1_TX1_P</text>
<text x="32.3" y="101.2">HDMI1_TX1_N</text>
<text x="66.5" y="101.2">HDMI0_HOTPLUG</text>
<text x="71.3" y="96.1">HDMI1_CEC</text>
<text x="71.3" y="98.7">HDMI0_CEC</text>
<text x="142.8" y="101.2">R24</text>
<text x="161" y="101.2">TEST</text>
<text x="161" y="98.7">RESET_N</text>
<text x="185.8" y="98.7">USBDM_DN2/PRT_DIS_M2</text>
<text x="186.1" y="101.2">USBDP_DN2/PRT_DIS_P2</text>
<text x="266.4" y="98.7">VBUS</text>
<text x="32.3" y="103.7">GND</text>
<text x="32.3" y="106.3">HDMI1_TX0_P</text>
<text x="71.8" y="106.3">DSI0_D0_N</text>
<text x="78" y="103.7">GND</text>
<text x="119.4" y="107.5">Y1</text>
<text x="142.8" y="103.7">12K</text>
<text x="161" y="106.3">RBIAS</text>
<text x="192.4" y="103.7">PRTPWR2/BC_EN2</text>
<text x="202.3" y="106.3">OCS_N2</text>
<text x="266.4" y="106.3">D-</text>
<text x="266.4" y="103.7">D+</text>
<text x="32.3" y="108.8">HDMI1_TX0_N</text>
<text x="32.3" y="111.4">GND</text>
<text x="32.3" y="113.9">HDMI1_CLK_P</text>
<text x="71.8" y="113.9">DSI0_D1_N</text>
<text x="71.9" y="108.8">DSI0_D0_P</text>
<text x="78" y="111.4">GND</text>
<text x="114.1" y="110.1">Crystal_Small</text>
<text x="141" y="109.3">GND</text>
<text x="161" y="113.9">XTALOUT</text>
<text x="161" y="111.4">XTALIN/CLKIN</text>
<text x="185.8" y="111.4">USBDM_DN3/PRT_DIS_M3</text>
<text x="186.1" y="113.9">USBDP_DN3/PRT_DIS_P3</text>
<text x="271.4" y="109.5" transform="rotate(-90 271.4 109.5)">GND</text>
<text x="273.9" y="109.5" transform="rotate(-90 273.9 109.5)">Shield</text>
<text x="275.8" y="113.9">C51</text>
<text x="32.3" y="116.4">HDMI1_CLK_N</text>
<text x="32.3" y="119">GND</text>
<text x="71.9" y="116.4">DSI0_D1_P</text>
<text x="78" y="119">GND</text>
<text x="117.2" y="119.1">C11</text>
<text x="131.2" y="119.1">C25</text>
<text x="161" y="119">PLLFILT</text>
<text x="192.4" y="116.4">PRTPWR3/BC_EN3</text>
<text x="202.3" y="119">OCS_N3</text>
<text x="276.8" y="119">1n</text>
<text x="32.3" y="121.5">HDMI0_TX2_P</text>
<text x="32.3" y="124.1">HDMI0_TX2_N</text>
<text x="73" y="121.5">DSI0_C_N</text>
<text x="73.1" y="124.1">DSI0_C_P</text>
<text x="117.2" y="121.4">18p</text>
<text x="131.2" y="121.4">18p</text>
<text x="136.5" y="124.1">R25</text>
<text x="161" y="121.5">CRFILT</text>
<text x="185.8" y="124.1">USBDM_DN4/PRT_DIS_M4</text>
<text x="32.3" y="126.6">GND</text>
<text x="32.3" y="129.1">HDMI0_TX1_P</text>
<text x="32.3" y="131.7">HDMI0_TX1_N</text>
<text x="71.8" y="129.1">DSI1_D0_N</text>
<text x="71.9" y="131.7">DSI1_D0_P</text>
<text x="78" y="126.6">GND</text>
<text x="114.3" y="126.6">GND</text>
<text x="121.2" y="131.7">R28</text>
<text x="126.3" y="129.1">R27</text>
<text x="126.3" y="131.7">36K</text>
<text x="131.4" y="126.6">R26</text>
<text x="131.4" y="129.1">36K</text>
<text x="136.5" y="126.6">36K</text>
<text x="161" y="131.7">SDA/SMBDATA/NON_REM1</text>
<text x="161" y="129.1">SCL/SMBCLK/CFG_SEL0</text>
<text x="186.1" y="126.6">USBDP_DN4/PRT_DIS_P4</text>
<text x="192.4" y="129.1">PRTPWR4/BC_EN4</text>
<text x="202.3" y="131.7">OCS_N4</text>
<text x="268.5" y="126.6">GND</text>
<text x="32.3" y="134.2">GND</text>
<text x="32.3" y="136.8">HDMI0_TX0_P</text>
<text x="71.8" y="136.8">DSI1_D1_N</text>
<text x="78" y="134.2">GND</text>
<text x="121.2" y="134.2">36K</text>
<text x="161" y="136.8">HS_IND/CFG_SEL1</text>
<text x="161" y="134.2">SUSP_IND/LOCAL_PWR/NON_REM0</text>
<text x="32.3" y="139.3">HDMI0_TX0_N</text>
<text x="32.3" y="141.8">GND</text>
<text x="71.9" y="139.3">DSI1_D1_P</text>
<text x="78" y="141.8">GND</text>
<text x="117.3" y="143.1">GND</text>
<text x="186.3" y="142.5" transform="rotate(-90 186.3 142.5)">VSS</text>
<text x="32.3" y="144.4">HDMI0_CLK_P</text>
<text x="32.3" y="146.9">HDMI0_CLK_N</text>
<text x="32.3" y="149.5">GND</text>
<text x="73" y="144.4">DSI1_C_N</text>
<text x="73.1" y="146.9">DSI1_C_P</text>
<text x="78" y="149.5">GND</text>
<text x="187.6" y="146.9">U9</text>
<text x="187.6" y="149.5">USB2514B_Bi</text>
<text x="32.3" y="152">DSI1_D3_N</text>
<text x="32.3" y="154.5">DSI1_D3_P</text>
<text x="71.8" y="152">DSI1_D2_N</text>
<text x="71.9" y="154.5">DSI1_D2_P</text>
<text x="183.4" y="154.5">GND</text>
<text x="32.3" y="157.1">GND</text>
<text x="32.3" y="159.6">HDMI0_SCL</text>
<text x="71.4" y="159.6">HDMI0_SDA</text>
<text x="78" y="157.1">GND</text>
<text x="22.1" y="163.4">GND</text>
<text x="89.4" y="163.4">GND</text>
<text x="63" y="179.7">C44</text>
<text x="71.9" y="179.4">C45</text>
<text x="62.2" y="183.5">10u</text>
<text x="71.1" y="183.7">10u</text>
<text x="82.9" y="182.3">100n</text>
<text x="82.9" y="180">C46</text>
<text x="93.1" y="182.3">100n</text>
<text x="93.1" y="180">C47</text>
<text x="103.3" y="182.3">100n</text>
<text x="103.3" y="180">C48</text>
<text x="114.7" y="182.3">100n</text>
<text x="114.7" y="180">C49</text>
<text x="84.3" y="195.2">GND</text>
</g>
<g font-size="1.3" fill="#a90000">
<text x="27.3" y="34">102</text>
<text x="83.2" y="34">101</text>
<text x="225.4" y="34">1</text>
<text x="247.6" y="33.7">10</text>
<text x="268.5" y="33.7">7</text>
<text x="27.3" y="36.6">104</text>
<text x="27.3" y="39.1">106</text>
<text x="27.3" y="41.7">108</text>
<text x="83.2" y="36.6">103</text>
<text x="83.2" y="39.1">105</text>
<text x="83.2" y="41.7">107</text>
<text x="179.6" y="39.1">3</text>
<text x="179.6" y="41.7">4</text>
<text x="189" y="36.3" transform="rotate(-90 189 36.3)">1</text>
<text x="197.4" y="41.7">8</text>
<text x="197.4" y="39.1">9</text>
<text x="225.4" y="41.7">2</text>
<text x="225.4" y="39.1">3</text>
<text x="248.2" y="38.8">1</text>
<text x="268.5" y="38.8">4</text>
<text x="27.3" y="44.2">110</text>
<text x="27.3" y="46.7">112</text>
<text x="83.2" y="44.2">109</text>
<text x="83.2" y="46.7">111</text>
<text x="179" y="46.7">10</text>
<text x="197.4" y="46.7">7</text>
<text x="225.4" y="44.2">4</text>
<text x="248.2" y="43.9">2</text>
<text x="268.5" y="43.9">5</text>
<text x="27.3" y="49.3">114</text>
<text x="27.3" y="51.8">116</text>
<text x="83.2" y="49.3">113</text>
<text x="83.2" y="51.8">115</text>
<text x="179.6" y="49.3">2</text>
<text x="197.4" y="49.3">6</text>
<text x="232.2" y="49" transform="rotate(-90 232.2 49)">5</text>
<text x="234.7" y="49.6" transform="rotate(-90 234.7 49.6)">SH</text>
<text x="248.2" y="49">9</text>
<text x="261.1" y="50.2" transform="rotate(-90 261.1 50.2)">3</text>
<text x="268.5" y="49">6</text>
<text x="27.3" y="54.4">118</text>
<text x="27.3" y="56.9">120</text>
<text x="27.3" y="59.4">122</text>
<text x="83.2" y="54.4">117</text>
<text x="83.2" y="56.9">119</text>
<text x="83.2" y="59.4">121</text>
<text x="189" y="54" transform="rotate(-90 189 54)">5</text>
<text x="27.3" y="62">124</text>
<text x="27.3" y="64.5">126</text>
<text x="83.2" y="62">123</text>
<text x="83.2" y="64.5">125</text>
<text x="27.3" y="67.1">128</text>
<text x="27.3" y="69.6">130</text>
<text x="83.2" y="67.1">127</text>
<text x="83.2" y="69.6">129</text>
<text x="177.5" y="71.8" transform="rotate(-90 177.5 71.8)">5</text>
<text x="229.2" y="69.6">1</text>
<text x="243.1" y="69.6">6</text>
<text x="27.3" y="72.1">132</text>
<text x="27.3" y="74.7">134</text>
<text x="27.3" y="77.2">136</text>
<text x="83.2" y="72.1">131</text>
<text x="83.2" y="74.7">133</text>
<text x="83.2" y="77.2">135</text>
<text x="180.1" y="72.4" transform="rotate(-90 180.1 72.4)">10</text>
<text x="182.6" y="72.4" transform="rotate(-90 182.6 72.4)">29</text>
<text x="185.2" y="72.4" transform="rotate(-90 185.2 72.4)">36</text>
<text x="190.2" y="72.4" transform="rotate(-90 190.2 72.4)">15</text>
<text x="192.8" y="72.4" transform="rotate(-90 192.8 72.4)">23</text>
<text x="229.2" y="72.1">2</text>
<text x="229.2" y="74.7">3</text>
<text x="243.1" y="74.7">4 nOCS1</text>
<text x="243.1" y="72.1">5</text>
<text x="27.3" y="79.8">138</text>
<text x="27.3" y="82.3">140</text>
<text x="83.2" y="79.8">137</text>
<text x="83.2" y="82.3">139</text>
<text x="27.3" y="84.8">142</text>
<text x="27.3" y="87.4">144</text>
<text x="27.3" y="89.9">146</text>
<text x="83.2" y="84.8">141</text>
<text x="83.2" y="87.4">143</text>
<text x="83.2" y="89.9">145</text>
<text x="157.4" y="84.8">27</text>
<text x="157.4" y="89.9">30</text>
<text x="210.8" y="89.9">12</text>
<text x="211.4" y="84.8">1</text>
<text x="211.4" y="87.4">2</text>
<text x="27.3" y="92.5">148</text>
<text x="27.3" y="95">150</text>
<text x="83.2" y="92.5">147</text>
<text x="83.2" y="95">149</text>
<text x="157.4" y="92.5">31</text>
<text x="210.8" y="92.5">13</text>
<text x="27.3" y="97.5">152</text>
<text x="27.3" y="100.1">154</text>
<text x="83.2" y="97.5">151</text>
<text x="83.2" y="100.1">153</text>
<text x="157.4" y="100.1">11</text>
<text x="157.4" y="97.5">26</text>
<text x="211.4" y="97.5">3</text>
<text x="211.4" y="100.1">4</text>
<text x="263.5" y="97.5">1</text>
<text x="27.3" y="102.6">156</text>
<text x="27.3" y="105.2">158</text>
<text x="27.3" y="107.7">160</text>
<text x="83.2" y="102.6">155</text>
<text x="83.2" y="105.2">157</text>
<text x="83.2" y="107.7">159</text>
<text x="157.4" y="105.2">35</text>
<text x="210.8" y="102.6">16</text>
<text x="210.8" y="105.2">17</text>
<text x="263.5" y="105.2">2</text>
<text x="263.5" y="102.6">3</text>
<text x="27.3" y="110.2">162</text>
<text x="27.3" y="112.8">164</text>
<text x="83.2" y="110.2">161</text>
<text x="83.2" y="112.8">163</text>
<text x="157.4" y="112.8">32</text>
<text x="157.4" y="110.2">33</text>
<text x="211.4" y="110.2">6</text>
<text x="211.4" y="112.8">7</text>
<text x="270.3" y="112.5" transform="rotate(-90 270.3 112.5)">4</text>
<text x="272.8" y="113.1" transform="rotate(-90 272.8 113.1)">SH</text>
<text x="27.3" y="115.3">166</text>
<text x="27.3" y="117.9">168</text>
<text x="83.2" y="115.3">165</text>
<text x="83.2" y="117.9">167</text>
<text x="157.4" y="117.9">34</text>
<text x="210.8" y="115.3">18</text>
<text x="210.8" y="117.9">19</text>
<text x="27.3" y="120.4">170</text>
<text x="27.3" y="122.9">172</text>
<text x="27.3" y="125.5">174</text>
<text x="83.2" y="120.4">169</text>
<text x="83.2" y="122.9">171</text>
<text x="83.2" y="125.5">173</text>
<text x="157.4" y="120.4">14</text>
<text x="211.4" y="122.9">8</text>
<text x="211.4" y="125.5">9</text>
<text x="27.3" y="128">176</text>
<text x="27.3" y="130.6">178</text>
<text x="83.2" y="128">175</text>
<text x="83.2" y="130.6">177</text>
<text x="157.4" y="130.6">22</text>
<text x="157.4" y="128">24</text>
<text x="210.8" y="128">20</text>
<text x="210.8" y="130.6">21</text>
<text x="27.3" y="133.1">180</text>
<text x="27.3" y="135.6">182</text>
<text x="83.2" y="133.1">179</text>
<text x="83.2" y="135.6">181</text>
<text x="157.4" y="135.6">25</text>
<text x="157.4" y="133.1">28</text>
<text x="27.3" y="138.2">184</text>
<text x="27.3" y="140.7">186</text>
<text x="27.3" y="143.3">188</text>
<text x="83.2" y="138.2">183</text>
<text x="83.2" y="140.7">185</text>
<text x="83.2" y="143.3">187</text>
<text x="27.3" y="145.8">190</text>
<text x="27.3" y="148.3">192</text>
<text x="83.2" y="145.8">189</text>
<text x="83.2" y="148.3">191</text>
<text x="185.2" y="146.1" transform="rotate(-90 185.2 146.1)">37</text>
<text x="27.3" y="150.9">194</text>
<text x="27.3" y="153.4">196</text>
<text x="27.3" y="156">198</text>
<text x="83.2" y="150.9">193</text>
<text x="83.2" y="153.4">195</text>
<text x="83.2" y="156">197</text>
<text x="27.3" y="158.5">200</text>
<text x="83.2" y="158.5">199</text>
</g>
<g font-size="1.3" fill="#725600">
<text x="190.7" y="30.1">CM4_3V</text>
<text x="194.5" y="68.2">CM4_3V</text>
<text x="241.5" y="88.5">USB_RP_P</text>
<text x="241.5" y="86">USB_RP_N</text>
<text x="123.8" y="98.7">nEXTRST</text>
<text x="113.2" y="174.9">CM4_3V</text>
</g>
<g font-size="1.3" fill="#0f0f0f">
<text x="165.1" y="41.6">USB_CM_N</text>
<text x="165.1" y="39">USB_CM_P</text>
<text x="205.7" y="41.6">USB_D_N</text>
<text x="205.7" y="39">USB_D_P</text>
<text x="172.7" y="59.3">USB_UP_N</text>
<text x="172.7" y="61.9">USB_UP_P</text>
<text x="254" y="69.5">VBUS</text>
<text x="218.4" y="92.4">nOCS1</text>
<text x="226.1" y="97.4">USB_OUT_N</text>
<text x="226.1" y="100">USB_OUT_P</text>
<text x="252.7" y="97.4">VBUS</text>
<text x="218.4" y="105.1">nOCS1</text>
<text x="218.4" y="117.8">nOCS1</text>
<text x="218.4" y="130.5">nOCS1</text>
</g>
<g font-size="1" fill="#006464">
<text x="190.9" y="40.1">HSD2+</text>
<text x="190.9" y="47.7">HSD1+</text>
<text x="190.9" y="42.6">HSD2-</text>
<text x="190.9" y="50.3">HSD1-</text>
</g>
</g></defs>
<g fill="none" stroke="#840000" stroke-width=".15">
<path d="M10 10h277v190h-277zM12 12h273v186h-273zM60 10v2M110 10v2M160 10v2M210 10v2M260 10v2M158.7 24.1v.8M158.7 28.4v.8M10 60h2M254 73.7v.7M254 78v.7"/>
<path d="M285 60h2M10 110h2M118.1 113h1.3M119.9 111.5h1.5v3.1h-1.5zM121.9 113h1.3M285 110h2M91.4 157.5v1.3h1.3l-1.3 1.2-1.2-1.2h1.2M91.4 157.5h.1M10 160h2M177 166h108v32h-108zM285 160h2M60 198v2"/>
<path d="M110 198v2M160 198v2M177 194.5h108M177 191.5h108M177 187.5h108M177 181.5h108M197 191.5v3M210 198v2M260 198v2M261 191.5v6.5"/>
</g>
<path d="M158 24.9h1.5v3.5h-1.5zM253.2 74.4h1.6v3.6h-1.6z" fill="none" stroke="#840000" stroke-width=".2"/>
<path d="M119.4 112.3v1.5M121.9 112.3v1.5" fill="none" stroke="#840000" stroke-width=".38"/>
<path d="M265.4 95.3h10.2v15.2h-10.2z" fill="#ffffc2"/>
<path d="M265.4 95.3h10.2v15.2h-10.2zM271.1 99.4h.7l1.2 1.3h.7M269.9 100.7h2.5M273 100.7h-.6l-.6 1.3h-1.3" fill="none" stroke="#840000" stroke-width=".25"/>
<g fill="#840000" stroke="#840000" stroke-width=".25">
<path d="M270.3 101.6h.7v.8h-.7z"/>
<path d="M268.6 100.7l1.3-.6v1.2z"/>
<circle cx="274.3" cy="100.7" r=".63"/>
<circle cx="271.1" cy="99.4" r=".38"/>
</g>
<path d="M272 97.5h2.8v.5h-2.8z" fill="#840000" stroke="#840000" stroke-width=".15"/>
<g fill="none" stroke="#840000" stroke-width=".15">
<path d="M26.7 34.3h5M26.7 36.8h5M26.7 39.4h5M31.7 31.8h50.8v129.5h-50.8zM82.5 34.3h5.1M82.5 36.8h5.1M82.5 39.4h5.1M26.7 41.9h5M26.7 44.5h5M26.7 47h5M26.7 49.5h5M26.7 52.1h5"/>
<path d="M26.7 54.6h5M26.7 57.2h5M26.7 59.7h5M82.5 41.9h5.1M82.5 44.5h5.1M82.5 47h5.1M82.5 49.5h5.1M82.5 52.1h5.1M82.5 54.6h5.1M82.5 57.2h5.1M82.5 59.7h5.1M189.2 54.6v1.3h1.3l-1.3 1.3-1.2-1.3h1.2"/>
<path d="M189.2 54.6h.1M232.4 57.2v1.2h1.3l-1.3 1.3-1.3-1.3h1.3M232.4 57.2h.1M236.2 53.3h2.1M239.3 53.3h2M26.7 62.2h5M26.7 64.8h5M26.7 67.3h5M26.7 69.9h5M26.7 72.4h5M26.7 74.9h5M26.7 77.5h5"/>
<path d="M82.5 62.2h5.1M82.5 64.8h5.1M82.5 67.3h5.1M82.5 69.9h5.1M82.5 72.4h5.1M82.5 74.9h5.1M82.5 77.5h5.1M217.2 67.3h.1M217.2 64.8v2.5M217.2 69.9v2M217.2 72.9v2M217.2 64.8l-.8 1.2"/>
<path d="M217.2 64.8l.7 1.2M223.5 77.5v1.2h1.3l-1.3 1.3-1.3-1.3h1.3M223.5 77.5h.1M228.6 69.9h2.5M228.6 72.4h2.5M228.6 74.9h2.5M231.1 67.3h11.5v10.2h-11.5zM242.6 69.9h2.5M242.6 72.4h2.5M242.6 74.9h2.5M281.9 71.1v2.1M281.9 74.2v2"/>
<path d="M26.7 97.8h5M26.7 80h5M26.7 82.6h5M26.7 85.1h5M26.7 87.6h5M26.7 90.2h5M26.7 92.7h5M26.7 95.3h5M82.5 97.8h5.1M82.5 80h5.1M82.5 82.6h5.1M82.5 85.1h5.1"/>
<path d="M82.5 87.6h5.1M82.5 90.2h5.1M82.5 92.7h5.1M82.5 95.3h5.1M260.3 82.6v1.2h1.3l-1.3 1.3-1.2-1.3h1.2M260.3 82.6h.1M262.9 97.8h2.5M265.4 97.7h.8v.2h-.8zM271.8 97h3.3v1.3h-3.3zM26.7 105.4h5M26.7 102.9h5M26.7 100.3h5"/>
<path d="M26.7 108h5M26.7 110.5h5M26.7 113h5M26.7 115.6h5M26.7 118.1h5M82.5 105.4h5.1M82.5 102.9h5.1M82.5 100.3h5.1M82.5 108h5.1M82.5 110.5h5.1M82.5 113h5.1M82.5 115.6h5.1"/>
<path d="M82.5 118.1h5.1M128.3 116.8v2.1M128.3 119.9v2M138.4 106.7v1.3h1.3l-1.3 1.2-1.2-1.2h1.2M138.4 106.7h.1M142.2 105.4h.8M146.6 105.4h.7M262.9 105.4h2.5M262.9 102.9h2.5M265.4 102.7h.8v.3h-.8zM265.4 105.3h.8v.2h-.8zM270.4 109.7h.2v.8h-.2z"/>
<path d="M270.5 110.5v2.5M273 110.5v2.5M275.6 115.6h2M278.6 115.6h2.1M26.7 120.7h5M26.7 123.2h5M26.7 125.7h5M26.7 128.3h5M26.7 130.8h5M26.7 133.4h5M26.7 135.9h5M26.7 138.4h5"/>
<path d="M82.5 120.7h5.1M82.5 123.2h5.1M82.5 125.7h5.1M82.5 128.3h5.1M82.5 130.8h5.1M82.5 133.4h5.1M82.5 135.9h5.1M82.5 138.4h5.1M120.6 123.2v1.3h1.3l-1.3 1.2-1.2-1.2h1.2M120.6 123.2h.1M130.8 130.8h.8M135.1 130.8h.8"/>
<path d="M135.9 128.3h.8M140.2 128.3h.8M270.5 120.7v1.2h1.3l-1.3 1.3-1.3-1.3h1.3M270.5 120.7h.1M24.1 157.5v1.3h1.3l-1.3 1.2-1.2-1.2h1.2M24.1 157.5h.1M26.7 141h5M26.7 143.5h5M26.7 146.1h5M26.7 148.6h5M26.7 151.1h5M26.7 153.7h5"/>
<path d="M26.7 156.2h5M26.7 158.8h5M82.5 141h5.1M82.5 143.5h5.1M82.5 146.1h5.1M82.5 148.6h5.1M82.5 151.1h5.1M82.5 153.7h5.1M82.5 156.2h5.1M82.5 158.8h5.1M185.4 148.6v1.3h1.3l-1.3 1.2-1.3-1.2h1.3M185.4 148.6h.1"/>
<path d="M62.2 177.8v2M71.1 177.8v2M62.2 180.8v2.1M71.1 180.8v2.1"/>
</g>
<path d="M238.3 51.8v3.1M215.6 71.9h3.1M280.4 73.2h3.1M126.7 118.9h3.1M277.6 114v3.1M60.7 179.8h3.1M69.6 179.8h3" fill="none" stroke="#840000" stroke-width=".3"/>
<path d="M239.3 51.8v3.1M215.6 72.9h3.1M280.4 74.2h3.1M126.7 119.9h3.1M278.6 114v3.1M60.7 180.8h3.1M69.6 180.8h3" fill="none" stroke="#840000" stroke-width=".33"/>
<path d="M143 104.6h3.6v1.6h-3.6zM131.6 130h3.5v1.6h-3.5zM136.7 127.5h3.5v1.5h-3.5z" fill="none" stroke="#840000" stroke-width=".2"/>
<path d="M227.3 31.8h10.2v15.2h-10.2z" fill="#ffffc2"/>
<path d="M227.3 31.8h10.2v15.2h-10.2zM231.8 37.2h2.5M233 35.9h.7l1.2 1.3h.7M234.9 37.2h-.6l-.6 1.3h-1.3" fill="none" stroke="#840000" stroke-width=".25"/>
<g fill="none" stroke="#840000" stroke-width=".15">
<path d="M224.8 34.3h2.5M224.8 39.4h2.5M227.3 34.2h.8v.2h-.8zM227.3 39.2h.8v.3h-.8zM233.8 33.5h3.3v.3l-.2 1h-2.8zM224.8 41.9h2.5M224.8 44.5h2.5M227.3 41.8h.8v.2h-.8zM227.3 44.3h.8v.3h-.8zM232.3 46.2h.2v.8h-.2zM232.4 47v2.5M234.9 47v2.5"/>
<path d="M119.4 137.2v1.2h1.2l-1.2 1.3-1.3-1.3h1.3M119.4 137.2h.1M120.6 135.9h.8M125 135.9h.7M125.7 133.4h.8M130 133.4h.8M111.8 177.8v2M111.8 180.8v2.1"/>
</g>
<path d="M234.2 33.8h2.5l-.2 .7h-2.1z" fill="#840000" stroke="#840000" stroke-width=".15"/>
<g fill="#840000" stroke="#840000" stroke-width=".25">
<path d="M232.2 38.1h.7v.8h-.7z"/>
<path d="M230.5 37.2l1.3-.6v1.2z"/>
<circle cx="236.2" cy="37.2" r=".63"/>
<circle cx="233" cy="35.9" r=".38"/>
</g>
<path d="M121.4 135.1h3.6v1.6h-3.6zM126.5 132.6h3.5v1.5h-3.5z" fill="none" stroke="#840000" stroke-width=".2"/>
<path d="M110.2 179.8h3.1" fill="none" stroke="#840000" stroke-width=".3"/>
<path d="M110.2 180.8h3.1" fill="none" stroke="#840000" stroke-width=".33"/>
<path d="M251.5 31.8h15.2v15.2h-15.2z" fill="#ffffc2"/>
<g fill="none" stroke="#840000" stroke-width=".15">
<path d="M246.4 36.8h9.5M246.4 31.8h5.1M252.7 34.3h1.3M253.4 32.9h11.4v13.1h-11.4zM253.4 34.3l.6 1.3h-1.3zM255.3 34.3h1.2M255.9 34.3l.6 1.3h-1.2zM255.9 32.9v13.1M259.1 38.5l.6 1.3h-1.3zM259.1 32.9v19.2M260.1 38.2l-.4 .3h-1.3l-.3 .2M261.6 34.3h1.3"/>
<path d="M262.3 34.3l.6 1.3h-1.3zM262.3 32.9v13.1M264.2 34.3h1.2M264.8 34.3l.6 1.3h-1.2zM264.8 36.8h7M266.7 31.8h5.1M246.4 41.9h7M246.4 47h5.1M252.7 43.2h1.3M253.4 43.2l.6 1.3h-1.3zM255.3 43.2h1.2M255.9 43.2l.6 1.3h-1.2z"/>
<path d="M261.6 43.2h1.3M262.3 43.2l.6 1.3h-1.3zM262.3 41.9h9.5M264.2 43.2h1.2M264.8 43.2l.6 1.3h-1.2zM266.7 47h5.1M258.1 72.6h4.5v.6h-4.5zM260.3 69.9v2.7M260.3 74.7v2.8M261.1 71.4h1M261.6 70.9v1M266.7 71.1v2.1"/>
<path d="M266.7 74.2v2M271.8 71.1v2.1M271.8 74.2v2M114.3 116.8v2.1M114.3 119.9v2M100.3 177.8v2M100.3 180.8v2.1"/>
</g>
<path d="M251.5 31.8h15.2v15.2h-15.2z" fill="none" stroke="#840000" stroke-width=".25"/>
<g fill="#840000" stroke="#840000" stroke-width=".15">
<path d="M258.1 74.2h4.5v.5h-4.5z"/>
<circle cx="253.4" cy="41.9" r=".28"/>
<circle cx="255.9" cy="32.9" r=".28"/>
<circle cx="255.9" cy="36.8" r=".28"/>
<circle cx="255.9" cy="46" r=".28"/>
<circle cx="259.1" cy="32.9" r=".28"/>
<circle cx="259.1" cy="46" r=".28"/>
<circle cx="262.3" cy="32.9" r=".28"/>
<circle cx="262.3" cy="41.9" r=".28"/>
<circle cx="262.3" cy="46" r=".28"/>
<circle cx="264.8" cy="36.8" r=".28"/>
</g>
<path d="M265.2 73.2h3M270.3 73.2h3M112.8 118.9h3M98.8 179.8h3.1" fill="none" stroke="#840000" stroke-width=".3"/>
<path d="M265.2 74.2h3M270.3 74.2h3M112.8 119.9h3M98.8 180.8h3.1" fill="none" stroke="#840000" stroke-width=".33"/>
<path d="M181.6 36.8h15.2v15.3h-15.2z" fill="#ffffc2"/>
<path d="M181.6 36.8h15.2v15.3h-15.2z" fill="none" stroke="#840000" stroke-width=".25"/>
<g fill="none" stroke="#840000" stroke-width=".15">
<path d="M179.1 39.4h2.5M189.2 34.3v2.5M196.8 39.4h2.6M148.6 52.1v1.2h1.3l-1.3 1.3-1.3-1.3h1.3M148.6 52.1h.1M151.1 49.5h.8M155.4 49.5h.8M179.1 49.5h2.5M179.1 41.9h2.5M179.1 47h2.5M189.2 52.1v2.5M196.8 49.5h2.6"/>
<path d="M196.8 41.9h2.6M196.8 47h2.6M259.1 52.1v1.2h1.2l-1.2 1.3-1.3-1.3h1.3M259.1 52.1h.1M90.2 177.8v2M90.2 180.8v2.1"/>
</g>
<path d="M182.2 45.9h2.5" fill="none" stroke="#006464" stroke-width=".15"/>
<path d="M88.6 179.8h3.1" fill="none" stroke="#840000" stroke-width=".3"/>
<path d="M88.6 180.8h3.1" fill="none" stroke="#840000" stroke-width=".33"/>
<path d="M151.9 48.8h3.5v1.5h-3.5z" fill="none" stroke="#840000" stroke-width=".2"/>
<path d="M160 72.4h50.8v71.1h-50.8z" fill="#ffffc2"/>
<path d="M160 72.4h50.8v71.1h-50.8z" fill="none" stroke="#840000" stroke-width=".25"/>
<g fill="none" stroke="#840000" stroke-width=".15">
<path d="M179.1 39.4h2.5M189.2 34.3v2.5M196.8 39.4h2.6M224.8 39.4h2.5M224.8 34.3h2.5M246.4 36.8h5.1M246.4 31.8h5.1M266.7 36.8h5.1M266.7 31.8h5.1M179.1 49.5h2.5M179.1 41.9h2.5M179.1 47h2.5"/>
<path d="M189.2 54.6h.1M189.2 52.1v2.5M196.8 49.5h2.6M196.8 41.9h2.6M196.8 47h2.6M224.8 41.9h2.5M224.8 44.5h2.5M232.4 57.2h.1M232.4 47v2.5M234.9 47v2.5M236.2 53.3h2.1M239.3 53.3h2"/>
<path d="M246.4 41.9h5.1M246.4 47h5.1M259.1 52.1h.1M259.1 47v5.1M266.7 41.9h5.1M266.7 47h5.1M177.8 69.9v2.5M180.3 69.9v2.5M182.9 69.9v2.5M185.4 69.9v2.5M190.5 69.9v2.5M193 69.9v2.5"/>
<path d="M266.7 71.1v2.1M266.7 74.2v2M271.8 71.1v2.1M271.8 74.2v2M276.9 71.1v2.1M276.9 74.2v2M281.9 71.1v2.1M281.9 74.2v2M157.5 85.1h2.5M157.5 97.8h2.5M157.5 90.2h2.5M157.5 92.7h2.5"/>
<path d="M210.8 85.1h2.6M210.8 87.6h2.6M210.8 97.8h2.6M210.8 90.2h2.6M210.8 92.7h2.6M262.9 97.8h2.5M157.5 100.3h2.5M157.5 110.5h2.5M157.5 113h2.5M157.5 105.4h2.5M157.5 118.1h2.5M160 109.9l1.3 .6-1.3 .6"/>
<path d="M210.8 100.3h2.6M210.8 110.5h2.6M210.8 113h2.6M210.8 102.9h2.6M210.8 105.4h2.6M210.8 115.6h2.6M210.8 118.1h2.6M262.9 102.9h2.5M262.9 105.4h2.5M270.5 110.5v2.5M273 110.5v2.5M275.6 115.6h2"/>
<path d="M278.6 115.6h2.1M120.6 135.9h.8M125 135.9h.7M125.7 133.4h.8M130 133.4h.8M130.8 130.8h.8M135.1 130.8h.8M135.9 128.3h.8M140.2 128.3h.8M157.5 120.7h2.5M157.5 128.3h2.5M157.5 130.8h2.5"/>
<path d="M157.5 135.9h2.5M157.5 133.4h2.5M210.8 123.2h2.6M210.8 125.7h2.6M210.8 128.3h2.6M210.8 130.8h2.6M185.4 148.6h.1M185.4 143.5v2.6M80 177.8v2M80 180.8v2.1M86.4 189.2v1.3h1.2l-1.2 1.3-1.3-1.3h1.3M86.4 189.2h.1"/>
</g>
<path d="M275.3 73.2h3.1M78.5 179.8h3" fill="none" stroke="#840000" stroke-width=".3"/>
<path d="M275.3 74.2h3.1M78.5 180.8h3" fill="none" stroke="#840000" stroke-width=".33"/>
<path d="M189.2 29.2l.7-.6h.6v1.2h-.6zM193.7 66.7h.6v1.2h-.6l-.7-.6zM132.1 97.2h.6l.6 .6-.6 .6h-.6zM240.7 87h.6v1.3h-.6l-.7-.7zM240.7 84.5h.6v1.2h-.6l-.7-.6zM112.4 173.4h.6v1.2h-.6l-.6-.6z" fill="none" stroke="#725600" stroke-width=".15"/>
<g fill="none" stroke="#009600" stroke-width=".15">
<path d="M87.6 34.3h71.1M87.6 36.8h67.3v5.1h24.2M87.6 39.4h91.5M158.7 24.1v-5h61v15.2h5.1M158.7 29.2v20.3M189.2 29.2v5.1M199.4 39.4h25.4M24.1 49.5h2.6M24.1 57.2h2.6M26.7 41.9h-2.6v115.6h1.3v-1.3h1.3M87.6 41.9h3.8v115.6h-1.2v-1.3h-2.6M87.6 49.5h3.8"/>
<path d="M87.6 57.2h3.8M151.1 49.5h-2.5v2.6M156.2 49.5h22.9M179.1 47h-2.6v7.6h12.7M199.4 41.9h25.4M199.4 49.5h3.8v10.2h-57.2v30.5h11.5M199.4 47h6.3v15.2h-57.1v30.5h8.9M232.4 49.5v7.7h11.4v-3.9h-2.5M234.9 49.5v3.8h1.3M24.1 72.4h2.6M24.1 64.8h2.6M87.6 72.4h3.8"/>
<path d="M87.6 64.8h3.8M177.8 67.3v2.6M180.3 67.3v2.6M182.9 67.3v2.6M185.4 67.3v2.6M190.5 67.3v2.6M193 69.9v-2.6h-35.5v17.8M217.2 67.3v2.6h11.4M223.5 76.2v1.3M228.6 72.4h-2.5v3.8h-8.9v-1.3M228.6 74.9v15.3h-15.2M245.1 72.4h8.9v1.3"/>
<path d="M245.1 69.9h36.8v1.2M245.1 74.9h6.4M260.3 77.5v5.1M266.7 69.9v1.2M266.7 76.2v3.8M271.8 69.9v1.2M271.8 76.2v3.8M276.9 69.9v1.2M276.9 76.2v3.8M281.9 76.2v3.8h-27.9v-1.3M24.1 80h2.6M24.1 87.6h2.6"/>
<path d="M24.1 95.3h2.6M87.6 80h3.8M133.3 97.8h24.2M213.4 87.6h26.6M213.4 92.7h5M213.4 85.1h26.6M213.4 97.8h30.4v7.6h19.1M252.7 97.8h10.2M24.1 118.1h2.6M24.1 102.9h2.6M24.1 110.5h2.6M87.6 118.1h3.8"/>
<path d="M87.6 102.9h3.8M87.6 110.5h3.8M114.3 113h3.8M123.2 113h34.3M128.3 113v3.8M142.2 105.4h-3.8v1.3M147.3 105.4h10.2M157.5 110.5h-43.2v6.3M213.4 118.1h5M213.4 100.3h27.9v2.6h21.6M213.4 105.4h5M270.5 113v7.7h11.4v-5.1h-1.2"/>
<path d="M273 113v2.6h2.6M24.1 133.4h2.6M24.1 125.7h2.6M87.6 133.4h3.8M87.6 125.7h3.8M114.3 121.9h14M119.4 130.8h11.4M119.4 133.4h6.3M119.4 135.9h1.2M120.6 121.9v1.3M125.7 135.9h31.8M130.8 133.4h26.7"/>
<path d="M135.9 128.3h-16.5v8.9M135.9 130.8h21.6M141 128.3h16.5M213.4 130.8h5M24.1 148.6h2.6M24.1 141h2.6M87.6 148.6h3.8M87.6 141h3.8M185.4 146.1v2.5M62.2 177.8v-3.8h49.6v3.8M71.1 174v3.8M80 174v3.8"/>
<path d="M90.2 174v3.8M100.3 174v3.8M62.2 182.9v3.8h49.6v-3.8M71.1 182.9v3.8M80 182.9v3.8M86.4 186.7v2.5M90.2 182.9v3.8M100.3 182.9v3.8"/>
</g>
<g fill="none" stroke="#000084" stroke-width=".15">
<path d="M26.1 38.8l1.2 1.2M26.1 33.7l1.2 1.2M26.1 36.2l1.2 1.2M27.3 38.8l-1.2 1.2M27.3 33.7l-1.2 1.2M27.3 36.2l-1.2 1.2M245.8 36.2l1.2 1.2M247 36.2l-1.2 1.2M26.1 46.4l1.2 1.2M26.1 43.8l1.2 1.3M26.1 51.5l1.2 1.2M26.1 54l1.2 1.2"/>
<path d="M26.1 59.1l1.2 1.2M27.3 46.4l-1.2 1.2M27.3 43.8l-1.2 1.3M27.3 51.5l-1.2 1.2M27.3 54l-1.2 1.2M27.3 59.1l-1.2 1.2M87 46.4l1.2 1.2M87 43.8l1.2 1.3M87 59.1l1.2 1.2M87 54l1.2 1.2M87 51.5l1.2 1.2M88.2 46.4l-1.2 1.2"/>
<path d="M88.2 43.8l-1.2 1.3M88.2 59.1l-1.2 1.2M88.2 54l-1.2 1.2M88.2 51.5l-1.2 1.2M224.2 43.8l1.2 1.3M225.4 43.8l-1.2 1.3M245.8 41.3l1.2 1.2M247 41.3l-1.2 1.2M26.1 69.2l1.2 1.3M26.1 66.7l1.2 1.2M26.1 76.9l1.2 1.2M26.1 74.3l1.2 1.2"/>
<path d="M26.1 61.6l1.2 1.2M27.3 69.2l-1.2 1.3M27.3 66.7l-1.2 1.2M27.3 76.9l-1.2 1.2M27.3 74.3l-1.2 1.2M27.3 61.6l-1.2 1.2M87 74.3l1.2 1.2M87 76.9l1.2 1.2M87 61.6l1.2 1.2M87 66.7l1.2 1.2M87 69.2l1.2 1.3M88.2 66.7l-1.2 1.2"/>
<path d="M88.2 74.3l-1.2 1.2M88.2 76.9l-1.2 1.2M88.2 61.6l-1.2 1.2M88.2 69.2l-1.2 1.3M26.1 81.9l1.2 1.3M26.1 92.1l1.2 1.2M26.1 89.6l1.2 1.2M26.1 84.5l1.2 1.2M26.1 97.2l1.2 1.2M26.1 99.7l1.2 1.2M27.3 81.9l-1.2 1.3M27.3 92.1l-1.2 1.2"/>
<path d="M27.3 89.6l-1.2 1.2M27.3 84.5l-1.2 1.2M27.3 97.2l-1.2 1.2M27.3 99.7l-1.2 1.2M87 81.9l1.2 1.3M87 92.1l1.2 1.2M87 94.6l1.2 1.3M87 84.5l1.2 1.2M87 97.2l1.2 1.2M87 99.7l1.2 1.2M87 89.6l1.2 1.2M87 87l1.2 1.2"/>
<path d="M88.2 81.9l-1.2 1.3M88.2 92.1l-1.2 1.2M88.2 94.6l-1.2 1.3M88.2 84.5l-1.2 1.2M88.2 97.2l-1.2 1.2M88.2 99.7l-1.2 1.2M88.2 89.6l-1.2 1.2M88.2 87l-1.2 1.2M156.9 99.7l1.2 1.2M158.1 99.7l-1.2 1.2M26.1 104.8l1.2 1.2M26.1 107.3l1.2 1.3"/>
<path d="M26.1 115l1.2 1.2M26.1 112.4l1.2 1.2M27.3 104.8l-1.2 1.2M27.3 107.3l-1.2 1.3M27.3 112.4l-1.2 1.2M27.3 115l-1.2 1.2M87 115l1.2 1.2M87 112.4l1.2 1.2M87 104.8l1.2 1.2M87 107.3l1.2 1.3M88.2 115l-1.2 1.2M88.2 112.4l-1.2 1.2"/>
<path d="M88.2 104.8l-1.2 1.2M88.2 107.3l-1.2 1.3M156.9 117.5l1.2 1.2M158.1 117.5l-1.2 1.2M212.8 112.4l1.2 1.2M212.8 109.9l1.2 1.2M212.8 115l1.2 1.2M212.8 102.3l1.2 1.2M214 112.4l-1.2 1.2M214 109.9l-1.2 1.2M214 115l-1.2 1.2M214 102.3l-1.2 1.2"/>
<path d="M26.1 127.7l1.2 1.2M26.1 135.3l1.2 1.2M26.1 137.8l1.2 1.2M26.1 120l1.2 1.3M26.1 122.6l1.2 1.2M26.1 130.2l1.2 1.2M27.3 127.7l-1.2 1.2M27.3 137.8l-1.2 1.2M27.3 135.3l-1.2 1.2M27.3 122.6l-1.2 1.2M27.3 120l-1.2 1.3M27.3 130.2l-1.2 1.2"/>
<path d="M87 130.2l1.2 1.2M87 127.7l1.2 1.2M87 137.8l1.2 1.2M87 135.3l1.2 1.2M87 122.6l1.2 1.2M87 120l1.2 1.3M88.2 130.2l-1.2 1.2M88.2 127.7l-1.2 1.2M88.2 137.8l-1.2 1.2M88.2 135.3l-1.2 1.2M88.2 122.6l-1.2 1.2M88.2 120l-1.2 1.3"/>
<path d="M156.9 120l1.2 1.3M158.1 120l-1.2 1.3M212.8 125.1l1.2 1.2M212.8 127.7l1.2 1.2M212.8 122.6l1.2 1.2M214 125.1l-1.2 1.2M214 127.7l-1.2 1.2M214 122.6l-1.2 1.2M26.1 142.9l1.2 1.2M26.1 150.5l1.2 1.2M26.1 145.4l1.2 1.3M26.1 153.1l1.2 1.2"/>
<path d="M26.1 158.1l1.2 1.3M27.3 142.9l-1.2 1.2M27.3 153.1l-1.2 1.2M27.3 158.1l-1.2 1.3M27.3 150.5l-1.2 1.2M27.3 145.4l-1.2 1.3M87 145.4l1.2 1.3M87 158.1l1.2 1.3M87 153.1l1.2 1.2M87 142.9l1.2 1.2M87 150.5l1.2 1.2M88.2 145.4l-1.2 1.3"/>
<path d="M88.2 158.1l-1.2 1.3M88.2 153.1l-1.2 1.2M88.2 142.9l-1.2 1.2M88.2 150.5l-1.2 1.2"/>
</g>
<path d="M182.2 45.9h2.5" fill="none" stroke="#006464" stroke-width=".15"/>
<g fill="#009600" stroke="#009600" stroke-width=".13">
<circle cx="182.9" cy="67.3" r=".46"/>
<circle cx="180.3" cy="67.3" r=".46"/>
<circle cx="189.2" cy="54.6" r=".46"/>
<circle cx="158.7" cy="49.5" r=".46"/>
<circle cx="185.4" cy="67.3" r=".46"/>
<circle cx="177.8" cy="67.3" r=".46"/>
<circle cx="158.7" cy="34.3" r=".46"/>
<circle cx="217.2" cy="69.9" r=".46"/>
<circle cx="223.5" cy="76.2" r=".46"/>
<circle cx="232.4" cy="57.2" r=".46"/>
<circle cx="190.5" cy="67.3" r=".46"/>
<circle cx="260.3" cy="80" r=".46"/>
<circle cx="266.7" cy="80" r=".46"/>
<circle cx="276.9" cy="80" r=".46"/>
<circle cx="271.8" cy="80" r=".46"/>
<circle cx="276.9" cy="69.9" r=".46"/>
<circle cx="271.8" cy="69.9" r=".46"/>
<circle cx="260.3" cy="69.9" r=".46"/>
<circle cx="266.7" cy="69.9" r=".46"/>
<circle cx="114.3" cy="113" r=".46"/>
<circle cx="120.6" cy="121.9" r=".46"/>
<circle cx="91.4" cy="118.1" r=".46"/>
<circle cx="119.4" cy="130.8" r=".46"/>
<circle cx="128.3" cy="113" r=".46"/>
<circle cx="270.5" cy="120.7" r=".46"/>
<circle cx="91.4" cy="157.5" r=".46"/>
<circle cx="71.1" cy="186.7" r=".46"/>
<circle cx="91.4" cy="148.6" r=".46"/>
<circle cx="91.4" cy="133.4" r=".46"/>
<circle cx="91.4" cy="141" r=".46"/>
<circle cx="119.4" cy="135.9" r=".46"/>
<circle cx="119.4" cy="133.4" r=".46"/>
<circle cx="24.1" cy="80" r=".46"/>
<circle cx="24.1" cy="72.4" r=".46"/>
<circle cx="24.1" cy="95.3" r=".46"/>
<circle cx="24.1" cy="110.5" r=".46"/>
<circle cx="24.1" cy="118.1" r=".46"/>
<circle cx="24.1" cy="87.6" r=".46"/>
<circle cx="24.1" cy="102.9" r=".46"/>
<circle cx="91.4" cy="72.4" r=".46"/>
<circle cx="91.4" cy="57.2" r=".46"/>
<circle cx="91.4" cy="64.8" r=".46"/>
<circle cx="91.4" cy="49.5" r=".46"/>
<circle cx="24.1" cy="133.4" r=".46"/>
<circle cx="24.1" cy="141" r=".46"/>
<circle cx="91.4" cy="125.7" r=".46"/>
<circle cx="24.1" cy="157.5" r=".46"/>
<circle cx="24.1" cy="125.7" r=".46"/>
<circle cx="24.1" cy="148.6" r=".46"/>
<circle cx="24.1" cy="57.2" r=".46"/>
<circle cx="24.1" cy="64.8" r=".46"/>
<circle cx="24.1" cy="49.5" r=".46"/>
<circle cx="80" cy="174" r=".46"/>
<circle cx="71.1" cy="174" r=".46"/>
<circle cx="86.4" cy="186.7" r=".46"/>
<circle cx="90.2" cy="186.7" r=".46"/>
<circle cx="90.2" cy="174" r=".46"/>
<circle cx="100.3" cy="174" r=".46"/>
<circle cx="100.3" cy="186.7" r=".46"/>
<circle cx="80" cy="186.7" r=".46"/>
<circle cx="91.4" cy="102.9" r=".46"/>
<circle cx="91.4" cy="110.5" r=".46"/>
<circle cx="91.4" cy="80" r=".46"/>
</g>
<use href="#words"/>
</svg>
